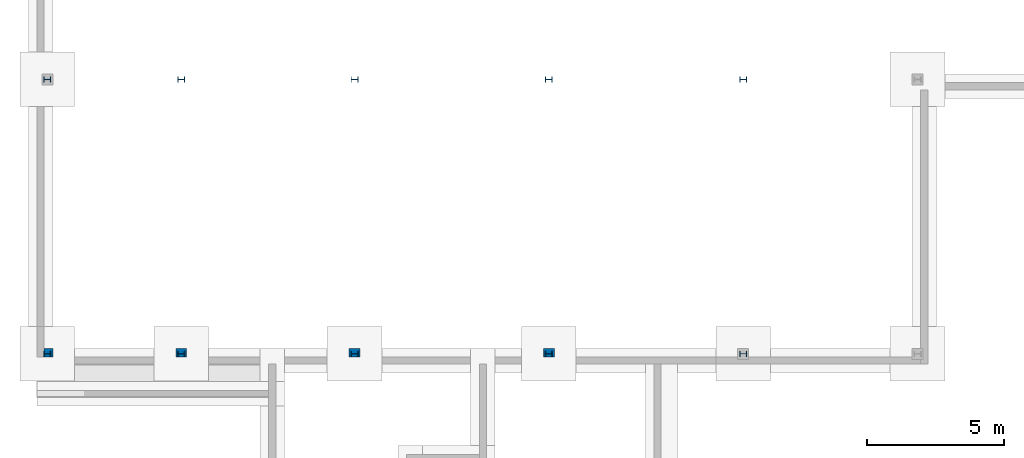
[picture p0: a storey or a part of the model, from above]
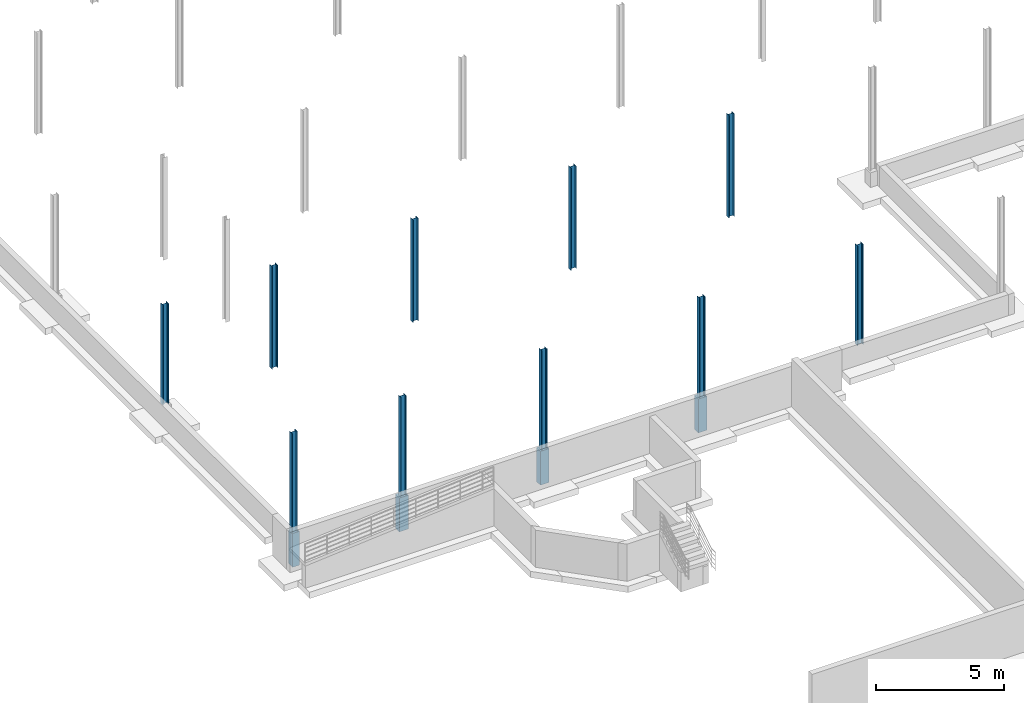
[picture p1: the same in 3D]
Properties of the parts of a building model (IFC2X3), part 1 of 3

# File
Description: ViewDefinition [CoordinationView]
File name: Project Number
Time: 2011-07-11T15:46:36
Written by: Autodesk Revit Architecture 2011 - 1.0
Made in: (Solibri IFC Optimizer)

# IfcProject, Project Number
Phase: Project Status

# IfcSite, Default
RefLatitude: 42, 21, 30, 344238; RefLongitude: -71, -3, -35, -194702; RefElevation: 0 m

# IfcBuilding
PSet_Revit_Other - Project Issue Date: Issue Date; Project Status: Project Status; Client Name: Owner; Project Address: Enter address here; Project Name: Project Name; Project Number: Project Number; Category Description: OmniClass Table 11 Description; Category Code: OmniClass Table 11 Code
Pset_BuildingCommon - NumberOfStoreys: 4

# IfcBuildingStorey (4)
PSet_Revit_Type_Dimensions - Automatic Room Computation Height: yes
PSet_Revit_Type_Graphics - Line Weight: 1; Color: 0; Line Pattern: Centre; Symbol: M_Level Head - Circle; Symbol at End 1 Default: no; Symbol at End 2 Default: yes
PSet_Revit_Type_Constraints - Elevation Base: 0
Name | Elevation (m) | Name | Category Code | PSet_Revit_Constraints, Elevation (m)
Roof - Main | 9.25 | Roof - Main | Roof | 9.25
Second Floor | 4.57 | Second Floor | Floor | 4.57
TOF Footing | -1 | TOF Footing | Site | -1
First Floor | -3.5315e-13 | First Floor | Floor | 0

# IfcBeam: M_K-Series Bar Joist-Rod Web:10K1:228953 (5)
In: First Floor
PSet_Revit_Construction - Start Offset: 0 m; Start Extension: 0 m; End Offset: 0 m; End Extension: 0 m
Pset_BeamCommon - Reference: M_K-Series Bar Joist-Rod Web:10K1; IsExternal: no; LoadBearing: yes; Span: 0.0095 m; Slope: 0 deg
PSet_Revit_Dimensions - Length: 2.367 m; Volume: 0.00307691 m3
PSet_Revit_Phasing - Phase Created: New Construction
PSet_Revit_Constraints - Work Plane: Level : Second Floor; Reference Level: Second Floor; Start Level Offset: 0 m; End Level Offset: 0 m; z-Direction Justification: 3; z-Direction Offset Value: -0.102 m; Lateral Justification: 0; Orientation: 0; Cross-Section Rotation: 0 deg
PSet_Revit_Structural Analysis - Start Release: 3; Start Fx: no; Start Fy: no; Start Fz: no; Start Mx: no; Start My: yes; Start Mz: yes; End Release: 1; End Fx: no; End Fy: no; End Fz: no; End Mx: yes; End My: yes; End Mz: yes; Analyze As: 1
PSet_Revit_Other - PanelArrayNum: 3; PanelArrayLength: 1.351 m; Panel: 0.450333 m; InstallationDate: InstallationDate; SerialNumber: SerialNumber; WarrantyStartDate: WarrantyStartDate; BarCode: BarCode; AssetIdentifier: AssetIdentifier; TagNumber: TagNumber
PSet_Revit_Analytical Model - Rigid Links: 0; Horizontal Projection: Default
PSet_Revit_Structural - Cut Length: 2.367 m; Structural Usage: 4
PSet_Revit_Type_Identity Data - Manufacturer: Manufacturer; OmniClass Number: 23.25.30.21.14.11; OmniClass Title: Metal Joists
PSet_Revit_Type_Dimensions - Web Thickness: 0.0095 m; Seat Length: 0.1 m; Seat Depth: 0.0635 m; Cord Leg: 0.032 m; Chord Thickness: 0.0065 m; Depth: 0.254 m
PSet_Revit_Type_Structural - M: 7.4
PSet_Revit_Type_Other - End Panel: 0.508 m; AccessibilityPerformance: AccessibilityPerformance; CodePerformance: CodePerformance; Color: Color; Constituents: Constituents; Features: Features; Finish: Finish; Grade: Grade; Material: Material; ModelReference: ModelReference; NominalHeight: NominalHeight; NominalLength: NominalLength; NominalWidth: NominalWidth; ProductionYear: ProductionYear; Reference: Reference; Shape: Shape; Size: Size; SustainabilityPerformance: SustainabilityPerformance; WarrantyDescription: WarrantyDescription; WarrantyDurationLabor: WarrantyDurationLabor; WarrantyDurationParts: WarrantyDurationParts; WarrantyGuarantorLabor: WarrantyGuarantorLabor; WarrantyGuarantorParts: WarrantyGuarantorParts; ExpectedLife: ExpectedLife; ReplacementCost: ReplacementCost; AssetAccountingType: FIXED; ModelLabel: ModelLabel
Name (M_K-Series Bar Joist-Rod Web:10K1:10K1:...)
228924
228926
228928
228920
228922

# IfcBeam: M_K-Series Bar Joist-Rod Web:14K1:175829 (456)
PSet_Revit_Construction - Start Offset: 0 m; Start Extension: 0 m; End Offset: 0 m; End Extension: 0 m
PSet_Revit_Phasing - Phase Created: New Construction
Pset_BeamCommon - Reference: M_K-Series Bar Joist-Rod Web:14K1; IsExternal: no; LoadBearing: yes; Span: 0.0095 m
PSet_Revit_Other - InstallationDate: InstallationDate; SerialNumber: SerialNumber; WarrantyStartDate: WarrantyStartDate; BarCode: BarCode; AssetIdentifier: AssetIdentifier; TagNumber: TagNumber
PSet_Revit_Constraints - Start Level Offset: 0 m; End Level Offset: 0 m; z-Direction Justification: 3; Lateral Justification: 0; Orientation: 0; Cross-Section Rotation: 0 deg
PSet_Revit_Structural Analysis - Start Release: 3; Start Fx: no; Start Fy: no; Start Fz: no; Start Mx: no; Start My: yes; Start Mz: yes; End Release: 1; End Fx: no; End Fy: no; End Fz: no; End Mx: yes; End My: yes; End Mz: yes; Analyze As: 1
PSet_Revit_Analytical Model - Rigid Links: 0; Horizontal Projection: Default
PSet_Revit_Structural - Structural Usage: 4
PSet_Revit_Type_Structural - M: 7.7
PSet_Revit_Type_Dimensions - Web Thickness: 0.0095 m; Seat Length: 0.1 m; Seat Depth: 0.0635 m; Cord Leg: 0.032 m; Chord Thickness: 0.0065 m; Depth: 0.356 m
PSet_Revit_Type_Identity Data - Manufacturer: Manufacturer; OmniClass Number: 23.25.30.21.14.11; OmniClass Title: Metal Joists
PSet_Revit_Type_Other - End Panel: 0.712 m; AccessibilityPerformance: AccessibilityPerformance; CodePerformance: CodePerformance; Color: Color; Constituents: Constituents; Features: Features; Finish: Finish; Grade: Grade; Material: Material; ModelReference: ModelReference; NominalHeight: NominalHeight; NominalLength: NominalLength; NominalWidth: NominalWidth; ProductionYear: ProductionYear; Reference: Reference; Shape: Shape; Size: Size; SustainabilityPerformance: SustainabilityPerformance; WarrantyDescription: WarrantyDescription; WarrantyDurationLabor: WarrantyDurationLabor; WarrantyDurationParts: WarrantyDurationParts; WarrantyGuarantorLabor: WarrantyGuarantorLabor; WarrantyGuarantorParts: WarrantyGuarantorParts; ExpectedLife: ExpectedLife; ReplacementCost: ReplacementCost; AssetAccountingType: FIXED; ModelLabel: ModelLabel
Name (M_K-Series Bar Joist-Rod Web:14K1:14K1:...) | In | Slope (deg) | PanelArrayNum | PanelArrayLength (m) | Panel (m) | Length (m) = Cut Length (m) | Volume (m3) | Work Plane | Reference Level | z-Direction Offset Value (m)
220116 | Second Floor | 0 | 11 | 7.545 | 0.685909 | 8.969 | 0.0126419 | Level : Roof - Main | Roof - Main | 0
220117 | Second Floor | 0 | 11 | 7.545 | 0.685909 | 8.969 | 0.0126419 | Level : Roof - Main | Roof - Main | 0
225612 | First Floor | 0 | 5 | 3.885 | 0.777 | 5.309 | 0.00717022 | Level : Second Floor | Second Floor | -0.102
220100 | Second Floor | 0 | 11 | 7.551 | 0.686455 | 8.975 | 0.0126509 | Level : Roof - Main | Roof - Main | 0
220081 | Second Floor | 1.30141e-30 | 11 | 7.551 | 0.686455 | 8.975 | 0.0126509 | Level : Roof - Main | Roof - Main | 0
189399 | Second Floor | 0 | 10 | 7.146 | 0.7146 | 8.57 | 0.0120454 | Level : Roof - Main | Roof - Main | 0
225467 | First Floor | 0 | 10 | 7.146 | 0.7146 | 8.57 | 0.0120454 | Level : Second Floor | Second Floor | -0.102
189397 | Second Floor | 0 | 10 | 7.146 | 0.7146 | 8.57 | 0.0120454 | Level : Roof - Main | Roof - Main | 0
225611 | First Floor | 0 | 5 | 3.885 | 0.777 | 5.309 | 0.00717022 | Level : Second Floor | Second Floor | -0.102
185401 | First Floor | 0 | 7 | 5.205 | 0.743571 | 6.629 | 0.00914362 | Level : Second Floor | Second Floor | -0.102
185451 | First Floor | 0 | 10 | 7.146 | 0.7146 | 8.57 | 0.0120454 | Level : Second Floor | Second Floor | -0.102
220080 | Second Floor | 1.30141e-30 | 11 | 7.551 | 0.686455 | 8.975 | 0.0126509 | Level : Roof - Main | Roof - Main | 0
185266 | First Floor | 0 | 6 | 4.626 | 0.771 | 6.05 | 0.00827801 | Level : Second Floor | Second Floor | -0.102
185267 | First Floor | 0 | 6 | 4.626 | 0.771 | 6.05 | 0.00827801 | Level : Second Floor | Second Floor | -0.102
220027 | Second Floor | 1.30141e-30 | 11 | 7.551 | 0.686455 | 8.975 | 0.0126509 | Level : Roof - Main | Roof - Main | 0
189395 | Second Floor | 0 | 10 | 7.146 | 0.7146 | 8.57 | 0.0120454 | Level : Roof - Main | Roof - Main | 0
220118 | Second Floor | 0 | 11 | 7.545 | 0.685909 | 8.969 | 0.0126419 | Level : Roof - Main | Roof - Main | 0
189398 | Second Floor | 0 | 10 | 7.146 | 0.7146 | 8.57 | 0.0120454 | Level : Roof - Main | Roof - Main | 0
189623 | Second Floor | 2.01996e-30 | 5 | 3.885 | 0.777 | 5.309 | 0.00717022 | Level : Roof - Main | Roof - Main | 0
185555 | First Floor | 0 | 10 | 7.146 | 0.7146 | 8.57 | 0.0120454 | Level : Second Floor | Second Floor | -0.102
189620 | Second Floor | 2.01996e-30 | 5 | 3.885 | 0.777 | 5.309 | 0.00717022 | Level : Roof - Main | Roof - Main | 0
190259 | Second Floor | 1.97385e-30 | 10 | 7.146 | 0.7146 | 8.57 | 0.0120454 | Level : Roof - Main | Roof - Main | 0
220061 | Second Floor | 0 | 11 | 7.551 | 0.686455 | 8.975 | 0.0126509 | Level : Roof - Main | Roof - Main | 0
220060 | Second Floor | 0 | 11 | 7.551 | 0.686455 | 8.975 | 0.0126509 | Level : Roof - Main | Roof - Main | 0
225615 | First Floor | 0 | 5 | 3.885 | 0.777 | 5.309 | 0.00717022 | Level : Second Floor | Second Floor | -0.102
185400 | First Floor | 0 | 7 | 5.205 | 0.743571 | 6.629 | 0.00914362 | Level : Second Floor | Second Floor | -0.102
185287 | First Floor | 0 | 12 | 8.346 | 0.6955 | 9.77 | 0.0138394 | Level : Second Floor | Second Floor | -0.102
185450 | First Floor | 0 | 10 | 7.146 | 0.7146 | 8.57 | 0.0120454 | Level : Second Floor | Second Floor | -0.102
189973 | Second Floor | 0 | 10 | 7.146 | 0.7146 | 8.57 | 0.0120454 | Level : Roof - Main | Roof - Main | 0
220097 | Second Floor | 0 | 11 | 7.551 | 0.686455 | 8.975 | 0.0126509 | Level : Roof - Main | Roof - Main | 0
185556 | First Floor | 0 | 10 | 7.146 | 0.7146 | 8.57 | 0.0120454 | Level : Second Floor | Second Floor | -0.102
185269 | First Floor | 0 | 6 | 4.626 | 0.771 | 6.05 | 0.00827801 | Level : Second Floor | Second Floor | -0.102
185362 | First Floor | 0 | 5 | 3.885 | 0.777 | 5.309 | 0.00717022 | Level : Second Floor | Second Floor | -0.102
185557 | First Floor | 0 | 10 | 7.146 | 0.7146 | 8.57 | 0.0120454 | Level : Second Floor | Second Floor | -0.102
190260 | Second Floor | 1.97385e-30 | 10 | 7.146 | 0.7146 | 8.57 | 0.0120454 | Level : Roof - Main | Roof - Main | 0
185553 | First Floor | 0 | 10 | 7.146 | 0.7146 | 8.57 | 0.0120454 | Level : Second Floor | Second Floor | -0.102
231532 | Second Floor | 0 | 11 | 7.551 | 0.686455 | 8.975 | 0.0126509 | Level : Roof - Main | Roof - Main | 0
185558 | First Floor | 0 | 10 | 7.146 | 0.7146 | 8.57 | 0.0120454 | Level : Second Floor | Second Floor | -0.102
189657 | Second Floor | 9.79552e-31 | 12 | 8.345 | 0.695417 | 9.769 | 0.0138379 | Level : Roof - Main | Roof - Main | 0
220062 | Second Floor | 0 | 11 | 7.551 | 0.686455 | 8.975 | 0.0126509 | Level : Roof - Main | Roof - Main | 0
225471 | First Floor | 0 | 10 | 7.146 | 0.7146 | 8.57 | 0.0120454 | Level : Second Floor | Second Floor | -0.102
190262 | Second Floor | 1.97385e-30 | 10 | 7.146 | 0.7146 | 8.57 | 0.0120454 | Level : Roof - Main | Roof - Main | 0
185740 | First Floor | 0 | 12 | 8.615 | 0.717917 | 10.039 | 0.0142416 | Level : Second Floor | Second Floor | -0.102
185286 | First Floor | 0 | 12 | 8.346 | 0.6955 | 9.77 | 0.0138394 | Level : Second Floor | Second Floor | -0.102
185268 | First Floor | 0 | 6 | 4.626 | 0.771 | 6.05 | 0.00827801 | Level : Second Floor | Second Floor | -0.102
225613 | First Floor | 0 | 5 | 3.885 | 0.777 | 5.309 | 0.00717022 | Level : Second Floor | Second Floor | -0.102
220112 | Second Floor | 0 | 11 | 7.545 | 0.685909 | 8.969 | 0.0126419 | Level : Roof - Main | Roof - Main | 0
189396 | Second Floor | 0 | 10 | 7.146 | 0.7146 | 8.57 | 0.0120454 | Level : Roof - Main | Roof - Main | 0
225473 | First Floor | 0 | 10 | 7.146 | 0.7146 | 8.57 | 0.0120454 | Level : Second Floor | Second Floor | -0.102
189434 | Second Floor | 0 | 10 | 7.146 | 0.7146 | 8.57 | 0.0120454 | Level : Roof - Main | Roof - Main | 0
189433 | Second Floor | 0 | 10 | 7.146 | 0.7146 | 8.57 | 0.0120454 | Level : Roof - Main | Roof - Main | 0
189725 | Second Floor | 2.01996e-30 | 5 | 3.885 | 0.777 | 5.309 | 0.00717022 | Level : Roof - Main | Roof - Main | 0
190338 | Second Floor | 1.01005e-30 | 5 | 3.886 | 0.7772 | 5.31 | 0.00717171 | Level : Roof - Main | Roof - Main | 0
220098 | Second Floor | 0 | 11 | 7.551 | 0.686455 | 8.975 | 0.0126509 | Level : Roof - Main | Roof - Main | 0
189970 | Second Floor | 0 | 10 | 7.146 | 0.7146 | 8.57 | 0.0120454 | Level : Roof - Main | Roof - Main | 0
231536 | Second Floor | 0 | 11 | 7.551 | 0.686455 | 8.975 | 0.0126509 | Level : Roof - Main | Roof - Main | 0
185492 | First Floor | 0 | 12 | 8.615 | 0.717917 | 10.039 | 0.0142416 | Level : Second Floor | Second Floor | -0.102
189464 | Second Floor | 0 | 10 | 7.146 | 0.7146 | 8.57 | 0.0120454 | Level : Roof - Main | Roof - Main | 0
220101 | Second Floor | 0 | 11 | 7.551 | 0.686455 | 8.975 | 0.0126509 | Level : Roof - Main | Roof - Main | 0
220114 | Second Floor | 0 | 11 | 7.545 | 0.685909 | 8.969 | 0.0126419 | Level : Roof - Main | Roof - Main | 0
189400 | Second Floor | 0 | 10 | 7.146 | 0.7146 | 8.57 | 0.0120454 | Level : Roof - Main | Roof - Main | 0
225616 | First Floor | 0 | 5 | 3.885 | 0.777 | 5.309 | 0.00717022 | Level : Second Floor | Second Floor | -0.102
220063 | Second Floor | 0 | 11 | 7.551 | 0.686455 | 8.975 | 0.0126509 | Level : Roof - Main | Roof - Main | 0
189411 | Second Floor | 1.97385e-30 | 10 | 7.146 | 0.7146 | 8.57 | 0.0120454 | Level : Roof - Main | Roof - Main | 0
189429 | Second Floor | 0 | 10 | 7.146 | 0.7146 | 8.57 | 0.0120454 | Level : Roof - Main | Roof - Main | 0
189968 | Second Floor | 0 | 10 | 7.146 | 0.7146 | 8.57 | 0.0120454 | Level : Roof - Main | Roof - Main | 0
220113 | Second Floor | 0 | 11 | 7.545 | 0.685909 | 8.969 | 0.0126419 | Level : Roof - Main | Roof - Main | 0
185399 | First Floor | 0 | 7 | 5.205 | 0.743571 | 6.629 | 0.00914362 | Level : Second Floor | Second Floor | -0.102
185437 | First Floor | 0 | 12 | 8.346 | 0.6955 | 9.77 | 0.0138394 | Level : Second Floor | Second Floor | -0.102
220045 | Second Floor | 1.30141e-30 | 11 | 7.551 | 0.686455 | 8.975 | 0.0126509 | Level : Roof - Main | Roof - Main | 0
189608 | Second Floor | 0 | 5 | 3.885 | 0.777 | 5.309 | 0.00717022 | Level : Roof - Main | Roof - Main | 0
185772 | First Floor | 0 | 12 | 8.615 | 0.717917 | 10.039 | 0.0142416 | Level : Second Floor | Second Floor | -0.102
189413 | Second Floor | 1.97385e-30 | 10 | 7.146 | 0.7146 | 8.57 | 0.0120454 | Level : Roof - Main | Roof - Main | 0
186278 | First Floor | 0 | 7 | 5.205 | 0.743571 | 6.629 | 0.00914362 | Level : Second Floor | Second Floor | -0.102
231535 | Second Floor | 0 | 11 | 7.551 | 0.686455 | 8.975 | 0.0126509 | Level : Roof - Main | Roof - Main | 0
185773 | First Floor | 0 | 12 | 8.615 | 0.717917 | 10.039 | 0.0142416 | Level : Second Floor | Second Floor | -0.102
189637 | Second Floor | 0 | 5 | 3.885 | 0.777 | 5.309 | 0.00717022 | Level : Roof - Main | Roof - Main | 0
220083 | Second Floor | 1.30141e-30 | 11 | 7.551 | 0.686455 | 8.975 | 0.0126509 | Level : Roof - Main | Roof - Main | 0
190339 | Second Floor | 2.01996e-30 | 5 | 3.885 | 0.777 | 5.309 | 0.00717022 | Level : Roof - Main | Roof - Main | 0
220025 | Second Floor | 1.30141e-30 | 11 | 7.551 | 0.686455 | 8.975 | 0.0126509 | Level : Roof - Main | Roof - Main | 0
220082 | Second Floor | 1.30141e-30 | 11 | 7.551 | 0.686455 | 8.975 | 0.0126509 | Level : Roof - Main | Roof - Main | 0
186277 | First Floor | 0 | 7 | 5.205 | 0.743571 | 6.629 | 0.00914362 | Level : Second Floor | Second Floor | -0.102
185538 | First Floor | 0 | 12 | 8.615 | 0.717917 | 10.039 | 0.0142416 | Level : Second Floor | Second Floor | -0.102
185491 | First Floor | 0 | 12 | 8.615 | 0.717917 | 10.039 | 0.0142416 | Level : Second Floor | Second Floor | -0.102
189853 | Second Floor | 0 | 6 | 4.626 | 0.771 | 6.05 | 0.00827801 | Level : Roof - Main | Roof - Main | 0
220028 | Second Floor | 1.30141e-30 | 11 | 7.551 | 0.686455 | 8.975 | 0.0126509 | Level : Roof - Main | Roof - Main | 0
189727 | Second Floor | 2.01996e-30 | 5 | 3.885 | 0.777 | 5.309 | 0.00717022 | Level : Roof - Main | Roof - Main | 0
220023 | Second Floor | 1.30141e-30 | 11 | 7.551 | 0.686455 | 8.975 | 0.0126509 | Level : Roof - Main | Roof - Main | 0
189707 | Second Floor | 9.79552e-31 | 12 | 8.345 | 0.695417 | 9.769 | 0.0138379 | Level : Roof - Main | Roof - Main | 0
185453 | First Floor | 0 | 10 | 7.146 | 0.7146 | 8.57 | 0.0120454 | Level : Second Floor | Second Floor | -0.102
185435 | First Floor | 0 | 12 | 8.346 | 0.6955 | 9.77 | 0.0138394 | Level : Second Floor | Second Floor | -0.102
225472 | First Floor | 0 | 10 | 7.146 | 0.7146 | 8.57 | 0.0120454 | Level : Second Floor | Second Floor | -0.102
225468 | First Floor | 0 | 10 | 7.146 | 0.7146 | 8.57 | 0.0120454 | Level : Second Floor | Second Floor | -0.102
185739 | First Floor | 0 | 12 | 8.615 | 0.717917 | 10.039 | 0.0142416 | Level : Second Floor | Second Floor | -0.102
190263 | Second Floor | 1.97385e-30 | 10 | 7.146 | 0.7146 | 8.57 | 0.0120454 | Level : Roof - Main | Roof - Main | 0
220099 | Second Floor | 0 | 11 | 7.551 | 0.686455 | 8.975 | 0.0126509 | Level : Roof - Main | Roof - Main | 0
231531 | Second Floor | 0 | 11 | 7.551 | 0.686455 | 8.975 | 0.0126509 | Level : Roof - Main | Roof - Main | 0
189622 | Second Floor | 2.01996e-30 | 5 | 3.885 | 0.777 | 5.309 | 0.00717022 | Level : Roof - Main | Roof - Main | 0
220022 | Second Floor | 1.30141e-30 | 11 | 7.551 | 0.686455 | 8.975 | 0.0126509 | Level : Roof - Main | Roof - Main | 0
186279 | First Floor | 0 | 7 | 5.205 | 0.743571 | 6.629 | 0.00914362 | Level : Second Floor | Second Floor | -0.102
225614 | First Floor | 0 | 5 | 3.885 | 0.777 | 5.309 | 0.00717022 | Level : Second Floor | Second Floor | -0.102
185534 | First Floor | 0 | 12 | 8.615 | 0.717917 | 10.039 | 0.0142416 | Level : Second Floor | Second Floor | -0.102
190336 | Second Floor | 2.01996e-30 | 5 | 3.885 | 0.777 | 5.309 | 0.00717022 | Level : Roof - Main | Roof - Main | 0
220043 | Second Floor | 1.30141e-30 | 11 | 7.551 | 0.686455 | 8.975 | 0.0126509 | Level : Roof - Main | Roof - Main | 0
220026 | Second Floor | 1.30141e-30 | 11 | 7.551 | 0.686455 | 8.975 | 0.0126509 | Level : Roof - Main | Roof - Main | 0
231533 | Second Floor | 0 | 11 | 7.551 | 0.686455 | 8.975 | 0.0126509 | Level : Roof - Main | Roof - Main | 0
188687 | First Floor | 0 | 8 | 5.511 | 0.688875 | 6.935 | 0.00960109 | Level : Second Floor | Second Floor | -0.102
220049 | Second Floor | 1.30141e-30 | 11 | 7.551 | 0.686455 | 8.975 | 0.0126509 | Level : Roof - Main | Roof - Main | 0
189415 | Second Floor | 1.97385e-30 | 10 | 7.146 | 0.7146 | 8.57 | 0.0120454 | Level : Roof - Main | Roof - Main | 0
185554 | First Floor | 0 | 10 | 7.146 | 0.7146 | 8.57 | 0.0120454 | Level : Second Floor | Second Floor | -0.102
186266 | First Floor | 6.53056e-31 | 12 | 8.346 | 0.6955 | 9.77 | 0.0138394 | Level : Second Floor | Second Floor | -0.102
220007 | Second Floor | 0 | 11 | 7.551 | 0.686455 | 8.975 | 0.0126509 | Level : Roof - Main | Roof - Main | 0
189331 | Second Floor | 0 | 12 | 8.346 | 0.6955 | 9.77 | 0.0138394 | Level : Roof - Main | Roof - Main | 0
189955 | Second Floor | 1.97385e-30 | 10 | 7.146 | 0.7146 | 8.57 | 0.0120454 | Level : Roof - Main | Roof - Main | 0
189969 | Second Floor | 0 | 10 | 7.146 | 0.7146 | 8.57 | 0.0120454 | Level : Roof - Main | Roof - Main | 0
185285 | First Floor | 0 | 12 | 8.346 | 0.6955 | 9.77 | 0.0138394 | Level : Second Floor | Second Floor | -0.102
189619 | Second Floor | 2.01996e-30 | 5 | 3.885 | 0.777 | 5.309 | 0.00717022 | Level : Roof - Main | Roof - Main | 0
220065 | Second Floor | 0 | 11 | 7.551 | 0.686455 | 8.975 | 0.0126509 | Level : Roof - Main | Roof - Main | 0
189956 | Second Floor | 1.97385e-30 | 10 | 7.146 | 0.7146 | 8.57 | 0.0120454 | Level : Roof - Main | Roof - Main | 0
185736 | First Floor | 0 | 12 | 8.615 | 0.717917 | 10.039 | 0.0142416 | Level : Second Floor | Second Floor | -0.102
225617 | First Floor | 0 | 5 | 3.885 | 0.777 | 5.309 | 0.00717022 | Level : Second Floor | Second Floor | -0.102
189462 | Second Floor | 0 | 10 | 7.146 | 0.7146 | 8.57 | 0.0120454 | Level : Roof - Main | Roof - Main | 0
185738 | First Floor | 0 | 12 | 8.615 | 0.717917 | 10.039 | 0.0142416 | Level : Second Floor | Second Floor | -0.102
189636 | Second Floor | 0 | 5 | 3.885 | 0.777 | 5.309 | 0.00717022 | Level : Roof - Main | Roof - Main | 0
185398 | First Floor | 0 | 7 | 5.205 | 0.743571 | 6.629 | 0.00914362 | Level : Second Floor | Second Floor | -0.102
189414 | Second Floor | 1.97385e-30 | 10 | 7.146 | 0.7146 | 8.57 | 0.0120454 | Level : Roof - Main | Roof - Main | 0
185769 | First Floor | 0 | 12 | 8.615 | 0.717917 | 10.039 | 0.0142416 | Level : Second Floor | Second Floor | -0.102
189671 | Second Floor | 0 | 7 | 5.205 | 0.743571 | 6.629 | 0.00914362 | Level : Roof - Main | Roof - Main | 0
225470 | First Floor | 0 | 10 | 7.146 | 0.7146 | 8.57 | 0.0120454 | Level : Second Floor | Second Floor | -0.102
186263 | First Floor | 6.53056e-31 | 12 | 8.346 | 0.6955 | 9.77 | 0.0138394 | Level : Second Floor | Second Floor | -0.102
189670 | Second Floor | 0 | 7 | 5.205 | 0.743571 | 6.629 | 0.00914362 | Level : Roof - Main | Roof - Main | 0
188689 | First Floor | 0 | 8 | 5.511 | 0.688875 | 6.935 | 0.00960109 | Level : Second Floor | Second Floor | -0.102
189639 | Second Floor | 0 | 5 | 3.885 | 0.777 | 5.309 | 0.00717022 | Level : Roof - Main | Roof - Main | 0
189972 | Second Floor | 0 | 10 | 7.146 | 0.7146 | 8.57 | 0.0120454 | Level : Roof - Main | Roof - Main | 0
189669 | Second Floor | 0 | 7 | 5.205 | 0.743571 | 6.629 | 0.00914362 | Level : Roof - Main | Roof - Main | 0
185288 | First Floor | 0 | 12 | 8.346 | 0.6955 | 9.77 | 0.0138394 | Level : Second Floor | Second Floor | -0.102
190337 | Second Floor | 2.01996e-30 | 5 | 3.885 | 0.777 | 5.309 | 0.00717022 | Level : Roof - Main | Roof - Main | 0
185668 | First Floor | 0 | 10 | 7.146 | 0.7146 | 8.57 | 0.0120454 | Level : Second Floor | Second Floor | -0.102
220024 | Second Floor | 1.30141e-30 | 11 | 7.551 | 0.686455 | 8.975 | 0.0126509 | Level : Roof - Main | Roof - Main | 0
189705 | Second Floor | 9.79552e-31 | 12 | 8.345 | 0.695417 | 9.769 | 0.0138379 | Level : Roof - Main | Roof - Main | 0
185774 | First Floor | 0 | 12 | 8.615 | 0.717917 | 10.039 | 0.0142416 | Level : Second Floor | Second Floor | -0.102
185490 | First Floor | 0 | 12 | 8.615 | 0.717917 | 10.039 | 0.0142416 | Level : Second Floor | Second Floor | -0.102
189640 | Second Floor | 0 | 5 | 3.885 | 0.777 | 5.309 | 0.00717022 | Level : Roof - Main | Roof - Main | 0
189854 | Second Floor | 0 | 6 | 4.626 | 0.771 | 6.05 | 0.00827801 | Level : Roof - Main | Roof - Main | 0
188688 | First Floor | 0 | 8 | 5.511 | 0.688875 | 6.935 | 0.00960109 | Level : Second Floor | Second Floor | -0.102
190261 | Second Floor | 1.97385e-30 | 10 | 7.146 | 0.7146 | 8.57 | 0.0120454 | Level : Roof - Main | Roof - Main | 0
185824 | First Floor | 0 | 12 | 8.346 | 0.6955 | 9.77 | 0.0138394 | Level : Second Floor | Second Floor | -0.102
231534 | Second Floor | 0 | 11 | 7.551 | 0.686455 | 8.975 | 0.0126509 | Level : Roof - Main | Roof - Main | 0
185735 | First Floor | 0 | 12 | 8.615 | 0.717917 | 10.039 | 0.0142416 | Level : Second Floor | Second Floor | -0.102
220047 | Second Floor | 1.30141e-30 | 11 | 7.551 | 0.686455 | 8.975 | 0.0126509 | Level : Roof - Main | Roof - Main | 0
185434 | First Floor | 0 | 12 | 8.346 | 0.6955 | 9.77 | 0.0138394 | Level : Second Floor | Second Floor | -0.102
185669 | First Floor | 0 | 10 | 7.146 | 0.7146 | 8.57 | 0.0120454 | Level : Second Floor | Second Floor | -0.102
189635 | Second Floor | 0 | 5 | 3.885 | 0.777 | 5.309 | 0.00717022 | Level : Roof - Main | Roof - Main | 0
220096 | Second Floor | 0 | 11 | 7.551 | 0.686455 | 8.975 | 0.0126509 | Level : Roof - Main | Roof - Main | 0
189668 | Second Floor | 0 | 7 | 5.205 | 0.743571 | 6.629 | 0.00914362 | Level : Roof - Main | Roof - Main | 0
220001 | Second Floor | 0 | 11 | 7.551 | 0.686455 | 8.975 | 0.0126509 | Level : Roof - Main | Roof - Main | 0
189306 | Second Floor | 0 | 5 | 3.885 | 0.777 | 5.309 | 0.00717022 | Level : Roof - Main | Roof - Main | 0
189431 | Second Floor | 0 | 10 | 7.146 | 0.7146 | 8.57 | 0.0120454 | Level : Roof - Main | Roof - Main | 0
188686 | First Floor | 0 | 8 | 5.511 | 0.688875 | 6.935 | 0.00960109 | Level : Second Floor | Second Floor | -0.102
189412 | Second Floor | 1.97385e-30 | 10 | 7.146 | 0.7146 | 8.57 | 0.0120454 | Level : Roof - Main | Roof - Main | 0
189724 | Second Floor | 2.01996e-30 | 5 | 3.885 | 0.777 | 5.309 | 0.00717022 | Level : Roof - Main | Roof - Main | 0
185539 | First Floor | 0 | 12 | 8.615 | 0.717917 | 10.039 | 0.0142416 | Level : Second Floor | Second Floor | -0.102
220066 | Second Floor | 0 | 11 | 7.551 | 0.686455 | 8.975 | 0.0126509 | Level : Roof - Main | Roof - Main | 0
189654 | Second Floor | 9.79552e-31 | 12 | 8.345 | 0.695417 | 9.769 | 0.0138379 | Level : Roof - Main | Roof - Main | 0
186281 | First Floor | 0 | 7 | 5.205 | 0.743571 | 6.629 | 0.00914362 | Level : Second Floor | Second Floor | -0.102
185752 | First Floor | 0 | 12 | 8.615 | 0.717917 | 10.039 | 0.0142416 | Level : Second Floor | Second Floor | -0.102
185756 | First Floor | 0 | 12 | 8.615 | 0.717917 | 10.039 | 0.0142416 | Level : Second Floor | Second Floor | -0.102
185632 | First Floor | 0 | 12 | 8.346 | 0.6955 | 9.77 | 0.0138394 | Level : Second Floor | Second Floor | -0.102
189428 | Second Floor | 0 | 10 | 7.146 | 0.7146 | 8.57 | 0.0120454 | Level : Roof - Main | Roof - Main | 0
219950 | Second Floor | 0 | 11 | 7.551 | 0.686455 | 8.975 | 0.0126509 | Level : Roof - Main | Roof - Main | 0
225469 | First Floor | 0 | 10 | 7.146 | 0.7146 | 8.57 | 0.0120454 | Level : Second Floor | Second Floor | -0.102
219990 | Second Floor | 1.30141e-30 | 11 | 7.551 | 0.686455 | 8.975 | 0.0126509 | Level : Roof - Main | Roof - Main | 0
189706 | Second Floor | 9.79552e-31 | 12 | 8.345 | 0.695417 | 9.769 | 0.0138379 | Level : Roof - Main | Roof - Main | 0
188723 | First Floor | 0 | 2 | 1.41 | 0.705 | 2.834 | 0.00347009 | Level : Second Floor | Second Floor | -0.102
185631 | First Floor | 0 | 12 | 8.346 | 0.6955 | 9.77 | 0.0138394 | Level : Second Floor | Second Floor | -0.102
185537 | First Floor | 0 | 12 | 8.615 | 0.717917 | 10.039 | 0.0142416 | Level : Second Floor | Second Floor | -0.102
189465 | Second Floor | 0 | 10 | 7.146 | 0.7146 | 8.57 | 0.0120454 | Level : Roof - Main | Roof - Main | 0
185535 | First Floor | 0 | 12 | 8.615 | 0.717917 | 10.039 | 0.0142416 | Level : Second Floor | Second Floor | -0.102
186299 | First Floor | 0 | 12 | 8.346 | 0.6955 | 9.77 | 0.0138394 | Level : Second Floor | Second Floor | -0.102
189730 | Second Floor | 2.01996e-30 | 5 | 3.885 | 0.777 | 5.309 | 0.00717022 | Level : Roof - Main | Roof - Main | 0
190335 | Second Floor | 2.01996e-30 | 5 | 3.885 | 0.777 | 5.309 | 0.00717022 | Level : Roof - Main | Roof - Main | 0
190341 | Second Floor | 2.01996e-30 | 5 | 3.885 | 0.777 | 5.309 | 0.00717022 | Level : Roof - Main | Roof - Main | 0
185617 | First Floor | 0 | 6 | 4.626 | 0.771 | 6.05 | 0.00827801 | Level : Second Floor | Second Floor | -0.102
189430 | Second Floor | 0 | 10 | 7.146 | 0.7146 | 8.57 | 0.0120454 | Level : Roof - Main | Roof - Main | 0
189417 | Second Floor | 1.97385e-30 | 10 | 7.146 | 0.7146 | 8.57 | 0.0120454 | Level : Roof - Main | Roof - Main | 0
189702 | Second Floor | 9.79552e-31 | 12 | 8.345 | 0.695417 | 9.769 | 0.0138379 | Level : Roof - Main | Roof - Main | 0
189621 | Second Floor | 2.01996e-30 | 5 | 3.885 | 0.777 | 5.309 | 0.00717022 | Level : Roof - Main | Roof - Main | 0
220079 | Second Floor | 1.30141e-30 | 11 | 7.551 | 0.686455 | 8.975 | 0.0126509 | Level : Roof - Main | Roof - Main | 0
189335 | Second Floor | 0 | 12 | 8.345 | 0.695417 | 9.769 | 0.0138379 | Level : Roof - Main | Roof - Main | 0
189652 | Second Floor | 6.53056e-31 | 12 | 8.346 | 0.6955 | 9.77 | 0.0138394 | Level : Roof - Main | Roof - Main | 0
188772 | First Floor | 1.31467e-30 | 6 | 4.273 | 0.712167 | 5.697 | 0.00775028 | Level : Second Floor | Second Floor | -0.102
185718 | First Floor | 0 | 12 | 8.346 | 0.6955 | 9.77 | 0.0138394 | Level : Second Floor | Second Floor | -0.102
190340 | Second Floor | 2.01996e-30 | 5 | 3.885 | 0.777 | 5.309 | 0.00717022 | Level : Roof - Main | Roof - Main | 0
189726 | Second Floor | 2.01996e-30 | 5 | 3.885 | 0.777 | 5.309 | 0.00717022 | Level : Roof - Main | Roof - Main | 0
185363 | First Floor | 0 | 5 | 3.885 | 0.777 | 5.309 | 0.00717022 | Level : Second Floor | Second Floor | -0.102
189690 | Second Floor | 9.79552e-31 | 12 | 8.345 | 0.695417 | 9.769 | 0.0138379 | Level : Roof - Main | Roof - Main | 0
185823 | First Floor | 0 | 12 | 8.346 | 0.6955 | 9.77 | 0.0138394 | Level : Second Floor | Second Floor | -0.102
189691 | Second Floor | 9.79552e-31 | 12 | 8.345 | 0.695417 | 9.769 | 0.0138379 | Level : Roof - Main | Roof - Main | 0
220115 | Second Floor | 0 | 11 | 7.545 | 0.685909 | 8.969 | 0.0126419 | Level : Roof - Main | Roof - Main | 0
189416 | Second Floor | 1.97385e-30 | 10 | 7.146 | 0.7146 | 8.57 | 0.0120454 | Level : Roof - Main | Roof - Main | 0
189586 | Second Floor | 0 | 5 | 3.885 | 0.777 | 5.309 | 0.00717022 | Level : Roof - Main | Roof - Main | 0
189463 | Second Floor | 0 | 10 | 7.146 | 0.7146 | 8.57 | 0.0120454 | Level : Roof - Main | Roof - Main | 0
189634 | Second Floor | 0 | 5 | 3.885 | 0.777 | 5.309 | 0.00717022 | Level : Roof - Main | Roof - Main | 0
186265 | First Floor | 6.53056e-31 | 12 | 8.346 | 0.6955 | 9.77 | 0.0138394 | Level : Second Floor | Second Floor | -0.102
189953 | Second Floor | 1.97385e-30 | 10 | 7.146 | 0.7146 | 8.57 | 0.0120454 | Level : Roof - Main | Roof - Main | 0
219946 | Second Floor | 0 | 11 | 7.551 | 0.686455 | 8.975 | 0.0126509 | Level : Roof - Main | Roof - Main | 0
189590 | Second Floor | 0 | 5 | 3.885 | 0.777 | 5.309 | 0.00717022 | Level : Roof - Main | Roof - Main | 0
220064 | Second Floor | 0 | 11 | 7.551 | 0.686455 | 8.975 | 0.0126509 | Level : Roof - Main | Roof - Main | 0
186298 | First Floor | 0 | 12 | 8.346 | 0.6955 | 9.77 | 0.0138394 | Level : Second Floor | Second Floor | -0.102
188690 | First Floor | 0 | 8 | 5.511 | 0.688875 | 6.935 | 0.00960109 | Level : Second Floor | Second Floor | -0.102
188758 | First Floor | 0 | 10 | 7.146 | 0.7146 | 8.57 | 0.0120454 | Level : Second Floor | Second Floor | -0.102
220006 | Second Floor | 0 | 11 | 7.551 | 0.686455 | 8.975 | 0.0126509 | Level : Roof - Main | Roof - Main | 0
189967 | Second Floor | 0 | 10 | 7.146 | 0.7146 | 8.57 | 0.0120454 | Level : Roof - Main | Roof - Main | 0
190265 | Second Floor | 1.97385e-30 | 10 | 7.146 | 0.7146 | 8.57 | 0.0120454 | Level : Roof - Main | Roof - Main | 0
185436 | First Floor | 0 | 12 | 8.346 | 0.6955 | 9.77 | 0.0138394 | Level : Second Floor | Second Floor | -0.102
189651 | Second Floor | 6.53056e-31 | 12 | 8.346 | 0.6955 | 9.77 | 0.0138394 | Level : Roof - Main | Roof - Main | 0
185722 | First Floor | 0 | 12 | 8.346 | 0.6955 | 9.77 | 0.0138394 | Level : Second Floor | Second Floor | -0.102
189606 | Second Floor | 0 | 5 | 3.885 | 0.777 | 5.309 | 0.00717022 | Level : Roof - Main | Roof - Main | 0
219988 | Second Floor | 1.30141e-30 | 11 | 7.551 | 0.686455 | 8.975 | 0.0126509 | Level : Roof - Main | Roof - Main | 0
220044 | Second Floor | 1.30141e-30 | 11 | 7.551 | 0.686455 | 8.975 | 0.0126509 | Level : Roof - Main | Roof - Main | 0
185719 | First Floor | 0 | 12 | 8.346 | 0.6955 | 9.77 | 0.0138394 | Level : Second Floor | Second Floor | -0.102
186294 | First Floor | 0 | 12 | 8.346 | 0.6955 | 9.77 | 0.0138394 | Level : Second Floor | Second Floor | -0.102
186120 | First Floor | 0 | 12 | 8.346 | 0.6955 | 9.77 | 0.0138394 | Level : Second Floor | Second Floor | -0.102
185452 | First Floor | 0 | 10 | 7.146 | 0.7146 | 8.57 | 0.0120454 | Level : Second Floor | Second Floor | -0.102
189638 | Second Floor | 0 | 5 | 3.885 | 0.777 | 5.309 | 0.00717022 | Level : Roof - Main | Roof - Main | 0
186250 | First Floor | 0 | 7 | 5.205 | 0.743571 | 6.629 | 0.00914362 | Level : Second Floor | Second Floor | -0.102
185493 | First Floor | 0 | 12 | 8.615 | 0.717917 | 10.039 | 0.0142416 | Level : Second Floor | Second Floor | -0.102
185958 | First Floor | 0 | 12 | 8.345 | 0.695417 | 9.769 | 0.0138379 | Level : Second Floor | Second Floor | -0.102
189728 | Second Floor | 2.01996e-30 | 5 | 3.885 | 0.777 | 5.309 | 0.00717022 | Level : Roof - Main | Roof - Main | 0
185737 | First Floor | 0 | 12 | 8.615 | 0.717917 | 10.039 | 0.0142416 | Level : Second Floor | Second Floor | -0.102
185653 | First Floor | 0 | 5 | 3.885 | 0.777 | 5.309 | 0.00717022 | Level : Second Floor | Second Floor | -0.102
186295 | First Floor | 0 | 12 | 8.346 | 0.6955 | 9.77 | 0.0138394 | Level : Second Floor | Second Floor | -0.102
186148 | First Floor | 0 | 6 | 4.626 | 0.771 | 6.05 | 0.00827801 | Level : Second Floor | Second Floor | -0.102
186283 | First Floor | 0 | 7 | 5.205 | 0.743571 | 6.629 | 0.00914362 | Level : Second Floor | Second Floor | -0.102
189656 | Second Floor | 6.53056e-31 | 12 | 8.346 | 0.6955 | 9.77 | 0.0138394 | Level : Roof - Main | Roof - Main | 0
189467 | Second Floor | 0 | 10 | 7.146 | 0.7146 | 8.57 | 0.0120454 | Level : Roof - Main | Roof - Main | 0
189379 | Second Floor | 0 | 7 | 5.205 | 0.743571 | 6.629 | 0.00914362 | Level : Roof - Main | Roof - Main | 0
189687 | Second Floor | 9.79552e-31 | 12 | 8.345 | 0.695417 | 9.769 | 0.0138379 | Level : Roof - Main | Roof - Main | 0
219987 | Second Floor | 1.30141e-30 | 11 | 7.551 | 0.686455 | 8.975 | 0.0126509 | Level : Roof - Main | Roof - Main | 0
220048 | Second Floor | 1.30141e-30 | 11 | 7.551 | 0.686455 | 8.975 | 0.0126509 | Level : Roof - Main | Roof - Main | 0
185741 | First Floor | 0 | 12 | 8.615 | 0.717917 | 10.039 | 0.0142416 | Level : Second Floor | Second Floor | -0.102
186262 | First Floor | 6.53056e-31 | 12 | 8.346 | 0.6955 | 9.77 | 0.0138394 | Level : Second Floor | Second Floor | -0.102
185758 | First Floor | 0 | 12 | 8.615 | 0.717917 | 10.039 | 0.0142416 | Level : Second Floor | Second Floor | -0.102
186132 | First Floor | 0 | 5 | 3.885 | 0.777 | 5.309 | 0.00717022 | Level : Second Floor | Second Floor | -0.102
185536 | First Floor | 0 | 12 | 8.615 | 0.717917 | 10.039 | 0.0142416 | Level : Second Floor | Second Floor | -0.102
190264 | Second Floor | 1.97385e-30 | 10 | 7.146 | 0.7146 | 8.57 | 0.0120454 | Level : Roof - Main | Roof - Main | 0
185933 | First Floor | 0 | 12 | 8.346 | 0.6955 | 9.77 | 0.0138394 | Level : Second Floor | Second Floor | -0.102
189688 | Second Floor | 9.79552e-31 | 12 | 8.345 | 0.695417 | 9.769 | 0.0138379 | Level : Roof - Main | Roof - Main | 0
186131 | First Floor | 0 | 5 | 3.885 | 0.777 | 5.309 | 0.00717022 | Level : Second Floor | Second Floor | -0.102
189952 | Second Floor | 1.97385e-30 | 10 | 7.146 | 0.7146 | 8.57 | 0.0120454 | Level : Roof - Main | Roof - Main | 0
189729 | Second Floor | 2.01996e-30 | 5 | 3.885 | 0.777 | 5.309 | 0.00717022 | Level : Roof - Main | Roof - Main | 0
189333 | Second Floor | 0 | 12 | 8.346 | 0.6955 | 9.77 | 0.0138394 | Level : Roof - Main | Roof - Main | 0
185959 | First Floor | 0 | 12 | 8.345 | 0.695417 | 9.769 | 0.0138379 | Level : Second Floor | Second Floor | -0.102
189382 | Second Floor | 0 | 7 | 5.205 | 0.743571 | 6.629 | 0.00914362 | Level : Roof - Main | Roof - Main | 0
188759 | First Floor | 0 | 10 | 7.146 | 0.7146 | 8.57 | 0.0120454 | Level : Second Floor | Second Floor | -0.102
189672 | Second Floor | 0 | 7 | 5.205 | 0.743571 | 6.629 | 0.00914362 | Level : Roof - Main | Roof - Main | 0
185365 | First Floor | 0 | 5 | 3.885 | 0.777 | 5.309 | 0.00717022 | Level : Second Floor | Second Floor | -0.102
189466 | Second Floor | 0 | 10 | 7.146 | 0.7146 | 8.57 | 0.0120454 | Level : Roof - Main | Roof - Main | 0
189674 | Second Floor | 0 | 7 | 5.205 | 0.743571 | 6.629 | 0.00914362 | Level : Roof - Main | Roof - Main | 0
185636 | First Floor | 0 | 12 | 8.346 | 0.6955 | 9.77 | 0.0138394 | Level : Second Floor | Second Floor | -0.102
189653 | Second Floor | 6.53056e-31 | 12 | 8.346 | 0.6955 | 9.77 | 0.0138394 | Level : Roof - Main | Roof - Main | 0
185771 | First Floor | 0 | 12 | 8.615 | 0.717917 | 10.039 | 0.0142416 | Level : Second Floor | Second Floor | -0.102
189309 | Second Floor | 0 | 5 | 3.885 | 0.777 | 5.309 | 0.00717022 | Level : Roof - Main | Roof - Main | 0
185667 | First Floor | 0 | 10 | 7.146 | 0.7146 | 8.57 | 0.0120454 | Level : Second Floor | Second Floor | -0.102
186081 | First Floor | 0 | 12 | 8.346 | 0.6955 | 9.77 | 0.0138394 | Level : Second Floor | Second Floor | -0.102
186282 | First Floor | 0 | 7 | 5.205 | 0.743571 | 6.629 | 0.00914362 | Level : Second Floor | Second Floor | -0.102
186264 | First Floor | 6.53056e-31 | 12 | 8.346 | 0.6955 | 9.77 | 0.0138394 | Level : Second Floor | Second Floor | -0.102
185670 | First Floor | 0 | 10 | 7.146 | 0.7146 | 8.57 | 0.0120454 | Level : Second Floor | Second Floor | -0.102
188805 | First Floor | 1.31467e-30 | 6 | 4.273 | 0.712167 | 5.697 | 0.00775028 | Level : Second Floor | Second Floor | -0.102
219951 | Second Floor | 0 | 11 | 7.551 | 0.686455 | 8.975 | 0.0126509 | Level : Roof - Main | Roof - Main | 0
188724 | First Floor | 0 | 2 | 1.41 | 0.705 | 2.834 | 0.00347009 | Level : Second Floor | Second Floor | -0.102
188806 | First Floor | 1.31467e-30 | 6 | 4.273 | 0.712167 | 5.697 | 0.00775028 | Level : Second Floor | Second Floor | -0.102
188819 | First Floor | 1.97385e-30 | 10 | 7.146 | 0.7146 | 8.57 | 0.0120454 | Level : Second Floor | Second Floor | -0.102
185630 | First Floor | 0 | 12 | 8.346 | 0.6955 | 9.77 | 0.0138394 | Level : Second Floor | Second Floor | -0.102
220002 | Second Floor | 0 | 11 | 7.551 | 0.686455 | 8.975 | 0.0126509 | Level : Roof - Main | Roof - Main | 0
189332 | Second Floor | 0 | 12 | 8.346 | 0.6955 | 9.77 | 0.0138394 | Level : Roof - Main | Roof - Main | 0
186280 | First Floor | 0 | 7 | 5.205 | 0.743571 | 6.629 | 0.00914362 | Level : Second Floor | Second Floor | -0.102
185606 | First Floor | 0 | 6 | 4.626 | 0.771 | 6.05 | 0.00827801 | Level : Second Floor | Second Floor | -0.102
185955 | First Floor | 0 | 12 | 8.345 | 0.695417 | 9.769 | 0.0138379 | Level : Second Floor | Second Floor | -0.102
189971 | Second Floor | 0 | 10 | 7.146 | 0.7146 | 8.57 | 0.0120454 | Level : Roof - Main | Roof - Main | 0
185704 | First Floor | 0 | 10 | 7.146 | 0.7146 | 8.57 | 0.0120454 | Level : Second Floor | Second Floor | -0.102
189704 | Second Floor | 9.79552e-31 | 12 | 8.345 | 0.695417 | 9.769 | 0.0138379 | Level : Roof - Main | Roof - Main | 0
185706 | First Floor | 0 | 10 | 7.146 | 0.7146 | 8.57 | 0.0120454 | Level : Second Floor | Second Floor | -0.102
189432 | Second Floor | 0 | 10 | 7.146 | 0.7146 | 8.57 | 0.0120454 | Level : Roof - Main | Roof - Main | 0
189311 | Second Floor | 0 | 5 | 3.885 | 0.777 | 5.309 | 0.00717022 | Level : Roof - Main | Roof - Main | 0
189604 | Second Floor | 0 | 5 | 3.885 | 0.777 | 5.309 | 0.00717022 | Level : Roof - Main | Roof - Main | 0
189381 | Second Floor | 0 | 7 | 5.205 | 0.743571 | 6.629 | 0.00914362 | Level : Roof - Main | Roof - Main | 0
186245 | First Floor | 0 | 7 | 5.205 | 0.743571 | 6.629 | 0.00914362 | Level : Second Floor | Second Floor | -0.102
189655 | Second Floor | 6.53056e-31 | 12 | 8.346 | 0.6955 | 9.77 | 0.0138394 | Level : Roof - Main | Roof - Main | 0
220046 | Second Floor | 1.30141e-30 | 11 | 7.551 | 0.686455 | 8.975 | 0.0126509 | Level : Roof - Main | Roof - Main | 0
185953 | First Floor | 0 | 12 | 8.345 | 0.695417 | 9.769 | 0.0138379 | Level : Second Floor | Second Floor | -0.102
185603 | First Floor | 0 | 6 | 4.626 | 0.771 | 6.05 | 0.00827801 | Level : Second Floor | Second Floor | -0.102
185954 | First Floor | 0 | 12 | 8.345 | 0.695417 | 9.769 | 0.0138379 | Level : Second Floor | Second Floor | -0.102
186297 | First Floor | 0 | 12 | 8.346 | 0.6955 | 9.77 | 0.0138394 | Level : Second Floor | Second Floor | -0.102
188390 | First Floor | 0 | 8 | 5.978 | 0.74725 | 7.402 | 0.0102993 | Level : Second Floor | Second Floor | -0.102
189336 | Second Floor | 0 | 12 | 8.346 | 0.6955 | 9.77 | 0.0138394 | Level : Roof - Main | Roof - Main | 0
189673 | Second Floor | 0 | 7 | 5.205 | 0.743571 | 6.629 | 0.00914362 | Level : Roof - Main | Roof - Main | 0
186134 | First Floor | 0 | 5 | 3.885 | 0.777 | 5.309 | 0.00717022 | Level : Second Floor | Second Floor | -0.102
188821 | First Floor | 1.97385e-30 | 10 | 7.146 | 0.7146 | 8.57 | 0.0120454 | Level : Second Floor | Second Floor | -0.102
185935 | First Floor | 0 | 12 | 8.346 | 0.6955 | 9.77 | 0.0138394 | Level : Second Floor | Second Floor | -0.102
219948 | Second Floor | 0 | 11 | 7.551 | 0.686455 | 8.975 | 0.0126509 | Level : Roof - Main | Roof - Main | 0
219989 | Second Floor | 1.30141e-30 | 11 | 7.551 | 0.686455 | 8.975 | 0.0126509 | Level : Roof - Main | Roof - Main | 0
186151 | First Floor | 0 | 6 | 4.626 | 0.771 | 6.05 | 0.00827801 | Level : Second Floor | Second Floor | -0.102
185754 | First Floor | 0 | 12 | 8.615 | 0.717917 | 10.039 | 0.0142416 | Level : Second Floor | Second Floor | -0.102
186016 | First Floor | 0 | 12 | 8.346 | 0.6955 | 9.77 | 0.0138394 | Level : Second Floor | Second Floor | -0.102
189310 | Second Floor | 0 | 5 | 3.885 | 0.777 | 5.309 | 0.00717022 | Level : Roof - Main | Roof - Main | 0
188760 | First Floor | 0 | 10 | 7.146 | 0.7146 | 8.57 | 0.0120454 | Level : Second Floor | Second Floor | -0.102
185574 | First Floor | 0 | 12 | 8.346 | 0.6955 | 9.77 | 0.0138394 | Level : Second Floor | Second Floor | -0.102
186068 | First Floor | 0 | 5 | 3.885 | 0.777 | 5.309 | 0.00717022 | Level : Second Floor | Second Floor | -0.102
189380 | Second Floor | 0 | 7 | 5.205 | 0.743571 | 6.629 | 0.00914362 | Level : Roof - Main | Roof - Main | 0
189587 | Second Floor | 0 | 5 | 3.885 | 0.777 | 5.309 | 0.00717022 | Level : Roof - Main | Roof - Main | 0
185650 | First Floor | 0 | 5 | 3.885 | 0.777 | 5.309 | 0.00717022 | Level : Second Floor | Second Floor | -0.102
186014 | First Floor | 0 | 12 | 8.346 | 0.6955 | 9.77 | 0.0138394 | Level : Second Floor | Second Floor | -0.102
189689 | Second Floor | 9.79552e-31 | 12 | 8.345 | 0.695417 | 9.769 | 0.0138379 | Level : Roof - Main | Roof - Main | 0
185721 | First Floor | 0 | 12 | 8.346 | 0.6955 | 9.77 | 0.0138394 | Level : Second Floor | Second Floor | -0.102
185956 | First Floor | 0 | 12 | 8.345 | 0.695417 | 9.769 | 0.0138379 | Level : Second Floor | Second Floor | -0.102
185753 | First Floor | 0 | 12 | 8.615 | 0.717917 | 10.039 | 0.0142416 | Level : Second Floor | Second Floor | -0.102
185671 | First Floor | 0 | 10 | 7.146 | 0.7146 | 8.57 | 0.0120454 | Level : Second Floor | Second Floor | -0.102
189334 | Second Floor | 0 | 12 | 8.346 | 0.6955 | 9.77 | 0.0138394 | Level : Roof - Main | Roof - Main | 0
219947 | Second Floor | 0 | 11 | 7.551 | 0.686455 | 8.975 | 0.0126509 | Level : Roof - Main | Roof - Main | 0
188820 | First Floor | 1.97385e-30 | 10 | 7.146 | 0.7146 | 8.57 | 0.0120454 | Level : Second Floor | Second Floor | -0.102
219945 | Second Floor | 0 | 11 | 7.551 | 0.686455 | 8.975 | 0.0126509 | Level : Roof - Main | Roof - Main | 0
186261 | First Floor | 6.53056e-31 | 12 | 8.346 | 0.6955 | 9.77 | 0.0138394 | Level : Second Floor | Second Floor | -0.102
186154 | First Floor | 0 | 6 | 4.626 | 0.771 | 6.05 | 0.00827801 | Level : Second Floor | Second Floor | -0.102
186153 | First Floor | 0 | 6 | 4.626 | 0.771 | 6.05 | 0.00827801 | Level : Second Floor | Second Floor | -0.102
189686 | Second Floor | 9.79552e-31 | 12 | 8.345 | 0.695417 | 9.769 | 0.0138379 | Level : Roof - Main | Roof - Main | 0
186300 | First Floor | 0 | 12 | 8.346 | 0.6955 | 9.77 | 0.0138394 | Level : Second Floor | Second Floor | -0.102
189685 | Second Floor | 9.79552e-31 | 12 | 8.345 | 0.695417 | 9.769 | 0.0138379 | Level : Roof - Main | Roof - Main | 0
189605 | Second Floor | 0 | 5 | 3.885 | 0.777 | 5.309 | 0.00717022 | Level : Roof - Main | Roof - Main | 0
185572 | First Floor | 0 | 12 | 8.346 | 0.6955 | 9.77 | 0.0138394 | Level : Second Floor | Second Floor | -0.102
185364 | First Floor | 0 | 5 | 3.885 | 0.777 | 5.309 | 0.00717022 | Level : Second Floor | Second Floor | -0.102
219949 | Second Floor | 0 | 11 | 7.551 | 0.686455 | 8.975 | 0.0126509 | Level : Roof - Main | Roof - Main | 0
186118 | First Floor | 0 | 12 | 8.346 | 0.6955 | 9.77 | 0.0138394 | Level : Second Floor | Second Floor | -0.102
188807 | First Floor | 1.31467e-30 | 6 | 4.273 | 0.712167 | 5.697 | 0.00775028 | Level : Second Floor | Second Floor | -0.102
185720 | First Floor | 0 | 12 | 8.346 | 0.6955 | 9.77 | 0.0138394 | Level : Second Floor | Second Floor | -0.102
185701 | First Floor | 0 | 10 | 7.146 | 0.7146 | 8.57 | 0.0120454 | Level : Second Floor | Second Floor | -0.102
189607 | Second Floor | 0 | 5 | 3.885 | 0.777 | 5.309 | 0.00717022 | Level : Roof - Main | Roof - Main | 0
219986 | Second Floor | 1.30141e-30 | 11 | 7.551 | 0.686455 | 8.975 | 0.0126509 | Level : Roof - Main | Roof - Main | 0
186149 | First Floor | 0 | 6 | 4.626 | 0.771 | 6.05 | 0.00827801 | Level : Second Floor | Second Floor | -0.102
186116 | First Floor | 0 | 12 | 8.346 | 0.6955 | 9.77 | 0.0138394 | Level : Second Floor | Second Floor | -0.102
186066 | First Floor | 0 | 5 | 3.885 | 0.777 | 5.309 | 0.00717022 | Level : Second Floor | Second Floor | -0.102
185703 | First Floor | 0 | 10 | 7.146 | 0.7146 | 8.57 | 0.0120454 | Level : Second Floor | Second Floor | -0.102
185770 | First Floor | 0 | 12 | 8.615 | 0.717917 | 10.039 | 0.0142416 | Level : Second Floor | Second Floor | -0.102
185684 | First Floor | 0 | 10 | 7.146 | 0.7146 | 8.57 | 0.0120454 | Level : Second Floor | Second Floor | -0.102
185755 | First Floor | 0 | 12 | 8.615 | 0.717917 | 10.039 | 0.0142416 | Level : Second Floor | Second Floor | -0.102
185651 | First Floor | 0 | 5 | 3.885 | 0.777 | 5.309 | 0.00717022 | Level : Second Floor | Second Floor | -0.102
189954 | Second Floor | 1.97385e-30 | 10 | 7.146 | 0.7146 | 8.57 | 0.0120454 | Level : Roof - Main | Roof - Main | 0
189052 | First Floor | 0 | 7 | 5.205 | 0.743571 | 6.629 | 0.00914362 | Level : Second Floor | Second Floor | -0.102
186115 | First Floor | 0 | 12 | 8.346 | 0.6955 | 9.77 | 0.0138394 | Level : Second Floor | Second Floor | -0.102
186296 | First Floor | 0 | 12 | 8.346 | 0.6955 | 9.77 | 0.0138394 | Level : Second Floor | Second Floor | -0.102
186136 | First Floor | 0 | 5 | 3.885 | 0.777 | 5.309 | 0.00717022 | Level : Second Floor | Second Floor | -0.102
220005 | Second Floor | 0 | 11 | 7.551 | 0.686455 | 8.975 | 0.0126509 | Level : Roof - Main | Roof - Main | 0
185652 | First Floor | 0 | 5 | 3.885 | 0.777 | 5.309 | 0.00717022 | Level : Second Floor | Second Floor | -0.102
185901 | First Floor | 0 | 12 | 8.346 | 0.6955 | 9.77 | 0.0138394 | Level : Second Floor | Second Floor | -0.102
186133 | First Floor | 0 | 5 | 3.885 | 0.777 | 5.309 | 0.00717022 | Level : Second Floor | Second Floor | -0.102
185723 | First Floor | 0 | 12 | 8.346 | 0.6955 | 9.77 | 0.0138394 | Level : Second Floor | Second Floor | -0.102
189591 | Second Floor | 0 | 5 | 3.885 | 0.777 | 5.309 | 0.00717022 | Level : Roof - Main | Roof - Main | 0
185569 | First Floor | 0 | 12 | 8.346 | 0.6955 | 9.77 | 0.0138394 | Level : Second Floor | Second Floor | -0.102
185757 | First Floor | 0 | 12 | 8.615 | 0.717917 | 10.039 | 0.0142416 | Level : Second Floor | Second Floor | -0.102
185932 | First Floor | 0 | 12 | 8.346 | 0.6955 | 9.77 | 0.0138394 | Level : Second Floor | Second Floor | -0.102
185895 | First Floor | 0 | 12 | 8.346 | 0.6955 | 9.77 | 0.0138394 | Level : Second Floor | Second Floor | -0.102
186152 | First Floor | 0 | 6 | 4.626 | 0.771 | 6.05 | 0.00827801 | Level : Second Floor | Second Floor | -0.102
185957 | First Floor | 0 | 12 | 8.345 | 0.695417 | 9.769 | 0.0138379 | Level : Second Floor | Second Floor | -0.102
186150 | First Floor | 0 | 6 | 4.626 | 0.771 | 6.05 | 0.00827801 | Level : Second Floor | Second Floor | -0.102
185588 | First Floor | 0 | 5 | 3.885 | 0.777 | 5.309 | 0.00717022 | Level : Second Floor | Second Floor | -0.102
185656 | First Floor | 0 | 5 | 3.885 | 0.777 | 5.309 | 0.00717022 | Level : Second Floor | Second Floor | -0.102
186082 | First Floor | 0 | 12 | 8.346 | 0.6955 | 9.77 | 0.0138394 | Level : Second Floor | Second Floor | -0.102
185605 | First Floor | 0 | 6 | 4.626 | 0.771 | 6.05 | 0.00827801 | Level : Second Floor | Second Floor | -0.102
186248 | First Floor | 0 | 7 | 5.205 | 0.743571 | 6.629 | 0.00914362 | Level : Second Floor | Second Floor | -0.102
185687 | First Floor | 0 | 10 | 7.146 | 0.7146 | 8.57 | 0.0120454 | Level : Second Floor | Second Floor | -0.102
186119 | First Floor | 0 | 12 | 8.346 | 0.6955 | 9.77 | 0.0138394 | Level : Second Floor | Second Floor | -0.102
185635 | First Floor | 0 | 12 | 8.346 | 0.6955 | 9.77 | 0.0138394 | Level : Second Floor | Second Floor | -0.102
185618 | First Floor | 0 | 6 | 4.626 | 0.771 | 6.05 | 0.00827801 | Level : Second Floor | Second Floor | -0.102
186063 | First Floor | 0 | 5 | 3.885 | 0.777 | 5.309 | 0.00717022 | Level : Second Floor | Second Floor | -0.102
185672 | First Floor | 0 | 10 | 7.146 | 0.7146 | 8.57 | 0.0120454 | Level : Second Floor | Second Floor | -0.102
185934 | First Floor | 0 | 12 | 8.346 | 0.6955 | 9.77 | 0.0138394 | Level : Second Floor | Second Floor | -0.102
185585 | First Floor | 0 | 5 | 3.885 | 0.777 | 5.309 | 0.00717022 | Level : Second Floor | Second Floor | -0.102
189307 | Second Floor | 0 | 5 | 3.885 | 0.777 | 5.309 | 0.00717022 | Level : Roof - Main | Roof - Main | 0
185688 | First Floor | 0 | 10 | 7.146 | 0.7146 | 8.57 | 0.0120454 | Level : Second Floor | Second Floor | -0.102
189703 | Second Floor | 9.79552e-31 | 12 | 8.345 | 0.695417 | 9.769 | 0.0138379 | Level : Roof - Main | Roof - Main | 0
185936 | First Floor | 0 | 12 | 8.346 | 0.6955 | 9.77 | 0.0138394 | Level : Second Floor | Second Floor | -0.102
186137 | First Floor | 0 | 5 | 3.885 | 0.777 | 5.309 | 0.00717022 | Level : Second Floor | Second Floor | -0.102
185829 | First Floor | 0 | 12 | 8.346 | 0.6955 | 9.77 | 0.0138394 | Level : Second Floor | Second Floor | -0.102
185724 | First Floor | 0 | 12 | 8.346 | 0.6955 | 9.77 | 0.0138394 | Level : Second Floor | Second Floor | -0.102
186249 | First Floor | 0 | 7 | 5.205 | 0.743571 | 6.629 | 0.00914362 | Level : Second Floor | Second Floor | -0.102
189589 | Second Floor | 0 | 5 | 3.885 | 0.777 | 5.309 | 0.00717022 | Level : Roof - Main | Roof - Main | 0
189377 | Second Floor | 0 | 7 | 5.205 | 0.743571 | 6.629 | 0.00914362 | Level : Roof - Main | Roof - Main | 0
185602 | First Floor | 0 | 6 | 4.626 | 0.771 | 6.05 | 0.00827801 | Level : Second Floor | Second Floor | -0.102
185654 | First Floor | 0 | 5 | 3.885 | 0.777 | 5.309 | 0.00717022 | Level : Second Floor | Second Floor | -0.102
188822 | First Floor | 1.97385e-30 | 10 | 7.146 | 0.7146 | 8.57 | 0.0120454 | Level : Second Floor | Second Floor | -0.102
185705 | First Floor | 0 | 10 | 7.146 | 0.7146 | 8.57 | 0.0120454 | Level : Second Floor | Second Floor | -0.102
186018 | First Floor | 0 | 12 | 8.346 | 0.6955 | 9.77 | 0.0138394 | Level : Second Floor | Second Floor | -0.102
186017 | First Floor | 0 | 12 | 8.346 | 0.6955 | 9.77 | 0.0138394 | Level : Second Floor | Second Floor | -0.102
185633 | First Floor | 0 | 12 | 8.346 | 0.6955 | 9.77 | 0.0138394 | Level : Second Floor | Second Floor | -0.102
185931 | First Floor | 0 | 12 | 8.346 | 0.6955 | 9.77 | 0.0138394 | Level : Second Floor | Second Floor | -0.102
186052 | First Floor | 0 | 5 | 3.885 | 0.777 | 5.309 | 0.00717022 | Level : Second Floor | Second Floor | -0.102
186067 | First Floor | 0 | 5 | 3.885 | 0.777 | 5.309 | 0.00717022 | Level : Second Floor | Second Floor | -0.102
185707 | First Floor | 0 | 10 | 7.146 | 0.7146 | 8.57 | 0.0120454 | Level : Second Floor | Second Floor | -0.102
185702 | First Floor | 0 | 10 | 7.146 | 0.7146 | 8.57 | 0.0120454 | Level : Second Floor | Second Floor | -0.102
220004 | Second Floor | 0 | 11 | 7.551 | 0.686455 | 8.975 | 0.0126509 | Level : Roof - Main | Roof - Main | 0
189603 | Second Floor | 0 | 5 | 3.885 | 0.777 | 5.309 | 0.00717022 | Level : Roof - Main | Roof - Main | 0
189592 | Second Floor | 0 | 5 | 3.885 | 0.777 | 5.309 | 0.00717022 | Level : Roof - Main | Roof - Main | 0
186015 | First Floor | 0 | 12 | 8.346 | 0.6955 | 9.77 | 0.0138394 | Level : Second Floor | Second Floor | -0.102
186247 | First Floor | 0 | 7 | 5.205 | 0.743571 | 6.629 | 0.00914362 | Level : Second Floor | Second Floor | -0.102
185604 | First Floor | 0 | 6 | 4.626 | 0.771 | 6.05 | 0.00827801 | Level : Second Floor | Second Floor | -0.102
189259 | First Floor | 0 | 6 | 4.626 | 0.771 | 6.05 | 0.00827801 | Level : Second Floor | Second Floor | -0.102
186246 | First Floor | 0 | 7 | 5.205 | 0.743571 | 6.629 | 0.00914362 | Level : Second Floor | Second Floor | -0.102
185573 | First Floor | 0 | 12 | 8.346 | 0.6955 | 9.77 | 0.0138394 | Level : Second Floor | Second Floor | -0.102
186065 | First Floor | 0 | 5 | 3.885 | 0.777 | 5.309 | 0.00717022 | Level : Second Floor | Second Floor | -0.102
185601 | First Floor | 0 | 6 | 4.626 | 0.771 | 6.05 | 0.00827801 | Level : Second Floor | Second Floor | -0.102
185586 | First Floor | 0 | 5 | 3.885 | 0.777 | 5.309 | 0.00717022 | Level : Second Floor | Second Floor | -0.102
186086 | First Floor | 0 | 12 | 8.346 | 0.6955 | 9.77 | 0.0138394 | Level : Second Floor | Second Floor | -0.102
186114 | First Floor | 0 | 12 | 8.346 | 0.6955 | 9.77 | 0.0138394 | Level : Second Floor | Second Floor | -0.102
185655 | First Floor | 0 | 5 | 3.885 | 0.777 | 5.309 | 0.00717022 | Level : Second Floor | Second Floor | -0.102
186020 | First Floor | 0 | 12 | 8.346 | 0.6955 | 9.77 | 0.0138394 | Level : Second Floor | Second Floor | -0.102
220003 | Second Floor | 0 | 11 | 7.551 | 0.686455 | 8.975 | 0.0126509 | Level : Roof - Main | Roof - Main | 0
186117 | First Floor | 0 | 12 | 8.346 | 0.6955 | 9.77 | 0.0138394 | Level : Second Floor | Second Floor | -0.102
185589 | First Floor | 0 | 5 | 3.885 | 0.777 | 5.309 | 0.00717022 | Level : Second Floor | Second Floor | -0.102
185689 | First Floor | 0 | 10 | 7.146 | 0.7146 | 8.57 | 0.0120454 | Level : Second Floor | Second Floor | -0.102
185634 | First Floor | 0 | 12 | 8.346 | 0.6955 | 9.77 | 0.0138394 | Level : Second Floor | Second Floor | -0.102
185828 | First Floor | 0 | 12 | 8.346 | 0.6955 | 9.77 | 0.0138394 | Level : Second Floor | Second Floor | -0.102
185900 | First Floor | 0 | 12 | 8.346 | 0.6955 | 9.77 | 0.0138394 | Level : Second Floor | Second Floor | -0.102
185898 | First Floor | 0 | 12 | 8.346 | 0.6955 | 9.77 | 0.0138394 | Level : Second Floor | Second Floor | -0.102
185587 | First Floor | 0 | 5 | 3.885 | 0.777 | 5.309 | 0.00717022 | Level : Second Floor | Second Floor | -0.102
185685 | First Floor | 0 | 10 | 7.146 | 0.7146 | 8.57 | 0.0120454 | Level : Second Floor | Second Floor | -0.102
186064 | First Floor | 0 | 5 | 3.885 | 0.777 | 5.309 | 0.00717022 | Level : Second Floor | Second Floor | -0.102
186035 | First Floor | 0 | 5 | 3.885 | 0.777 | 5.309 | 0.00717022 | Level : Second Floor | Second Floor | -0.102
189588 | Second Floor | 0 | 5 | 3.885 | 0.777 | 5.309 | 0.00717022 | Level : Roof - Main | Roof - Main | 0
185673 | First Floor | 0 | 10 | 7.146 | 0.7146 | 8.57 | 0.0120454 | Level : Second Floor | Second Floor | -0.102
185826 | First Floor | 0 | 12 | 8.346 | 0.6955 | 9.77 | 0.0138394 | Level : Second Floor | Second Floor | -0.102
186135 | First Floor | 0 | 5 | 3.885 | 0.777 | 5.309 | 0.00717022 | Level : Second Floor | Second Floor | -0.102
186036 | First Floor | 0 | 5 | 3.885 | 0.777 | 5.309 | 0.00717022 | Level : Second Floor | Second Floor | -0.102
185825 | First Floor | 0 | 12 | 8.346 | 0.6955 | 9.77 | 0.0138394 | Level : Second Floor | Second Floor | -0.102
185897 | First Floor | 0 | 12 | 8.346 | 0.6955 | 9.77 | 0.0138394 | Level : Second Floor | Second Floor | -0.102
185570 | First Floor | 0 | 12 | 8.346 | 0.6955 | 9.77 | 0.0138394 | Level : Second Floor | Second Floor | -0.102
185686 | First Floor | 0 | 10 | 7.146 | 0.7146 | 8.57 | 0.0120454 | Level : Second Floor | Second Floor | -0.102
189308 | Second Floor | 0 | 5 | 3.885 | 0.777 | 5.309 | 0.00717022 | Level : Roof - Main | Roof - Main | 0
186034 | First Floor | 0 | 5 | 3.885 | 0.777 | 5.309 | 0.00717022 | Level : Second Floor | Second Floor | -0.102
186084 | First Floor | 0 | 12 | 8.346 | 0.6955 | 9.77 | 0.0138394 | Level : Second Floor | Second Floor | -0.102
189378 | Second Floor | 0 | 7 | 5.205 | 0.743571 | 6.629 | 0.00914362 | Level : Roof - Main | Roof - Main | 0
186032 | First Floor | 0 | 5 | 3.885 | 0.777 | 5.309 | 0.00717022 | Level : Second Floor | Second Floor | -0.102
186083 | First Floor | 0 | 12 | 8.346 | 0.6955 | 9.77 | 0.0138394 | Level : Second Floor | Second Floor | -0.102
185571 | First Floor | 0 | 12 | 8.346 | 0.6955 | 9.77 | 0.0138394 | Level : Second Floor | Second Floor | -0.102
186048 | First Floor | 0 | 5 | 3.885 | 0.777 | 5.309 | 0.00717022 | Level : Second Floor | Second Floor | -0.102
186031 | First Floor | 0 | 5 | 3.885 | 0.777 | 5.309 | 0.00717022 | Level : Second Floor | Second Floor | -0.102
185896 | First Floor | 0 | 12 | 8.346 | 0.6955 | 9.77 | 0.0138394 | Level : Second Floor | Second Floor | -0.102
186085 | First Floor | 0 | 12 | 8.346 | 0.6955 | 9.77 | 0.0138394 | Level : Second Floor | Second Floor | -0.102
185590 | First Floor | 0 | 5 | 3.885 | 0.777 | 5.309 | 0.00717022 | Level : Second Floor | Second Floor | -0.102
186019 | First Floor | 0 | 12 | 8.346 | 0.6955 | 9.77 | 0.0138394 | Level : Second Floor | Second Floor | -0.102
185899 | First Floor | 0 | 12 | 8.346 | 0.6955 | 9.77 | 0.0138394 | Level : Second Floor | Second Floor | -0.102
186037 | First Floor | 0 | 5 | 3.885 | 0.777 | 5.309 | 0.00717022 | Level : Second Floor | Second Floor | -0.102
185827 | First Floor | 0 | 12 | 8.346 | 0.6955 | 9.77 | 0.0138394 | Level : Second Floor | Second Floor | -0.102
186033 | First Floor | 0 | 5 | 3.885 | 0.777 | 5.309 | 0.00717022 | Level : Second Floor | Second Floor | -0.102
186051 | First Floor | 0 | 5 | 3.885 | 0.777 | 5.309 | 0.00717022 | Level : Second Floor | Second Floor | -0.102
186049 | First Floor | 0 | 5 | 3.885 | 0.777 | 5.309 | 0.00717022 | Level : Second Floor | Second Floor | -0.102
186050 | First Floor | 0 | 5 | 3.885 | 0.777 | 5.309 | 0.00717022 | Level : Second Floor | Second Floor | -0.102

# IfcBeam: M_W-Wide Flange:W460X60:176883 (277)
Material: Metal - Steel - 345 MPa
PSet_Revit_Structural - Stick Symbol Location: 0
Pset_BeamCommon - Reference: M_W-Wide Flange:W460X60; IsExternal: no; LoadBearing: yes
PSet_Revit_Constraints - z-Direction Justification: 0; z-Direction Offset Value: 0 m; Lateral Justification: 0; Cross-Section Rotation: 0 deg
PSet_Revit_Phasing - Phase Created: New Construction
PSet_Revit_Analytical Model - Rigid Links: 0; Horizontal Projection: Default
PSet_Revit_Materials and Finishes - Beam Material: Metal - Steel - 345 MPa
PSet_Revit_Other - InstallationDate: InstallationDate; SerialNumber: SerialNumber; WarrantyStartDate: WarrantyStartDate; BarCode: BarCode; AssetIdentifier: AssetIdentifier; TagNumber: TagNumber
PSet_Revit_Structural Analysis - Start Release: 3; Start Fx: no; Start Fy: no; Start Fz: no; Start Mx: no; Start My: yes; Start Mz: yes; End Release: 1; End Fx: no; End Fy: no; End Fz: no; End Mx: yes; End My: yes; End Mz: yes; Analyze As: 1
PSet_Revit_Type_Identity Data - Manufacturer: Manufacturer; OmniClass Number: 23.25.30.11.14.14; OmniClass Title: Beams
PSet_Revit_Type_Dimensions - bf: 0.153 m; d: 0.455 m; k: 0.031 m; kr: 0.0177 m; tf: 0.0133 m; tw: 0.008 m
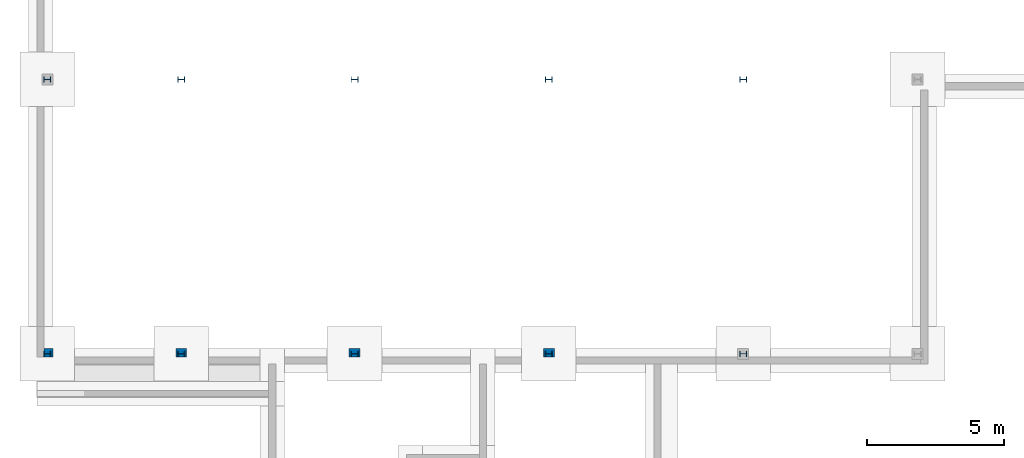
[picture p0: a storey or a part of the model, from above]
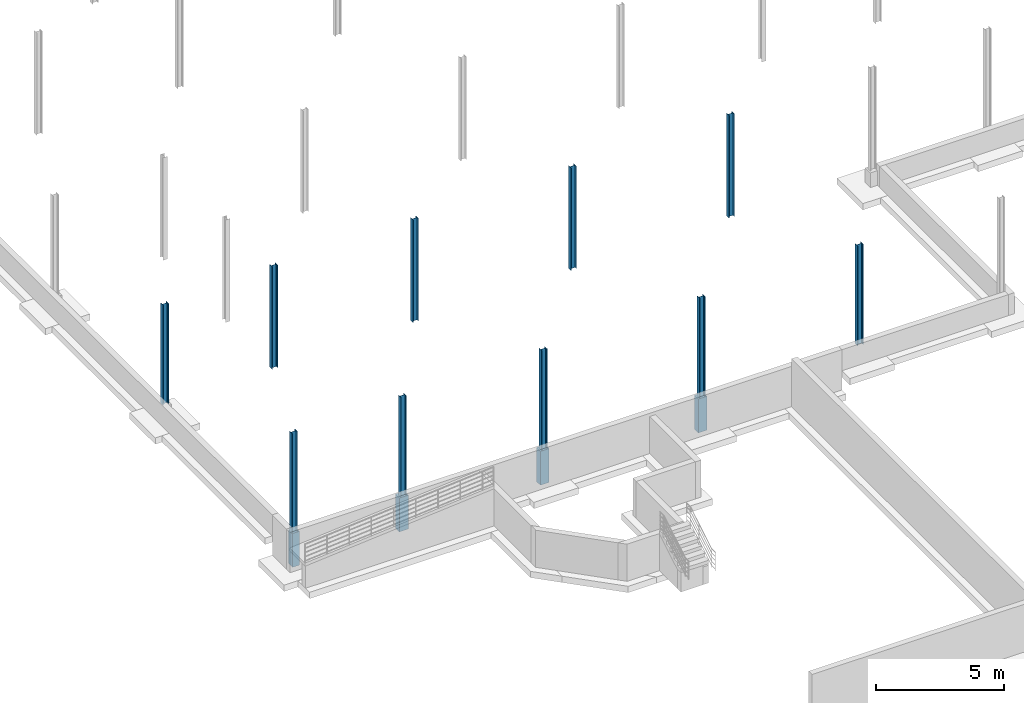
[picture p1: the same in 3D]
Properties of the parts of a building model (IFC2X3), part 2 of 3

# IfcBeam: M_W-Wide Flange:W460X60:176883 (277)
PSet_Revit_Type_Other - AccessibilityPerformance: AccessibilityPerformance; CodePerformance: CodePerformance; Color: Color; Constituents: Constituents; Features: Features; Finish: Finish; Grade: Grade; Material: Material; ModelReference: ModelReference; NominalHeight: NominalHeight; NominalLength: NominalLength; NominalWidth: NominalWidth; ProductionYear: ProductionYear; Reference: Reference; Shape: Shape; Size: Size; SustainabilityPerformance: SustainabilityPerformance; WarrantyDescription: WarrantyDescription; WarrantyDurationLabor: WarrantyDurationLabor; WarrantyDurationParts: WarrantyDurationParts; WarrantyGuarantorLabor: WarrantyGuarantorLabor; WarrantyGuarantorParts: WarrantyGuarantorParts; ExpectedLife: ExpectedLife; ReplacementCost: ReplacementCost; AssetAccountingType: FIXED; ModelLabel: ModelLabel
PSet_Revit_Type_Structural - W: 0.58; A: 0.00759 m2
Name (M_W-Wide Flange:W460X60:W460X60:...) | In | Cut Length (m) = Span (m) | Structural Usage | Start Attachment Type | Slope (deg) | Length (m) | Volume (m3) | Reference Level | Start Level Offset (m) | End Level Offset (m) | Start Extension Calculation (m) | End Extension Calculation (m) | Start Extension (m) | End Extension (m) | End Attachment Type
190021 | Second Floor | 7.1388 | 6 | 4 | 3.48996e-11 | 7.28 | 0.0535196 | Roof - Main | -0.0635 | -0.0635 | 3 | 3 | -0.0127 | -0.0127
189738 | Second Floor | 5.8461 | 6 |  | 0 | 6.05 | 0.0438282 | Roof - Main | 0 | 0 | 3 | 3 | -0.0127 | -0.0127 | 4
181131 | First Floor | 4.60169 | 3 | 4 | 0 | 4.88409 | 0.0344989 | Second Floor | -0.102 | -0.102 | 3 | 3 | -0.0127 | -0.0127 | 4
179075 | First Floor | 9.5406 | 3 | 4 | 0 | 9.77 | 0.0715259 | Second Floor | -0.102 | -0.102 | 3 | 3 | -0.0127 | -0.0127 | 4
179369 | First Floor | 4.6441 | 3 | 4 | 0 | 4.9 | 0.0348168 | Second Floor | -0.1655 | -0.1655 | 3 | 3 | -0.0127 | -0.0127 | 4
177809 | First Floor | 6.0576 | 3 | 4 | 0 | 6.34 | 0.0454138 | Second Floor | -0.1655 | -0.1655 | 3 | 3 | -0.0127 | -0.0127 | 4
178143 | First Floor | 8.3406 | 3 | 4 | 0 | 8.57 | 0.0625295 | Second Floor | -0.102 | -0.102 | 3 | 3 | -0.0127 | -0.0127 | 4
177817 | First Floor | 6.8276 | 3 | 4 | 0 | 7.11 | 0.0511865 | Second Floor | -0.1655 | -0.1655 | 3 | 3 | -0.0127 | -0.0127 | 4
179382 | First Floor | 6.0841 | 3 | 4 | 0 | 6.34 | 0.0456125 | Second Floor | -0.1655 | -0.1655 | 3 | 3 | -0.0127 | -0.0127 | 4
180695 | First Floor | 5.8206 | 3 | 4 | 0 | 6.05 | 0.043637 | Second Floor | -0.102 | -0.102 | 3 | 3 | -0.0127 | -0.0127 | 4
180050 | First Floor | 7.37057 | 3 | 4 | 0 | 7.59997 | 0.0552572 | Second Floor | -0.1655 | -0.1655 | 3 | 3 | -0.0127 | -0.0127 | 4
179684 | First Floor | 6.0841 | 3 | 4 | 0 | 6.34 | 0.0456125 | Second Floor | -0.1655 | -0.1655 | 3 | 3 | -0.0127 | -0.0127 | 4
179500 | First Floor | 5.204 | 3 | 4 | 0 | 5.4864 | 0.0390144 | Second Floor | -0.102 | -0.102 | 3 | 3 | -0.0127 | -0.0127 | 4
179671 | First Floor | 4.6441 | 3 | 4 | 0 | 4.9 | 0.0348168 | Second Floor | -0.1655 | -0.1655 | 3 | 3 | -0.0127 | -0.0127 | 4
177792 | First Floor | 9.8106 | 3 | 4 | 0 | 10.04 | 0.0735501 | Second Floor | -0.102 | -0.102 | 3 | 3 | -0.0127 | -0.0127 | 4
189060 | First Floor | 5.8461 | 6 |  | 0 | 6.05 | 0.0438282 | Second Floor | -0.102 | -0.102 | 3 | 3 | -0.0127 | -0.0127 | 4
178159 | First Floor | 7.31757 | 3 | 4 | 0 | 7.59997 | 0.0548599 | Second Floor | -0.1655 | -0.1655 | 3 | 3 | -0.0127 | -0.0127 | 4
190133 | Second Floor | 7.04591 | 6 | 4 | 0.499751 | 7.28028 | 0.0528232 | Roof - Main | -0.0635 | 0 | 3 | 3 | -0.0127 | -0.0127
180472 | First Floor | 5.0806 | 3 | 4 | 0 | 5.31 | 0.0380893 | Second Floor | -0.102 | -0.102 | 3 | 3 | -0.0127 | -0.0127 | 4
181182 | First Floor | 9.5141 | 3 | 4 | 0 | 9.77 | 0.0713272 | Second Floor | -0.102 | -0.102 | 3 | 3 | -0.0127 | -0.0127 | 4
186361 | First Floor | 8.3916 | 6 |  | 0 | 8.57 | 0.0629118 | Second Floor | -0.102 | -0.102 | 3 | 3 | -0.0127 | -0.0127
178810 | First Floor | 9.5141 | 3 | 4 | 0 | 9.77 | 0.0713272 | Second Floor | -0.102 | -0.102 | 3 | 3 | -0.0127 | -0.0127 | 4
178975 | First Floor | 5.8206 | 3 | 4 | 0 | 6.05 | 0.043637 | Second Floor | -0.102 | -0.102 | 3 | 3 | -0.0127 | -0.0127 | 4
180074 | First Floor | 6.1506 | 3 | 4 | 0 | 6.38 | 0.046111 | Second Floor | -0.1655 | -0.1655 | 3 | 3 | -0.0127 | -0.0127 | 4
178062 | First Floor | 4.6441 | 3 | 4 | 0 | 4.9 | 0.0348168 | Second Floor | -0.1655 | -0.1655 | 3 | 3 | -0.0127 | -0.0127 | 4
179698 | First Floor | 6.8276 | 3 | 4 | 0 | 7.11 | 0.0511865 | Second Floor | -0.1655 | -0.1655 | 3 | 3 | -0.0127 | -0.0127 | 4
179710 | First Floor | 6.8276 | 3 | 4 | 0 | 7.11 | 0.0511865 | Second Floor | -0.1655 | -0.1655 | 3 | 3 | -0.0127 | -0.0127 | 4
181365 | First Floor | 5.8206 | 3 | 4 | 0 | 6.05 | 0.043637 | Second Floor | -0.102 | -0.102 | 3 | 3 | -0.0127 | -0.0127 | 4
177952 | First Floor | 9.8106 | 3 | 4 | 0 | 10.04 | 0.0735501 | Second Floor | -0.102 | -0.102 | 3 | 3 | -0.0127 | -0.0127 | 4
179475 | First Floor | 6.9976 | 3 | 4 | 0 | 7.28 | 0.052461 | Second Floor | -0.1655 | -0.1655 | 3 | 3 | -0.0127 | -0.0127 | 4
177805 | First Floor | 4.6176 | 3 | 4 | 0 | 4.9 | 0.0346181 | Second Floor | -0.1655 | -0.1655 | 3 | 3 | -0.0127 | -0.0127 | 4
242096 | Second Floor | 0.975101 | 3 | 4 | 0 | 1.2 | 0.00731033 | Second Floor | 2.0715 | 2.0715 | 3 | 3 | -0.0127 | -0.0127 | 4
242236 | Second Floor | 1.0276 | 3 | 4 | 0 | 1.2 | 0.00770392 | Second Floor | 2.0715 | 2.0715 | 3 | 3 | -0.0127 | -0.0127 | 4
178999 | First Floor | 9.5406 | 3 | 4 | 0 | 9.77 | 0.0715259 | Second Floor | -0.102 | -0.102 | 3 | 3 | -0.0127 | -0.0127 | 4
187462 | First Floor | 3.19211 | 6 |  | 6.62648e-11 | 3.37208 | 0.0239312 | Second Floor | -0.102 | -0.102 | 3 | 3 | -0.0127 | -0.0127
225399 | First Floor | 7.1388 | 3 | 4 | 2.79111e-11 | 7.28 | 0.0535196 | Second Floor | -0.1655 | -0.1655 | 3 | 3 | -0.0127 | -0.0127
177919 | First Floor | 9.8106 | 3 | 4 | 0 | 10.04 | 0.0735501 | Second Floor | -0.102 | -0.102 | 3 | 3 | -0.0127 | -0.0127 | 4
177907 | First Floor | 6.8276 | 3 | 4 | 0 | 7.11 | 0.0511865 | Second Floor | -0.1655 | -0.1655 | 3 | 3 | -0.0127 | -0.0127 | 4
177778 | First Floor | 8.3406 | 3 | 4 | 0 | 8.57 | 0.0625295 | Second Floor | -0.102 | -0.102 | 3 | 3 | -0.0127 | -0.0127 | 4
180062 | First Floor | 4.95063 | 3 | 4 | 0 | 5.18003 | 0.0371148 | Second Floor | -0.1655 | -0.1655 | 3 | 3 | -0.0127 | -0.0127 | 4
180036 | First Floor | 7.0506 | 3 | 4 | 0 | 7.28 | 0.0528583 | Second Floor | -0.1655 | -0.1655 | 3 | 3 | -0.0127 | -0.0127 | 4
182190 | Second Floor | 4.60222 | 3 | 4 | 0 | 4.88462 | 0.0345028 | Roof - Main | -0.0635 | -0.0635 | 3 | 3 | -0.0127 | -0.0127 | 4
179528 | First Floor | 6.3476 | 3 | 4 | 0 | 6.63 | 0.047588 | Second Floor | -0.102 | -0.102 | 3 | 3 | -0.0127 | -0.0127 | 4
179487 | First Floor | 7.35646 | 3 | 4 | 0 | 7.61236 | 0.0551513 | Second Floor | -0.102 | -0.102 | 3 | 3 | -0.0127 | -0.0127 | 4
186639 | First Floor | 2.68 | 6 |  | 0 | 2.68 | 0.020092 | Second Floor | -0.102 | -0.102 | 3 | 3 | -0.0127 | -0.0127
242235 | Second Floor | 0.975101 | 3 | 4 | 0 | 1.2 | 0.00731033 | Second Floor | 2.0715 | 2.0715 | 3 | 3 | -0.0127 | -0.0127 | 4
180505 | First Floor | 9.5406 | 3 | 4 | 0 | 9.77 | 0.0715259 | Second Floor | -0.102 | -0.102 | 3 | 3 | -0.0127 | -0.0127 | 4
184107 | Second Floor | 6.8276 | 3 | 4 | 0 | 7.11 | 0.0511865 | Roof - Main | -0.0635 | -0.0635 | 3 | 3 | -0.0127 | -0.0127 | 4
187012 | First Floor | 6.4516 | 6 |  | 0 | 6.63 | 0.0483676 | Second Floor | -0.102 | -0.102 | 3 | 3 | -0.0127 | -0.0127
178516 | First Floor | 8.3406 | 3 | 4 | 0 | 8.57 | 0.0625295 | Second Floor | -0.102 | -0.102 | 3 | 3 | -0.0127 | -0.0127 | 4
184095 | Second Floor | 6.8276 | 3 | 4 | 0 | 7.11 | 0.0511865 | Roof - Main | -0.0635 | -0.0635 | 3 | 3 | -0.0127 | -0.0127 | 4
187002 | First Floor | 6.4516 | 6 |  | 0 | 6.63 | 0.0483676 | Second Floor | -0.102 | -0.102 | 3 | 3 | -0.0127 | -0.0127
241554 | Second Floor | 7.0506 | 3 | 4 | 0 | 7.25773 | 0.0528583 | Second Floor | 2.0715 | 2.0715 | 3 | 3 | -0.0127 | -0.0127 | 4
181016 | First Floor | 5.0806 | 3 | 4 | 0 | 5.31 | 0.0380893 | Second Floor | -0.102 | -0.102 | 3 | 3 | -0.0127 | -0.0127 | 4
242219 | Second Floor | 1.0276 | 3 | 4 | 0 | 1.2 | 0.00770392 | Second Floor | 2.0715 | 2.0715 | 3 | 3 | -0.0127 | -0.0127 | 4
180494 | First Floor | 6.4006 | 3 | 4 | 0 | 6.63 | 0.0479853 | Second Floor | -0.102 | -0.102 | 3 | 3 | -0.0127 | -0.0127 | 4
178988 | First Floor | 5.0806 | 3 | 4 | 0 | 5.31 | 0.0380893 | Second Floor | -0.102 | -0.102 | 3 | 3 | -0.0127 | -0.0127 | 4
178598 | First Floor | 10.613 | 3 | 4 | 0 | 10.8689 | 0.0795656 | Second Floor | -0.102 | -0.102 | 3 | 3 | -0.0127 | -0.0127 | 4
178016 | First Floor | 4.5932 | 3 | 4 | 0 | 4.8756 | 0.0344353 | Second Floor | -0.1655 | -0.1655 | 3 | 3 | -0.0127 | -0.0127 | 4
179461 | First Floor | 7.31757 | 3 | 4 | 0 | 7.59997 | 0.0548599 | Second Floor | -0.1655 | -0.1655 | 3 | 3 | -0.0127 | -0.0127 | 4
182177 | Second Floor | 4.60298 | 3 | 4 | 0 | 4.88538 | 0.0345085 | Roof - Main | 0 | 0 | 3 | 3 | -0.0127 | -0.0127 | 4
179953 | First Floor | 9.5141 | 6 | 4 | 0 | 9.77 | 0.0713272 | Second Floor | -0.102 | -0.102 | 3 | 3 | -0.0127 | -0.0127 | 4
177763 | First Floor | 9.5406 | 3 | 4 | 0 | 9.77 | 0.0715259 | Second Floor | -0.102 | -0.102 | 3 | 3 | -0.0127 | -0.0127 | 4
177272 | First Floor | 6.0576 | 3 | 4 | 0 | 6.34 | 0.0454138 | Second Floor | -0.1655 | -0.1655 | 3 | 3 | -0.0127 | -0.0127 | 4
186992 | First Floor | 6.4516 | 6 |  | 4.67901e-15 | 6.63 | 0.0483676 | Second Floor | -0.102 | -0.102 | 3 | 3 | -0.0127 | -0.0127
177965 | First Floor | 4.6176 | 3 | 4 | 0 | 4.9 | 0.0346181 | Second Floor | -0.1655 | -0.1655 | 3 | 3 | -0.0127 | -0.0127 | 4
183838 | Second Floor | 6.8276 | 3 | 4 | 0 | 7.11 | 0.0511865 | Roof - Main | -0.0635 | -0.0635 | 3 | 3 | -0.0127 | -0.0127 | 4
184082 | Second Floor | 6.1241 | 3 | 4 | 0 | 6.38 | 0.0459124 | Roof - Main | -0.0635 | -0.0635 | 3 | 3 | -0.0127 | -0.0127 | 4
187816 | First Floor | 11.075 | 6 |  | 2.80487e-15 | 11.075 | 0.0830293 | Second Floor | -0.102 | -0.102 | 3 | 3 | -0.0127 | -0.0127
181753 | Second Floor | 5.8206 | 3 | 4 | 0 | 6.05 | 0.043637 | Roof - Main | 0 | 0 | 3 | 3 | -0.0127 | -0.0127 | 4
180598 | First Floor | 6.8276 | 3 | 4 | 0 | 7.11 | 0.0511865 | Second Floor | -0.1655 | -0.1655 | 3 | 3 | -0.0127 | -0.0127 | 4
177747 | First Floor | 6.4006 | 3 | 4 | 0 | 6.63 | 0.0479853 | Second Floor | -0.102 | -0.102 | 3 | 3 | -0.0127 | -0.0127 | 4
186617 | First Floor | 2.3468 | 6 |  | 0 | 2.436 | 0.017594 | Second Floor | -0.102 | -0.102 | 3 | 3 | -0.0127 | -0.0127
178202 | First Floor | 4.89763 | 3 | 4 | 0 | 5.18003 | 0.0367175 | Second Floor | -0.1655 | -0.1655 | 3 | 3 | -0.0127 | -0.0127 | 4
179513 | First Floor | 1.69884 | 3 | 4 | 0 | 1.98124 | 0.0127362 | Second Floor | -0.102 | -0.102 | 3 | 3 | -0.0127 | -0.0127 | 4
180750 | First Floor | 5.0806 | 3 | 4 | 0 | 5.31 | 0.0380893 | Second Floor | -0.102 | -0.102 | 3 | 3 | -0.0127 | -0.0127 | 4
187763 | First Floor | 6.63 | 6 |  | 0 | 6.63 | 0.0497051 | Second Floor | -0.102 | -0.102 | 3 | 3 | -0.0127 | -0.0127
183849 | Second Floor | 6.0576 | 3 | 4 | 0 | 6.34 | 0.0454138 | Roof - Main | -0.0635 | -0.0635 | 3 | 3 | -0.0127 | -0.0127 | 4
180117 | First Floor | 6.0576 | 3 | 4 | 0 | 6.34 | 0.0454138 | Second Floor | -0.1655 | -0.1655 | 3 | 3 | -0.0127 | -0.0127 | 4
178824 | First Floor | 6.4006 | 3 | 4 | 0 | 6.63 | 0.0479853 | Second Floor | -0.102 | -0.102 | 3 | 3 | -0.0127 | -0.0127 | 4
178172 | First Floor | 5.49401 | 3 |  | 3.5661e-11 | 5.69791 | 0.0411886 | Second Floor | -0.1655 | -0.1655 | 3 | 3 | -0.0127 | -0.0127 | 4
186628 | First Floor | 2.92743 | 6 |  | 0 | 3.11508 | 0.0219469 | Second Floor | -0.102 | -0.102 | 3 | 3 | -0.0127 | -0.0127
179447 | First Floor | 4.89763 | 3 | 4 | 0 | 5.18003 | 0.0367175 | Second Floor | -0.1655 | -0.1655 | 3 | 3 | -0.0127 | -0.0127 | 4
177840 | First Floor | 6.0976 | 3 | 4 | 0 | 6.38 | 0.0457137 | Second Floor | -0.1655 | -0.1655 | 3 | 3 | -0.0127 | -0.0127 | 4
182149 | Second Floor | 4.60351 | 3 | 4 | 0 | 4.88591 | 0.0345125 | Roof - Main | 0 | 0 | 3 | 3 | -0.0127 | -0.0127 | 4
180483 | First Floor | 9.5406 | 3 | 4 | 0 | 9.77 | 0.0715259 | Second Floor | -0.102 | -0.102 | 3 | 3 | -0.0127 | -0.0127 | 4
187694 | First Floor | 6.4516 | 6 |  | 0 | 6.63 | 0.0483676 | Second Floor | -0.102 | -0.102 | 3 | 3 | -0.0127 | -0.0127
182215 | Second Floor | 6.0976 | 3 | 4 | 0 | 6.38 | 0.0457137 | Roof - Main | -0.0635 | -0.0635 | 3 | 3 | -0.0127 | -0.0127 | 4
180459 | First Floor | 5.8206 | 3 | 4 | 0 | 6.05 | 0.043637 | Second Floor | -0.102 | -0.102 | 3 | 3 | -0.0127 | -0.0127 | 4
178588 | First Floor | 6.9976 | 3 | 4 | 0 | 7.28 | 0.052461 | Second Floor | -0.1655 | -0.1655 | 3 | 3 | -0.0127 | -0.0127 | 4
178002 | First Floor | 3.4385 | 3 | 4 | 0 | 3.6944 | 0.0257784 | Second Floor | -0.102 | -0.102 | 3 | 3 | -0.0127 | -0.0127 | 4
182203 | Second Floor | 5.0541 | 3 | 4 | 0 | 5.31 | 0.0378906 | Roof - Main | 0 | 0 | 3 | 3 | -0.0127 | -0.0127 | 4
183098 | Second Floor | 7.31757 | 3 | 4 | 0 | 7.59997 | 0.0548599 | Roof - Main | -0.0635 | -0.0635 | 3 | 3 | -0.0127 | -0.0127 | 4
177874 | First Floor | 9.8106 | 3 | 4 | 0 | 10.04 | 0.0735501 | Second Floor | -0.102 | -0.102 | 3 | 3 | -0.0127 | -0.0127 | 4
187774 | First Floor | 6.63 | 6 |  | 0 | 6.63 | 0.0497051 | Second Floor | -0.102 | -0.102 | 3 | 3 | -0.0127 | -0.0127
179722 | First Floor | 6.0976 | 3 | 4 | 0 | 6.38 | 0.0457137 | Second Floor | -0.1655 | -0.1655 | 3 | 3 | -0.0127 | -0.0127 | 4
186606 | First Floor | 5.09083 | 6 |  | 3.92263e-11 | 5.18003 | 0.0381659 | Second Floor | -0.1655 | -0.1655 | 3 | 3 | -0.0127 | -0.0127
186981 | First Floor | 6.4516 | 6 |  | 0 | 6.63 | 0.0483676 | Second Floor | -0.102 | -0.102 | 3 | 3 | -0.0127 | -0.0127
178101 | First Floor | 6.8276 | 3 | 4 | 0 | 7.11 | 0.0511865 | Second Floor | -0.1655 | -0.1655 | 3 | 3 | -0.0127 | -0.0127 | 4
180933 | First Floor | 4.62872 | 3 | 4 | 0 | 4.88462 | 0.0347015 | Second Floor | -0.1655 | -0.1655 | 3 | 3 | -0.0127 | -0.0127 | 4
183127 | Second Floor | 6.9976 | 3 | 4 | 0 | 7.28 | 0.052461 | Roof - Main | -0.0635 | -0.0635 | 3 | 3 | -0.0127 | -0.0127 | 4
181029 | First Floor | 9.5141 | 3 | 4 | 0 | 9.77 | 0.0713272 | Second Floor | -0.102 | -0.102 | 3 | 3 | -0.0127 | -0.0127 | 4
225544 | First Floor | 7.04591 | 3 | 4 | 0.499751 | 7.28028 | 0.0528232 | Second Floor | -0.1655 | -0.102 | 3 | 3 | -0.0127 | -0.0127
183141 | Second Floor | 7.35646 | 3 | 4 | 0 | 7.61236 | 0.0551513 | Roof - Main | 0 | 0 | 3 | 3 | -0.0127 | -0.0127 | 4
187827 | First Floor | 11.065 | 6 |  | 0 | 11.065 | 0.0829543 | Second Floor | -0.102 | -0.102 | 3 | 3 | -0.0127 | -0.0127
179747 | First Floor | 7.31757 | 3 | 4 | 0 | 7.59997 | 0.0548599 | Second Floor | -0.1655 | -0.1655 | 3 | 3 | -0.0127 | -0.0127 | 4
181912 | Second Floor | 6.4006 | 3 | 4 | 0 | 6.63 | 0.0479853 | Roof - Main | 0 | 0 | 3 | 3 | -0.0127 | -0.0127 | 4
182109 | Second Floor | 6.0976 | 3 | 4 | 0 | 6.38 | 0.0457137 | Roof - Main | -0.0635 | -0.0635 | 3 | 3 | -0.0127 | -0.0127 | 4
216329 | Roof - Main | 6.94771 | 3 | 4 | 6.02366e-15 | 7.1 | 0.052087 | Roof - Main | 3.35607 | 3.35607 | 3.01512 | 3 | 0.00242402 | -0.0127 | 4
178850 | First Floor | 5.0276 | 3 | 4 | 0 | 5.31 | 0.0376919 | Second Floor | -0.102 | -0.102 | 3 | 3 | -0.0127 | -0.0127 | 4
180320 | First Floor | 6.8541 | 3 | 4 | 0 | 7.11 | 0.0513852 | Second Floor | -0.1655 | -0.1655 | 3 | 3 | -0.0127 | -0.0127 | 4
187022 | First Floor | 2.03121 | 6 |  | 4.7719e-11 | 2.40275 | 0.015228 | Second Floor | -0.102 | -0.102 | 3 | 3 | -0.0127 | -0.0127
186459 | First Floor | 8.3916 | 6 |  | 0 | 8.57 | 0.0629118 | Second Floor | -0.102 | -0.102 | 3 | 3 | -0.0127 | -0.0127
178216 | First Floor | 8.3141 | 3 | 4 | 0 | 8.57 | 0.0623308 | Second Floor | -0.102 | -0.102 | 3 | 3 | -0.0127 | -0.0127 | 4
182083 | Second Floor | 6.8276 | 3 | 4 | 8.72626e-15 | 7.11 | 0.0511865 | Roof - Main | -0.0635 | -0.0635 | 3 | 3 | -0.0127 | -0.0127 | 4
241862 | Second Floor | 1.35679 | 3 | 4 | 0 | 1.58692 | 0.0101719 | Second Floor | 2.0715 | 2.0715 | 3 | 3 | -0.0127 | -0.0127 | 4
179406 | First Floor | 4.5576 | 3 | 4 | 0 | 4.84 | 0.0341683 | Second Floor | -0.1655 | -0.1655 | 3 | 3 | -0.0127 | -0.0127 | 4
180090 | First Floor | 6.8541 | 3 | 4 | 0 | 7.11 | 0.0513852 | Second Floor | -0.1655 | -0.1655 | 3 | 3 | -0.0127 | -0.0127 | 4
179429 | First Floor | 6.0976 | 3 | 4 | 0 | 6.38 | 0.0457137 | Second Floor | -0.1655 | -0.1655 | 3 | 3 | -0.0127 | -0.0127 | 4
187045 | First Floor | 1.91049 | 6 |  | 0 | 2.40262 | 0.014323 | Second Floor | -0.102 | -0.102 | 3 | 3 | -0.0127 | -0.0127
180975 | First Floor | 5.0806 | 3 | 4 | 0 | 5.31 | 0.0380893 | Second Floor | -0.102 | -0.102 | 3 | 3 | -0.0127 | -0.0127 | 4
183712 | Second Floor | 6.8276 | 3 | 4 | 0 | 7.11 | 0.0511865 | Roof - Main | -0.0635 | -0.0635 | 3 | 3 | -0.0127 | -0.0127 | 4
187056 | First Floor | 2.03121 | 6 |  | 4.7719e-11 | 2.40275 | 0.015228 | Second Floor | -0.102 | -0.102 | 3 | 3 | -0.0127 | -0.0127
177193 | First Floor | 4.6176 | 3 | 4 | 0 | 4.9 | 0.0346181 | Second Floor | -0.1655 | -0.1655 | 3 | 3 | -0.0127 | -0.0127 | 4
181861 | Second Floor | 3.4385 | 3 | 4 | 0 | 3.6944 | 0.0257784 | Roof - Main | 0 | 0 | 3 | 3 | -0.0127 | -0.0127 | 4
179060 | First Floor | 6.4006 | 3 | 4 | 0 | 6.63 | 0.0479853 | Second Floor | -0.102 | -0.102 | 3 | 3 | -0.0127 | -0.0127 | 4
180520 | First Floor | 8.3406 | 3 | 4 | 0 | 8.57 | 0.0625295 | Second Floor | -0.102 | -0.102 | 3 | 3 | -0.0127 | -0.0127 | 4
218228 | Roof - Main | 4.61355 | 3 | 4 | 6.02366e-15 | 4.88 | 0.0345878 | Roof - Main | 3.35389 | 3.35389 | 3 | 3 | -0.0127 | -0.0127 | 4
180332 | First Floor | 6.8276 | 3 | 4 | 0 | 7.11 | 0.0511865 | Second Floor | -0.1655 | -0.1655 | 3 | 3 | -0.0127 | -0.0127 | 4
181798 | Second Floor | 5.0276 | 3 | 4 | 0 | 5.31 | 0.0376919 | Roof - Main | 0 | 0 | 3 | 3 | -0.0127 | -0.0127 | 4
177240 | First Floor | 4.6176 | 3 | 4 | 0 | 4.9 | 0.0346181 | Second Floor | -0.1655 | -0.1655 | 3 | 3 | -0.0127 | -0.0127 | 4
241450 | Second Floor | 7.04898 | 3 | 4 | 0.210621 | 7.19244 | 0.0528462 | Second Floor | 2.07781 | 2.10425 | 3 | 3 | -0.0127 | -0.0127 | 4
179545 | First Floor | 1.69878 | 3 | 4 | 0 | 1.97082 | 0.0127358 | Second Floor | -0.102 | -0.102 | 3 | 3 | -0.0127 | -0.0127 | 4
179735 | First Floor | 4.89763 | 3 | 4 | 0 | 5.18003 | 0.0367175 | Second Floor | -0.1655 | -0.1655 | 3 | 3 | -0.0127 | -0.0127 | 4
183934 | Second Floor | 6.8276 | 3 | 4 | 0 | 7.11 | 0.0511865 | Roof - Main | -0.0635 | -0.0635 | 3 | 3 | -0.0127 | -0.0127 | 4
182315 | Second Floor | 8.3406 | 3 | 4 | 0 | 8.57 | 0.0625295 | Roof - Main | 0 | 0 | 3 | 3 | -0.0127 | -0.0127 | 4
178474 | First Floor | 8.3406 | 3 | 4 | 0 | 8.57 | 0.0625295 | Second Floor | -0.102 | -0.102 | 3 | 3 | -0.0127 | -0.0127 | 4
177405 | First Floor | 1.6776 | 3 | 4 | 0 | 1.96 | 0.012577 | Second Floor | -0.1655 | -0.1655 | 3 | 3 | -0.0127 | -0.0127 | 4
184119 | Second Floor | 6.0841 | 3 | 4 | 0 | 6.34 | 0.0456125 | Roof - Main | -0.0635 | -0.0635 | 3 | 3 | -0.0127 | -0.0127 | 4
182785 | Second Floor | 5.0806 | 3 | 4 | 0 | 5.31 | 0.0380893 | Roof - Main | 0 | 0 | 3 | 3 | -0.0127 | -0.0127 | 4
177866 | First Floor | 6.0976 | 3 | 4 | 0 | 6.38 | 0.0457137 | Second Floor | -0.1655 | -0.1655 | 3 | 3 | -0.0127 | -0.0127 | 4
182771 | Second Floor | 4.89763 | 3 | 4 | 0 | 5.18003 | 0.0367175 | Roof - Main | -0.0635 | -0.0635 | 3 | 3 | -0.0127 | -0.0127 | 4
182280 | Second Floor | 9.5141 | 3 | 4 | 0 | 9.77 | 0.0713272 | Roof - Main | 0 | 0 | 3 | 3 | -0.0127 | -0.0127 | 4
216322 | Second Floor | 7.07609 | 3 |  | 5.80382e-12 | 7.27999 | 0.0530494 | Roof - Main | -1.3135 | -1.3135 | 3 | 3 | -0.0127 | -0.0127 | 4
179419 | First Floor | 6.8276 | 3 | 4 | 0 | 7.11 | 0.0511865 | Second Floor | -0.1655 | -0.1655 | 3 | 3 | -0.0127 | -0.0127 | 4
180920 | First Floor | 5.0806 | 3 | 4 | 0 | 5.31 | 0.0380893 | Second Floor | -0.102 | -0.102 | 3 | 3 | -0.0127 | -0.0127 | 4
177733 | First Floor | 9.5406 | 3 | 4 | 0 | 9.77 | 0.0715259 | Second Floor | -0.102 | -0.102 | 3 | 3 | -0.0127 | -0.0127 | 4
180342 | First Floor | 6.0576 | 3 | 4 | 0 | 6.34 | 0.0454138 | Second Floor | -0.1655 | -0.1655 | 3 | 3 | -0.0127 | -0.0127 | 4
183154 | Second Floor | 5.204 | 3 | 4 | 0 | 5.4864 | 0.0390144 | Roof - Main | 0 | 0 | 3 | 3 | -0.0127 | -0.0127 | 4
179937 | First Floor | 9.5141 | 3 | 4 | 0 | 9.77 | 0.0713272 | Second Floor | -0.102 | -0.102 | 3 | 3 | -0.0127 | -0.0127 | 4
218671 | Roof - Main | 6.94168 | 3 | 4 | 6.02366e-15 | 7.125 | 0.0520418 | Roof - Main | 3.35607 | 3.35607 | 3.00907 | 3 | -0.00363211 | -0.0127 | 4
179394 | First Floor | 1.9876 | 3 | 4 | 0 | 2.27 | 0.014901 | Second Floor | -0.1655 | -0.1655 | 3 | 3 | -0.0127 | -0.0127 | 4
177307 | First Floor | 1.9876 | 3 | 4 | 0 | 2.27 | 0.014901 | Second Floor | -0.1655 | -0.1655 | 3 | 3 | -0.0127 | -0.0127 | 4
187034 | First Floor | 1.91049 | 6 |  | 0 | 2.40262 | 0.014323 | Second Floor | -0.102 | -0.102 | 3 | 3 | -0.0127 | -0.0127
183764 | Second Floor | 7.31757 | 3 | 4 | 0 | 7.59997 | 0.0548599 | Roof - Main | -0.0635 | -0.0635 | 3 | 3 | -0.0127 | -0.0127 | 4
178236 | First Floor | 6.0976 | 3 | 4 | 0 | 6.38 | 0.0457137 | Second Floor | -0.1655 | -0.1655 | 3 | 3 | -0.0127 | -0.0127 | 4
182742 | Second Floor | 6.8276 | 3 | 4 | 0 | 7.11 | 0.0511865 | Roof - Main | -0.0635 | -0.0635 | 3 | 3 | -0.0127 | -0.0127 | 4
183738 | Second Floor | 6.1241 | 3 | 4 | 0 | 6.38 | 0.0459124 | Roof - Main | -0.0635 | -0.0635 | 3 | 3 | -0.0127 | -0.0127 | 4
187794 | First Floor | 6.21219 | 6 | 4 | 0 | 6.39009 | 0.0465728 | Second Floor | -0.102 | -0.102 | 3 | 3 | -0.0127 | -0.0127
183919 | Second Floor | 6.0576 | 3 | 4 | 0 | 6.34 | 0.0454138 | Roof - Main | -0.0635 | -0.0635 | 3 | 3 | -0.0127 | -0.0127 | 4
177687 | First Floor | 5.8206 | 3 | 4 | 0 | 6.05 | 0.043637 | Second Floor | -0.102 | -0.102 | 3 | 3 | -0.0127 | -0.0127 | 4
202098 | Second Floor | 7.74185 | 6 | 4 | 1.87325e-13 | 7.949 | 0.0580407 | Roof - Main | -1.80568 | -1.80568 | 3 | 3 | -0.0127 | -0.0127 | 4
178835 | First Floor | 9.5141 | 3 | 4 | 0 | 9.77 | 0.0713272 | Second Floor | -0.102 | -0.102 | 3 | 3 | -0.0127 | -0.0127 | 4
178117 | First Floor | 4.92413 | 3 | 4 | 0 | 5.18003 | 0.0369162 | Second Floor | -0.1655 | -0.1655 | 3 | 3 | -0.0127 | -0.0127 | 4
182136 | Second Floor | 4.60169 | 3 | 4 | 0 | 4.88409 | 0.0344989 | Roof - Main | 0 | 0 | 3 | 3 | -0.0127 | -0.0127 | 4
178284 | First Floor | 6.0576 | 3 | 4 | 0 | 6.34 | 0.0454138 | Second Floor | -0.1655 | -0.1655 | 3 | 3 | -0.0127 | -0.0127 | 4
180946 | First Floor | 4.60298 | 3 | 4 | 0 | 4.88538 | 0.0345085 | Second Floor | -0.102 | -0.102 | 3 | 3 | -0.0127 | -0.0127 | 4
184059 | Second Floor | 7.31757 | 3 | 4 | 0 | 7.59997 | 0.0548599 | Roof - Main | -0.0635 | -0.0635 | 3 | 3 | -0.0127 | -0.0127 | 4
181117 | First Floor | 4.60351 | 3 | 4 | 0 | 4.88591 | 0.0345125 | Second Floor | -0.1655 | -0.1655 | 3 | 3 | -0.0127 | -0.0127 | 4
216328 | Roof - Main | 7.7715 | 3 | 4 | 0 | 7.9489 | 0.0582629 | Roof - Main | 1.29537 | 1.29537 | 3 | 3 | -0.0127 | -0.0127 | 4
180988 | First Floor | 9.5141 | 3 | 4 | 0 | 9.77 | 0.0713272 | Second Floor | -0.102 | -0.102 | 3 | 3 | -0.0127 | -0.0127 | 4
183823 | Second Floor | 6.8541 | 3 | 4 | 0 | 7.11 | 0.0513852 | Roof - Main | -1.3135 | -1.3135 | 3 | 3 | -0.0127 | -0.0127 | 4
182003 | Second Floor | 9.5406 | 3 | 4 | 0 | 9.77 | 0.0715259 | Roof - Main | 0 | 0 | 3 | 3 | -0.0127 | -0.0127 | 4
178076 | First Floor | 6.0841 | 3 | 4 | 0 | 6.34 | 0.0456125 | Second Floor | -0.1655 | -0.1655 | 3 | 3 | -0.0127 | -0.0127 | 4
181992 | Second Floor | 6.4006 | 3 | 4 | 0 | 6.63 | 0.0479853 | Roof - Main | 0 | 0 | 3 | 3 | -0.0127 | -0.0127 | 4
183751 | Second Floor | 4.92413 | 3 | 4 | 0 | 5.18003 | 0.0369162 | Roof - Main | -0.0635 | -0.0635 | 3 | 3 | -0.0127 | -0.0127 | 4
183033 | Second Floor | 5.0806 | 3 | 4 | 1.16843e-14 | 5.31 | 0.0380893 | Roof - Main | 0 | 0 | 3 | 3 | -0.0127 | -0.0127 | 4
216318 | Second Floor | 8.6627 | 3 | 4 | 0 | 8.775 | 0.0649442 | Second Floor | 2.0715 | 2.0715 | 3 | 3 | -0.0127 | -0.0127 | 4
182031 | Second Floor | 6.8276 | 3 | 4 | 0 | 7.11 | 0.0511865 | Roof - Main | -0.0635 | -0.0635 | 3 | 3 | -0.0127 | -0.0127 | 4
177894 | First Floor | 9.8106 | 3 | 4 | 0 | 10.04 | 0.0735501 | Second Floor | -0.102 | -0.102 | 3 | 3 | -0.0127 | -0.0127 | 4
183726 | Second Floor | 6.8276 | 3 | 4 | 0 | 7.11 | 0.0511865 | Roof - Main | -0.0635 | -0.0635 | 3 | 3 | -0.0127 | -0.0127 | 4
177826 | First Floor | 6.8276 | 3 | 4 | 0 | 7.11 | 0.0511865 | Second Floor | -0.1655 | -0.1655 | 3 | 3 | -0.0127 | -0.0127 | 4
183226 | Second Floor | 10.613 | 3 | 4 | 0 | 10.8689 | 0.0795656 | Roof - Main | 0 | 0 | 3 | 3 | -0.0127 | -0.0127 | 4
216319 | Second Floor | 7.10159 | 3 |  | 1.13008e-11 | 7.27999 | 0.0532406 | Roof - Main | -1.3135 | -1.3135 | 3 | 3 | -0.0127 | -0.0127
183167 | Second Floor | 0.956345 | 3 | 4 | 0 | 1.18624 | 0.00716972 | Roof - Main | 0 | 0 | 3 | 3 | -0.0127 | -0.0127 | 4
180824 | First Floor | 9.5141 | 3 | 4 | 0 | 9.77 | 0.0713272 | Second Floor | -0.102 | -0.102 | 3 | 3 | -0.0127 | -0.0127 | 4
178863 | First Floor | 5.7941 | 3 | 4 | 0 | 6.05 | 0.0434384 | Second Floor | -0.102 | -0.102 | 3 | 3 | -0.0127 | -0.0127 | 4
216327 | Second Floor | 4.97613 | 3 |  | 0 | 5.18003 | 0.0373061 | Roof - Main | -1.3135 | -1.3135 | 3 | 3 | -0.0127 | -0.0127 | 4
178130 | First Floor | 7.31757 | 3 | 4 | 0 | 7.59997 | 0.0548599 | Second Floor | -0.1655 | -0.1655 | 3 | 3 | -0.0127 | -0.0127 | 4
181900 | Second Floor | 9.5406 | 3 | 4 | 0 | 9.77 | 0.0715259 | Roof - Main | 0 | 0 | 3 | 3 | -0.0127 | -0.0127 | 4
187784 | First Floor | 6.63 | 6 |  | 0 | 6.63 | 0.0497051 | Second Floor | -0.102 | -0.102 | 3 | 3 | -0.0127 | -0.0127
216923 | First Floor | 2.1071 | 6 | 4 | 0 | 2.28 | 0.0157969 | Second Floor | -0.102 | -0.102 | 3 | 3 | -0.0127 | -0.0127
218382 | Roof - Main | 6.94097 | 3 | 4 | 6.02366e-15 | 7.12 | 0.0520364 | Roof - Main | 3.35389 | 3.35389 | 3 | 3.00835 | -0.0127 | -0.00434686 | 4
177851 | First Floor | 9.8106 | 3 | 4 | 0 | 10.04 | 0.0735501 | Second Floor | -0.102 | -0.102 | 3 | 3 | -0.0127 | -0.0127 | 4
216324 | Second Floor | 1.2392 | 3 |  | 1.47723e-13 | 1.3 | 0.00929027 | Roof - Main | -1.3135 | -1.3135 | 3 | 2.9392 | -0.0127 | -0.0735016
186469 | First Floor | 5.257 | 6 |  | 0 | 5.257 | 0.0394117 | Second Floor | -0.1655 | -0.1655 | 3 | 3 | -0.0127 | -0.0127
180279 | First Floor | 7.37057 | 6 | 4 | 0 | 7.59997 | 0.0552572 | Second Floor | -0.1655 | -0.1655 | 3 | 3 | -0.0127 | -0.0127 | 4
178109 | First Floor | 6.1241 | 3 | 4 | 0 | 6.38 | 0.0459124 | Second Floor | -0.1655 | -0.1655 | 3 | 3 | -0.0127 | -0.0127 | 4
180352 | First Floor | 4.6176 | 3 | 4 | 0 | 4.9 | 0.0346181 | Second Floor | -0.1655 | -0.1655 | 3 | 3 | -0.0127 | -0.0127 | 4
182014 | Second Floor | 8.3406 | 3 | 4 | 0 | 8.57 | 0.0625295 | Roof - Main | 0 | 0 | 3 | 3 | -0.0127 | -0.0127 | 4
187805 | First Floor | 6.21219 | 6 | 4 | 0 | 6.39009 | 0.0465728 | Second Floor | -0.102 | -0.102 | 3 | 3 | -0.0127 | -0.0127
183811 | Second Floor | 6.1506 | 3 | 4 | 0 | 6.38 | 0.046111 | Roof - Main | -1.3135 | -1.3135 | 3 | 3 | -0.0127 | -0.0127 | 4
182267 | Second Floor | 5.0806 | 3 | 4 | 0 | 5.31 | 0.0380893 | Roof - Main | 0 | 0 | 3 | 3 | -0.0127 | -0.0127 | 4
181936 | Second Floor | 5.0806 | 3 | 4 | 0 | 5.31 | 0.0380893 | Roof - Main | 0 | 0 | 3 | 3 | -0.0127 | -0.0127 | 4
180103 | First Floor | 6.8276 | 3 | 4 | 0 | 7.11 | 0.0511865 | Second Floor | -0.1655 | -0.1655 | 3 | 3 | -0.0127 | -0.0127 | 4
183242 | Second Floor | 6.9976 | 3 | 4 | 0 | 7.28 | 0.052461 | Roof - Main | -0.0635 | -0.0635 | 3 | 3 | -0.0127 | -0.0127 | 4
182796 | Second Floor | 8.7716 | 3 | 4 | 9.16657e-12 | 8.975 | 0.0657607 | Roof - Main | 0 | 0 | 3 | 3 | -0.0127 | -0.0127 | 4
182123 | Second Floor | 8.3141 | 3 | 4 | 0 | 8.57 | 0.0623308 | Roof - Main | 0 | 0 | 3 | 3 | -0.0127 | -0.0127 | 4
183020 | Second Floor | 8.7716 | 3 | 4 | 9.16657e-12 | 8.975 | 0.0657607 | Roof - Main | 0 | 0 | 3 | 3 | -0.0127 | -0.0127 | 4
187440 | First Floor | 7.325 | 6 |  | 0 | 7.325 | 0.0549155 | Second Floor | -0.102 | -0.102 | 3 | 3 | -0.0127 | -0.0127
181981 | Second Floor | 9.5406 | 3 | 4 | 0 | 9.77 | 0.0715259 | Roof - Main | 0 | 0 | 3 | 3 | -0.0127 | -0.0127 | 4
216312 | Second Floor | 7.42207 | 3 |  | 0 | 7.59997 | 0.0556432 | Roof - Main | -1.3135 | -1.3135 | 3 | 3 | -0.0127 | -0.0127 | 4
181835 | Second Floor | 9.5141 | 3 | 4 | 0 | 9.77 | 0.0713272 | Roof - Main | 0 | 0 | 3 | 3 | -0.0127 | -0.0127 | 4
182835 | Second Floor | 8.3406 | 3 | 4 | 0 | 8.57 | 0.0625295 | Roof - Main | 0 | 0 | 3 | 3 | -0.0127 | -0.0127 | 4
180309 | First Floor | 6.1506 | 3 | 4 | 0 | 6.38 | 0.046111 | Second Floor | -0.1655 | -0.1655 | 3 | 3 | -0.0127 | -0.0127 | 4
184072 | Second Floor | 4.92413 | 3 | 4 | 0 | 5.18003 | 0.0369162 | Roof - Main | -0.0635 | -0.0635 | 3 | 3 | -0.0127 | -0.0127 | 4
207088 | Second Floor | 7.42207 | 3 |  | 0 | 7.59998 | 0.0556432 | Roof - Main | -1.3135 | -1.3135 | 3 | 3 | -0.0127 | -0.0127 | 4
180294 | First Floor | 4.95063 | 6 | 4 | 0 | 5.18003 | 0.0371148 | Second Floor | -0.1655 | -0.1655 | 3 | 3 | -0.0127 | -0.0127 | 4
181886 | Second Floor | 8.3406 | 3 | 4 | 7.23964e-15 | 8.57 | 0.0625295 | Roof - Main | 0 | 0 | 3 | 3 | -0.0127 | -0.0127 | 4
181786 | Second Floor | 6.0841 | 3 | 4 | 0 | 6.34 | 0.0456125 | Roof - Main | -0.0635 | -0.0635 | 3 | 3 | -0.0127 | -0.0127 | 4
181811 | Second Floor | 9.5141 | 3 | 4 | 0 | 9.77 | 0.0713272 | Roof - Main | 0 | 0 | 3 | 3 | -0.0127 | -0.0127 | 4
216308 | Second Floor | 7.74185 | 6 | 4 | 1.87325e-13 | 7.949 | 0.0580407 | Roof - Main | -1.80568 | -1.80568 | 3 | 3 | -0.0127 | -0.0127 | 4
182304 | Second Floor | 9.5141 | 3 | 4 | 0 | 9.77 | 0.0713272 | Roof - Main | 0 | 0 | 3 | 3 | -0.0127 | -0.0127 | 4
216321 | Second Floor | 0.8138 | 3 |  | 1.47723e-13 | 0.955 | 0.00610106 | Roof - Main | -1.3135 | -1.3135 | 3 | 3 | -0.0127 | -0.0127 | 4
216325 | Second Floor | 5.07862 | 3 |  | 3.31657e-11 | 5.18003 | 0.0380745 | Roof - Main | -0.0635 | -0.0635 | 3 | 3 | -0.0127 | -0.0127 | 4
183698 | Second Floor | 6.0841 | 3 | 4 | 0 | 6.34 | 0.0456125 | Roof - Main | -0.0635 | -0.0635 | 3 | 3 | -0.0127 | -0.0127 | 4
182992 | Second Floor | 8.7716 | 3 | 4 | 9.16657e-12 | 8.975 | 0.0657607 | Roof - Main | 0 | 0 | 3 | 3 | -0.0127 | -0.0127 | 4
181823 | Second Floor | 6.4006 | 3 | 4 | 0 | 6.63 | 0.0479853 | Roof - Main | 0 | 0 | 3 | 3 | -0.0127 | -0.0127 | 4
183211 | Second Floor | 5.20746 | 6 | 4 | 0 | 5.48 | 0.0390403 | Roof - Main | 0 | 0 | 3 | 3 | -0.0127 | -0.0127 | 4
177710 | First Floor | 5.0806 | 3 | 4 | 0 | 5.31 | 0.0380893 | Second Floor | -0.102 | -0.102 | 3 | 3 | -0.0127 | -0.0127 | 4
205745 | Second Floor | 7.42157 | 3 |  | 5.56928e-12 | 7.62 | 0.0556395 | Roof - Main | -1.3135 | -1.3135 | 3 | 3 | -0.0127 | -0.0127
201030 | First Floor | 2.1071 | 6 | 4 | 0 | 2.28 | 0.0157969 | Second Floor | -0.102 | -0.102 | 3 | 3 | -0.0127 | -0.0127
216295 | Second Floor | 0.956345 | 3 | 4 | 0 | 1.19611 | 0.00716972 | Roof - Main | 0 | 0 | 3 | 3 | -0.0127 | -0.0127 | 4
207856 | Second Floor | 7.42257 | 3 | 4 | 0 | 7.61216 | 0.055647 | Roof - Main | -0.0635 | -0.0635 | 3 | 3 | -0.0127 | -0.0127 | 4
177343 | First Floor | 2.5976 | 3 | 4 | 1.07715e-14 | 2.88 | 0.0194742 | Second Floor | -0.102 | -0.102 | 3 | 3 | -0.0127 | -0.0127 | 4
178093 | First Floor | 6.8276 | 3 | 4 | 0 | 7.11 | 0.0511865 | Second Floor | -0.1655 | -0.1655 | 3 | 3 | -0.0127 | -0.0127 | 4
181923 | Second Floor | 9.5406 | 3 | 4 | 0 | 9.77 | 0.0715259 | Roof - Main | 0 | 0 | 3 | 3 | -0.0127 | -0.0127 | 4
218867 | Roof - Main | 4.62969 | 3 | 4 | 6.02366e-15 | 4.86 | 0.0347088 | Roof - Main | 3.35607 | 3.35607 | 3.01613 | 3 | 0.00343289 | -0.0127 | 4
182910 | Second Floor | 4.89763 | 3 | 4 | 0 | 5.18003 | 0.0367175 | Roof - Main | -0.0635 | -0.0635 | 3 | 3 | -0.0127 | -0.0127 | 4
187451 | First Floor | 5.09083 | 6 |  | 3.92263e-11 | 5.18003 | 0.0381659 | Second Floor | -0.1655 | -0.1655 | 3 | 3 | -0.0127 | -0.0127
178308 | First Floor | 6.8276 | 3 | 4 | 0 | 7.11 | 0.0511865 | Second Floor | -0.1655 | -0.1655 | 3 | 3 | -0.0127 | -0.0127 | 4
216297 | Second Floor | 6.8541 | 3 | 4 | 0 | 7.11 | 0.0513852 | Roof - Main | -1.3135 | -1.3135 | 3 | 3 | -0.0127 | -0.0127 | 4
205846 | Second Floor | 6.3546 | 3 |  | 0 | 6.38 | 0.0476404 | Roof - Main | -0.0635 | -0.0635 | 3 | 3 | -0.0127 | -0.0127
180168 | First Floor | 4.6176 | 3 | 4 | 0 | 4.9 | 0.0346181 | Second Floor | -0.1655 | -0.1655 | 3 | 3 | -0.0127 | -0.0127 | 4
182979 | Second Floor | 8.3406 | 3 | 4 | 0 | 8.57 | 0.0625295 | Roof - Main | 0 | 0 | 3 | 3 | -0.0127 | -0.0127 | 4
211118 | Second Floor | 7.07609 | 3 |  | 0 | 7.28 | 0.0530494 | Roof - Main | -1.3135 | -1.3135 | 3 | 3 | -0.0127 | -0.0127 | 4
216326 | Second Floor | 6.9857 | 3 |  | 2.4197e-11 | 7.1 | 0.0523718 | Roof - Main | -0.0635 | -0.0635 | 2.9492 | 2.9492 | -0.0635 | -0.0635
181873 | Second Floor | 6.0576 | 3 | 4 | 9.78608e-15 | 6.34 | 0.0454138 | Roof - Main | -0.0635 | -0.0635 | 3 | 3 | -0.0127 | -0.0127 | 4
216316 | Second Floor | 1.3 | 3 |  | 1.47723e-13 | 1.3 | 0.0097461 | Roof - Main | -1.3135 | -1.3135 | 3 | 3 | -0.0127 | -0.0127
214899 | Roof - Main | 6.94557 | 3 | 4 | 6.02366e-15 | 7.18 | 0.0520709 | Roof - Main | 3.35389 | 3.35389 | 3.01298 | 3 | 0.000281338 | -0.0127 | 4
216296 | Second Floor | 6.1506 | 3 | 4 | 0 | 6.38 | 0.046111 | Roof - Main | -1.3135 | -1.3135 | 3 | 3 | -0.0127 | -0.0127 | 4
216310 | Second Floor | 7.42157 | 3 |  | 0 | 7.59997 | 0.0556395 | Roof - Main | -1.3135 | -1.3135 | 3 | 3 | -0.0127 | -0.0127
182822 | Second Floor | 8.7716 | 3 | 4 | 0 | 8.975 | 0.0657607 | Roof - Main | 0 | 0 | 3 | 3 | -0.0127 | -0.0127 | 4
181848 | Second Floor | 4.5932 | 3 | 4 | 0 | 4.8756 | 0.0344353 | Roof - Main | -0.0635 | -0.0635 | 3 | 3 | -0.0127 | -0.0127 | 4
181968 | Second Floor | 5.0806 | 3 | 4 | 0 | 5.31 | 0.0380893 | Roof - Main | 0 | 0 | 3 | 3 | -0.0127 | -0.0127 | 4
208138 | Second Floor | 7.10259 | 3 | 4 | 0 | 7.28 | 0.0532481 | Roof - Main | -0.0635 | -0.0635 | 3 | 3 | -0.0127 | -0.0127 | 4
216309 | Second Floor | 7.42258 | 6 | 4 | 0.000122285 | 7.59997 | 0.0556471 | Roof - Main | -0.253523 | -0.253539 | 3 | 3 | -0.0127 | -0.0127 | 4
180262 | First Floor | 7.0506 | 3 | 4 | 0 | 7.28 | 0.0528583 | Second Floor | -0.1655 | -0.1655 | 3 | 3 | -0.0127 | -0.0127 | 4
210563 | Second Floor | 0.8138 | 3 |  | 1.47723e-13 | 0.955 | 0.00610106 | Roof - Main | -1.3135 | -1.3135 | 3 | 3 | -0.0127 | -0.0127 | 4
216313 | Second Floor | 7.42257 | 3 | 4 | 0 | 7.61216 | 0.055647 | Roof - Main | -0.0635 | -0.0635 | 3 | 3 | -0.0127 | -0.0127 | 4
181773 | Second Floor | 1.9876 | 3 | 4 | 0 | 2.27 | 0.014901 | Roof - Main | -0.0635 | -0.0635 | 3 | 3 | -0.0127 | -0.0127 | 4
216311 | Second Floor | 6.3546 | 3 |  | 0 | 6.38 | 0.0476404 | Roof - Main | -0.0635 | -0.0635 | 3 | 3 | -0.0127 | -0.0127
211625 | Second Floor | 1.2392 | 3 |  | 1.47723e-13 | 1.3 | 0.00929027 | Roof - Main | -1.3135 | -1.3135 | 3 | 2.9392 | -0.0127 | -0.0735016
208732 | Second Floor | 1.35679 | 3 | 4 | 0 | 1.58692 | 0.0101719 | Second Floor | 2.0715 | 2.0715 | 3 | 3 | -0.0127 | -0.0127 | 4
183395 | Second Floor | 2.5976 | 3 | 4 | 0 | 2.88 | 0.0194742 | Roof - Main | -0.0635 | -0.0635 | 3 | 3 | -0.0127 | -0.0127 | 4
182965 | Second Floor | 7.31757 | 3 | 4 | 0 | 7.59997 | 0.0548599 | Roof - Main | -0.0635 | -0.0635 | 3 | 3 | -0.0127 | -0.0127 | 4
183487 | Second Floor | 4.5576 | 3 | 4 | 0 | 4.84 | 0.0341683 | Roof - Main | -0.0635 | -0.0635 | 3 | 3 | -0.0127 | -0.0127 | 4
202947 | Second Floor | 7.42258 | 6 | 4 | 0.000122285 | 7.59997 | 0.0556471 | Roof - Main | -0.253523 | -0.253539 | 3 | 3 | -0.0127 | -0.0127 | 4
212755 | First Floor | 5.20752 | 3 | 4 | 0 | 5.50029 | 0.0390408 | Second Floor | -0.102 | -0.102 | 3 | 3 | -0.0127 | -0.0127 | 4
216314 | Second Floor | 7.10259 | 3 | 4 | 0 | 7.28 | 0.0532481 | Roof - Main | -0.0635 | -0.0635 | 3 | 3 | -0.0127 | -0.0127 | 4
214391 | Roof - Main | 7.7715 | 3 | 4 | 0 | 7.9489 | 0.0582629 | Roof - Main | 1.29537 | 1.29537 | 3 | 3 | -0.0127 | -0.0127 | 4
209372 | Second Floor | 7.10159 | 3 |  | 1.13008e-11 | 7.27999 | 0.0532406 | Roof - Main | -1.3135 | -1.3135 | 3 | 3 | -0.0127 | -0.0127
213506 | Second Floor | 6.90701 | 3 |  | 2.4197e-11 | 7.1 | 0.0517819 | Roof - Main | -0.0635 | -0.0635 | 2.9492 | 2.9492 | -0.0635 | -0.0635 | 4
208533 | Second Floor | 1.3 | 3 |  | 1.47723e-13 | 1.3 | 0.0097461 | Roof - Main | -1.3135 | -1.3135 | 3 | 3 | -0.0127 | -0.0127
214217 | Second Floor | 4.97613 | 3 |  | 0 | 5.18003 | 0.0373061 | Roof - Main | -1.3135 | -1.3135 | 3 | 3 | -0.0127 | -0.0127 | 4
213000 | Second Floor | 5.07862 | 3 |  | 3.31657e-11 | 5.18003 | 0.0380745 | Roof - Main | -0.0635 | -0.0635 | 3 | 3 | -0.0127 | -0.0127 | 4
208761 | Second Floor | 8.69243 | 3 | 4 | 0 | 8.8 | 0.0651671 | Second Floor | 2.0715 | 2.0715 | 3 | 3 | -0.0127 | -0.0127 | 4

# IfcColumn: 400 x 400mm (36)
In: TOF Footing
Type - ElementType: 400 x 400mm; PredefinedType: COLUMN
Material: Concrete - Cast-in-Place Concrete
PSet_Revit_Constraints - Base Level: TOF Footing; Top Level: First Floor; Top Offset: -0.305 m; Column Style: 0; Moves With Grids: yes; Room Bounding: yes
PSet_Revit_Structural Analysis - Top Release: 1; Top Fx: no; Top Fy: no; Top Fz: no; Top Mx: yes; Top My: yes; Top Mz: yes; Bottom Release: 1; Bottom Fx: no; Bottom Fy: no; Bottom Fz: no; Bottom Mx: no; Bottom My: yes; Bottom Mz: yes; Analyze As: 1
PSet_Revit_Analytical Model - Rigid Links: no; Horizontal Projection: Default; Bottom Vertical Projection: Bottom Of Column
Pset_ColumnCommon - Reference: M_Concrete-Rectangular-Column:400 x 400mm; IsExternal: no; LoadBearing: yes; Slope: 0 deg
PSet_Revit_Materials and Finishes - Column Material: Concrete - Cast In Situ
PSet_Revit_Other - InstallationDate: InstallationDate; SerialNumber: SerialNumber; WarrantyStartDate: WarrantyStartDate; BarCode: BarCode; AssetIdentifier: AssetIdentifier; TagNumber: TagNumber
PSet_Revit_Phasing - Phase Created: New Construction
PSet_Revit_Structural - Rebar Cover - Top Face: Rebar Cover 1 <0.025>; Rebar Cover - Bottom Face: Rebar Cover 1 <0.025>; Rebar Cover - Other Faces: Rebar Cover 1 <0.025>
PSet_Revit_Type_Dimensions - b: 0.4 m; h: 0.4 m
PSet_Revit_Type_Identity Data - Manufacturer: Manufacturer; OmniClass Number: 23.25.30.11.14.11; OmniClass Title: Columns
PSet_Revit_Type_Other - AccessibilityPerformance: AccessibilityPerformance; CodePerformance: CodePerformance; Color: Color; Constituents: Constituents; Features: Features; Finish: Finish; Grade: Grade; Material: Material; ModelReference: ModelReference; NominalHeight: NominalHeight; NominalLength: NominalLength; NominalWidth: NominalWidth; ProductionYear: ProductionYear; Reference: Reference; Shape: Shape; Size: Size; SustainabilityPerformance: SustainabilityPerformance; WarrantyDescription: WarrantyDescription; WarrantyDurationLabor: WarrantyDurationLabor; WarrantyDurationParts: WarrantyDurationParts; WarrantyGuarantorLabor: WarrantyGuarantorLabor; WarrantyGuarantorParts: WarrantyGuarantorParts; ExpectedLife: ExpectedLife; ReplacementCost: ReplacementCost; AssetAccountingType: FIXED; ModelLabel: ModelLabel
Name (M_Concrete-Rectangular-Column:400 x 400mm:400 x 400mm:...) | Column Location Mark | Base Offset (m) | Volume (m3)
229647 | H-8 | 0 | 0.1112
229646 | H-9 | 0 | 0.1112
229668 | C.7-1 | 0 | 0.1112
229656 | G-3 | 0 | 0.1112
229655 | F-9 | 0 | 0.1112
229672 | B-2 | 0 | 0.1112
229650 | H-6.3 | 0 | 0.1112
229677 | A-6 | -0.915 | 0.203504
229653 | G-5 | 0 | 0.1112
229649 | H-6.7 | 0 | 0.1112
229660 | E.8-1 | 0 | 0.1112
229670 | .9-D.2 | 0 | 0.1112
229652 | H-5 | 0 | 0.1112
229669 | D-1 | 0 | 0.1112
229678 | A-7 | -0.915 | 0.203504
229673 | B-3 | 0 | 0.1112
229671 | B-1 | 0 | 0.1112
229667 | C.2-1 | 0 | 0.1112
229657 | G-4 | 0 | 0.1112
229666 | C-9 | 0 | 0.1112
229654 | G-9 | 0 | 0.1112
229681 | B-9 | 0 | 0.1112
229679 | A-8 | -0.915 | 0.203504
229680 | A-9 | -0.915 | 0.160768
229648 | H-7 | 0 | 0.1112
229658 | G-2 | 0 | 0.1112
229674 | B-4 | 0 | 0.1112
229661 | E.3-1 | 0 | 0.1112
229665 | D-9 | 0 | 0.1112
229675 | A-4 | 0 | 0.1112
229651 | H-6 | 0 | 0.1112
229662 | E-1 | 0 | 0.1112
229659 | G-1 | 0 | 0.1112
229676 | A-5 | 0 | 0.1112
229664 | E-9 | 0 | 0.1112
229663 | .9-D.8 | 0 | 0.1112

# IfcColumn: W150X22.5 (30)
Type - ElementType: W150X22.5; PredefinedType: COLUMN
Material: Metal - Steel - 345 MPa
Pset_ColumnCommon - Reference: M_W-Wide Flange-Column:W150X22.5; IsExternal: no; LoadBearing: yes
PSet_Revit_Structural Analysis - Top Release: 1; Top Fx: no; Top Fy: no; Top Fz: no; Top Mx: yes; Top My: yes; Top Mz: yes; Bottom Release: 1; Bottom Fx: no; Bottom Fy: no; Bottom Fz: no; Bottom Mx: no; Bottom My: yes; Bottom Mz: yes; Analyze As: 1
PSet_Revit_Analytical Model - Rigid Links: no; Horizontal Projection: Default
PSet_Revit_Constraints - Column Style: 0; Moves With Grids: yes
PSet_Revit_Phasing - Phase Created: New Construction
PSet_Revit_Other - InstallationDate: InstallationDate; SerialNumber: SerialNumber; WarrantyStartDate: WarrantyStartDate; BarCode: BarCode; AssetIdentifier: AssetIdentifier; TagNumber: TagNumber
PSet_Revit_Materials and Finishes - Column Material: Metal - Steel - 345 MPa
PSet_Revit_Type_Structural - W: 0.22; A: 0.00287 m2
PSet_Revit_Type_Identity Data - Manufacturer: Manufacturer; OmniClass Number: 23.25.30.11.14.11; OmniClass Title: Columns
PSet_Revit_Type_Other - AccessibilityPerformance: AccessibilityPerformance; CodePerformance: CodePerformance; Color: Color; Constituents: Constituents; Features: Features; Finish: Finish; Grade: Grade; Material: Material; ModelReference: ModelReference; NominalHeight: NominalHeight; NominalLength: NominalLength; NominalWidth: NominalWidth; ProductionYear: ProductionYear; Reference: Reference; Shape: Shape; Size: Size; SustainabilityPerformance: SustainabilityPerformance; WarrantyDescription: WarrantyDescription; WarrantyDurationLabor: WarrantyDurationLabor; WarrantyDurationParts: WarrantyDurationParts; WarrantyGuarantorLabor: WarrantyGuarantorLabor; WarrantyGuarantorParts: WarrantyGuarantorParts; ExpectedLife: ExpectedLife; ReplacementCost: ReplacementCost; AssetAccountingType: FIXED; ModelLabel: ModelLabel
PSet_Revit_Type_Dimensions - bf: 0.152 m; d: 0.152 m; k: 0.018 m; kr: 0.0114 m; tf: 0.0066 m; tw: 0.0058 m
Name (M_W-Wide Flange-Column:W150X22.5:W150X22.5:...) | In | Bottom Vertical Projection = Base Level | Column Location Mark | Base Offset (m) | Top Level | Top Offset (m) | Volume (m3) | Slope (deg)
217178 | Roof - Main | Roof - Main | C.9-7 | 0 | Roof - Main | 3.3561 | 0.00943547
208357 | Second Floor | Roof - Main | E.1-2 | -1.3135 | Roof - Main | 0 | 0.00369283 | 0
211624 | Second Floor | Roof - Main | E.1-3 | -1.3135 | Roof - Main | 0 | 0.00369283
199175 | Roof - Main | Roof - Main | E.1-5 | -0.0635 | Roof - Main | 3.3561 | 0.009614
241863 | First Floor | Second Floor | D-2(-1.560) | -0.102 | Second Floor | 2.0715 | 0.00611066
216303 | Roof - Main | Roof - Main | C.9-3(1.180) | -0.0635 | Roof - Main | 1.2954 | 0.00382047 | 0
198898 | Second Floor | Roof - Main | D.9-3 | -1.3135 | Roof - Main | -0.2535 | 0.00298013
198790 | Second Floor | Roof - Main | D.9-2 | -1.3135 | Roof - Main | -0.2535 | 0.00298013 | 0
159592 | TOF Footing | First Floor | .9-D.8 | -0.305 | Second Floor | 0 | 0.0137058 | 0
210562 | Second Floor | Roof - Main | E.1-1 | -1.3135 | Roof - Main | 0 | 0.00369283
198643 | First Floor | Second Floor | D.7-1 | -0.102 | Second Floor | 2.0715 | 0.00611066 | 0
216305 | Roof - Main | Roof - Main | C.9-4(-1.589) | -0.0635 | Roof - Main | 3.3561 | 0.009614 | 0
217263 | Roof - Main | Roof - Main | E.1-7 | -0.0635 | Roof - Main | 3.3561 | 0.009614
216299 | First Floor | Second Floor | D.3-1 | -0.102 | Second Floor | 2.0715 | 0.00611066 | 0
197968 | Second Floor | Second Floor | D.7-1(-0.921) | 2.0715 | Roof - Main | -1.8057 | 0.00225702 | 0
199219 | Roof - Main | Roof - Main | E.1-6 | -0.0635 | Roof - Main | 3.3561 | 0.009614
199097 | Roof - Main | Roof - Main | E.1-4(-1.589) | -0.0635 | Roof - Main | 3.3561 | 0.009614 | 0
216300 | First Floor | Second Floor | D.3-2(-1.560) | -0.102 | Roof - Main | -1.9892 | 0.00785179 | 0
198943 | Roof - Main | Roof - Main | E.1-3(1.180) | -0.0635 | Roof - Main | 1.2954 | 0.00382047 | 0
216320 | Second Floor | Roof - Main | C.9-1 | -1.3135 | Roof - Main | 0 | 0.00369283
241653 | First Floor | Second Floor | D.9(0.205)-2(-1.560) | -0.102 | Second Floor | 2.0715 | 0.00611066
216323 | Second Floor | Roof - Main | C.9-3 | -1.3135 | Roof - Main | 0 | 0.00369283
216307 | Roof - Main | Roof - Main | C.9-6 | 0 | Roof - Main | 3.3561 | 0.00943547
198729 | First Floor | Second Floor | D.7-2(-1.560) | -0.102 | Roof - Main | -1.9892 | 0.00785179 | 0
216298 | Second Floor | Second Floor | D.3-1(-0.921) | 2.0715 | Roof - Main | -1.8057 | 0.00225702 | 0
216315 | Second Floor | Roof - Main | C.9-2 | -1.3135 | Roof - Main | 0 | 0.00369283 | 0
161965 | TOF Footing | First Floor | .9-D.2 | -0.305 | Second Floor | 0 | 0.0137058
216301 | Second Floor | Roof - Main | D.1-2 | -1.3135 | Roof - Main | -0.2535 | 0.00298013 | 0
216306 | Roof - Main | Roof - Main | C.9-5 | 0 | Roof - Main | 3.3561 | 0.00943547 | 0
216302 | Second Floor | Roof - Main | D.1-3 | -1.3135 | Roof - Main | -0.2535 | 0.00298013

# IfcColumn: W250X67 (129)
Type - ElementType: W250X67; PredefinedType: COLUMN
Material: Metal - Steel - 345 MPa
PSet_Revit_Materials and Finishes - Column Material: Metal - Steel - 345 MPa
Pset_ColumnCommon - Reference: M_W-Wide Flange-Column:W250X67; IsExternal: no; LoadBearing: yes
PSet_Revit_Other - InstallationDate: InstallationDate; SerialNumber: SerialNumber; WarrantyStartDate: WarrantyStartDate; BarCode: BarCode; AssetIdentifier: AssetIdentifier; TagNumber: TagNumber
PSet_Revit_Constraints - Column Style: 0; Moves With Grids: yes
PSet_Revit_Analytical Model - Rigid Links: no; Horizontal Projection: Default
PSet_Revit_Phasing - Phase Created: New Construction
PSet_Revit_Structural Analysis - Top Release: 1; Top Fx: no; Top Fy: no; Top Fz: no; Top Mx: yes; Top My: yes; Top Mz: yes; Bottom Release: 1; Bottom Fx: no; Bottom Fy: no; Bottom Fz: no; Bottom Mx: no; Bottom My: yes; Bottom Mz: yes; Analyze As: 1
PSet_Revit_Type_Identity Data - Manufacturer: Manufacturer; OmniClass Number: 23.25.30.11.14.11; OmniClass Title: Columns
PSet_Revit_Type_Dimensions - bf: 0.204 m; d: 0.257 m; k: 0.033 m; kr: 0.0173 m; tf: 0.0157 m; tw: 0.0089 m
PSet_Revit_Type_Structural - W: 0.66; A: 0.00856 m2
PSet_Revit_Type_Other - AccessibilityPerformance: AccessibilityPerformance; CodePerformance: CodePerformance; Color: Color; Constituents: Constituents; Features: Features; Finish: Finish; Grade: Grade; Material: Material; ModelReference: ModelReference; NominalHeight: NominalHeight; NominalLength: NominalLength; NominalWidth: NominalWidth; ProductionYear: ProductionYear; Reference: Reference; Shape: Shape; Size: Size; SustainabilityPerformance: SustainabilityPerformance; WarrantyDescription: WarrantyDescription; WarrantyDurationLabor: WarrantyDurationLabor; WarrantyDurationParts: WarrantyDurationParts; WarrantyGuarantorLabor: WarrantyGuarantorLabor; WarrantyGuarantorParts: WarrantyGuarantorParts; ExpectedLife: ExpectedLife; ReplacementCost: ReplacementCost; AssetAccountingType: FIXED; ModelLabel: ModelLabel
Name (M_W-Wide Flange-Column:W250X67:W250X67:...) | In | Volume (m3) | Column Location Mark | Base Level | Base Offset (m) | Top Level | Top Offset (m) | Bottom Vertical Projection
241102 | TOF Footing | 0.0410155 | D-3 | First Floor | -0.305 | Second Floor | 0 | First Floor
216503 | Second Floor | 0.0393749 | C.7-1 | Second Floor | 0 | Roof - Main | 0
216289 | Second Floor | 0.0283238 | D-1 | Second Floor | 0 | Roof - Main | -1.3135 | Pset_ColumnCommon - Slope: 0 deg
167608 | Second Floor | 0.0283238 | E-1 | Second Floor | 0 | Roof - Main | -1.3135 | Pset_ColumnCommon - Slope: 0 deg
169962 | Second Floor | 0.0393749 | F-5 | Second Floor | 0 | Roof - Main | 0
166957 | Second Floor | 0.0393749 | G-2 | Second Floor | 0 | Roof - Main | 0
159810 | TOF Footing | 0.0410155 | E-3 | First Floor | -0.305 | Second Floor | 0 | First Floor
169605 | Second Floor | 0.0393749 | F-7 | Second Floor | 0 | Roof - Main | 0
216293 | Second Floor | 0.0393749 | D-5 | Second Floor | 0 | Roof - Main | 0
171014 | Second Floor | 0.0244957 | E-3 | Second Floor | 0 | Roof - Main | -1.7685
171109 | Second Floor | 0.0393749 | E.5-4 | Second Floor | 0 | Roof - Main | 0
166872 | Second Floor | 0.0393749 | G-3 | Second Floor | 0 | Roof - Main | 0
159455 | TOF Footing | 0.0410155 | E-1 | First Floor | -0.305 | Second Floor | 0 | First Floor
159352 | TOF Footing | 0.0410155 | E.3-1 | First Floor | -0.305 | Second Floor | 0 | First Floor
171631 | Second Floor | 0.0393749 | D-7 | Second Floor | 0 | Roof - Main | 0
242340 | Second Floor | 0.0393749 | E-7 | Second Floor | 0 | Roof - Main | 0
167051 | Second Floor | 0.0393749 | G-1 | Second Floor | 0 | Roof - Main | 0
171242 | Second Floor | 0.0393749 | E-4 | Second Floor | 0 | Roof - Main | 0
167367 | Second Floor | 0.0393749 | E.3-1 | Second Floor | 0 | Roof - Main | 0
216290 | Second Floor | 0.0244957 | D-2 | Second Floor | 0 | Roof - Main | -1.7685 | Pset_ColumnCommon - Slope: 0 deg
166095 | Second Floor | 0.0393749 | G-7 | Second Floor | 0 | Roof - Main | 0
166386 | Second Floor | 0.0393749 | H-6.7 | Second Floor | 0 | Roof - Main | 0
171428 | Second Floor | 0.0393749 | E-6 | Second Floor | 0 | Roof - Main | 0
158920 | TOF Footing | 0.0410155 | F-2 | First Floor | -0.305 | Second Floor | 0 | First Floor
162066 | TOF Footing | 0.0410155 | B-1 | First Floor | -0.305 | Second Floor | 0 | First Floor
158795 | TOF Footing | 0.0410155 | F-3 | First Floor | -0.305 | Second Floor | 0 | First Floor
159643 | TOF Footing | 0.0410155 | E-2 | First Floor | -0.305 | Second Floor | 0 | First Floor
170269 | Second Floor | 0.0393749 | F-3 | Second Floor | 0 | Roof - Main | 0
157918 | TOF Footing | 0.0410155 | G-6 | First Floor | -0.305 | Second Floor | 0 | First Floor
157847 | TOF Footing | 0.0410155 | G-5 | First Floor | -0.305 | Second Floor | 0 | First Floor
169789 | Second Floor | 0.0393749 | F-6 | Second Floor | 0 | Roof - Main | 0
216291 | Second Floor | 0.0244957 | D-3 | Second Floor | 0 | Roof - Main | -1.7685
169135 | Second Floor | 0.0393749 | B.4-8 | Second Floor | 0 | Roof - Main | 0
160813 | TOF Footing | 0.0410155 | C-8 | First Floor | -0.305 | Second Floor | 0 | First Floor
163272 | TOF Footing | 0.0410155 | B-8 | First Floor | -0.305 | Second Floor | 0 | First Floor
169491 | Second Floor | 0.0393749 | F-8 | Second Floor | 0 | Roof - Main | 0
170124 | Second Floor | 0.0393749 | F-4 | Second Floor | 0 | Roof - Main | 0
161120 | TOF Footing | 0.0410155 | C-6 | First Floor | -0.305 | Second Floor | 0 | First Floor
162227 | TOF Footing | 0.0410155 | B-2 | First Floor | -0.305 | Second Floor | 0 | First Floor
173159 | Second Floor | 0.0393749 | C-7 | Second Floor | 0 | Roof - Main | 0
160006 | TOF Footing | 0.0410155 | E.5-4 | First Floor | -0.305 | Second Floor | 0 | First Floor
160958 | TOF Footing | 0.0400059 | C-9 | First Floor | -0.305 | Second Floor | -0.12 | First Floor
161177 | TOF Footing | 0.0410155 | C-5 | First Floor | -0.305 | Second Floor | 0 | First Floor
166226 | Second Floor | 0.0393749 | G-6.7 | Second Floor | 0 | Roof - Main | 0
167152 | Second Floor | 0.0393749 | E.8-1 | Second Floor | 0 | Roof - Main | 0
160075 | TOF Footing | 0.0410155 | E-5 | First Floor | -0.305 | Second Floor | 0 | First Floor
161606 | TOF Footing | 0.0410155 | C-2 | First Floor | -0.305 | Second Floor | 0 | First Floor
170461 | Second Floor | 0.0244957 | E-2 | Second Floor | 0 | Roof - Main | -1.7685 | Pset_ColumnCommon - Slope: 0 deg
159201 | TOF Footing | 0.0410155 | E.8-1 | First Floor | -0.305 | Second Floor | 0 | First Floor
170357 | Second Floor | 0.0393749 | F-2 | Second Floor | 0 | Roof - Main | 0
158077 | TOF Footing | 0.0410155 | G-8 | First Floor | -0.305 | Second Floor | 0 | First Floor
157534 | TOF Footing | 0.0400059 | H-7 | First Floor | -0.305 | Second Floor | -0.12 | First Floor
168906 | Second Floor | 0.0393749 | B-7 | Second Floor | 0 | Roof - Main | 0
169377 | Second Floor | 0.0393749 | E-8 | Second Floor | 0 | Roof - Main | 0
161246 | TOF Footing | 0.0410155 | C-4 | First Floor | -0.305 | Second Floor | 0 | First Floor
158023 | TOF Footing | 0.0410155 | G-6.7 | First Floor | -0.305 | Second Floor | 0 | First Floor
157587 | TOF Footing | 0.0410155 | H-6.7 | First Floor | -0.305 | Second Floor | 0 | First Floor | Pset_ColumnCommon - Slope: 0 deg
158054 | TOF Footing | 0.0410155 | G-7 | First Floor | -0.305 | Second Floor | 0 | First Floor
163027 | TOF Footing | 0.0400059 | B-9 | First Floor | -0.305 | Second Floor | -0.12 | First Floor
158232 | TOF Footing | 0.0400059 | G-9 | First Floor | -0.305 | Second Floor | -0.12 | First Floor
168605 | Second Floor | 0.0393749 | B-4 | Second Floor | 0 | Roof - Main | 0
171331 | Second Floor | 0.0393749 | E-5 | Second Floor | 0 | Roof - Main | 0
159009 | TOF Footing | 0.0410155 | G-2 | First Floor | -0.305 | Second Floor | 0 | First Floor
161926 | TOF Footing | 0.0410155 | D-1 | First Floor | -0.305 | Second Floor | 0 | First Floor
173046 | Second Floor | 0.0393749 | C-6 | Second Floor | 0 | Roof - Main | 0
159865 | TOF Footing | 0.0410155 | E-4 | First Floor | -0.305 | Second Floor | 0 | First Floor
157109 | TOF Footing | 0.0400059 | H-9 | First Floor | -0.305 | Second Floor | -0.12 | First Floor | Pset_ColumnCommon - Slope: 0 deg
158877 | TOF Footing | 0.0410155 | G-4 | First Floor | -0.305 | Second Floor | 0 | First Floor
157415 | TOF Footing | 0.0400059 | H-8 | First Floor | -0.305 | Second Floor | -0.12 | First Floor
159066 | TOF Footing | 0.0410155 | G-1 | First Floor | -0.305 | Second Floor | 0 | First Floor
172622 | Second Floor | 0.0393749 | C-4 | Second Floor | 0 | Roof - Main | 0
216292 | Second Floor | 0.0393749 | D-4 | Second Floor | 0 | Roof - Main | 0 | Pset_ColumnCommon - Slope: 0 deg
168813 | Second Floor | 0.0393749 | B-6 | Second Floor | 0 | Roof - Main | 0
166660 | Second Floor | 0.0393749 | G-5 | Second Floor | 0 | Roof - Main | 0
172365 | Second Floor | 0.0393749 | C.5-4 | Second Floor | 0 | Roof - Main | 0
160298 | TOF Footing | 0.0410155 | E-8 | First Floor | -0.305 | Second Floor | 0 | First Floor
168487 | Second Floor | 0.0393749 | B-3 | Second Floor | 0 | Roof - Main | 0
161758 | TOF Footing | 0.0410155 | C.2-1 | First Floor | -0.305 | Second Floor | 0 | First Floor
168391 | Second Floor | 0.0393749 | B-2 | Second Floor | 0 | Roof - Main | 0
165983 | Second Floor | 0.0393749 | G-8 | Second Floor | 0 | Roof - Main | 0 | Pset_ColumnCommon - Slope: 0 deg
157738 | TOF Footing | 0.0400059 | H-5 | First Floor | -0.305 | Second Floor | -0.12 | First Floor
162781 | TOF Footing | 0.0400059 | A-7 | First Floor | -0.305 | Second Floor | -0.12 | First Floor
162822 | TOF Footing | 0.0400059 | A-8 | First Floor | -0.305 | Second Floor | -0.12 | First Floor
160152 | TOF Footing | 0.0410155 | E-6 | First Floor | -0.305 | Second Floor | 0 | First Floor
166554 | Second Floor | 0.0393749 | G-6 | Second Floor | 0 | Roof - Main | 0
169298 | Second Floor | 0.0393749 | D-8 | Second Floor | 0 | Roof - Main | 0
158631 | TOF Footing | 0.0410155 | F-5 | First Floor | -0.305 | Second Floor | 0 | First Floor
172855 | Second Floor | 0.0393749 | C-5 | Second Floor | 0 | Roof - Main | 0
163400 | TOF Footing | 0.0410155 | B-6 | First Floor | -0.305 | Second Floor | 0 | First Floor
161861 | TOF Footing | 0.0410155 | C.7-1 | First Floor | -0.305 | Second Floor | 0 | First Floor
157707 | TOF Footing | 0.0400059 | H-6 | First Floor | -0.305 | Second Floor | -0.12 | First Floor
161683 | TOF Footing | 0.0410155 | D-2 | First Floor | -0.305 | Second Floor | 0 | First Floor
160576 | TOF Footing | 0.0410155 | D-7 | First Floor | -0.305 | Second Floor | 0 | First Floor
161057 | TOF Footing | 0.0410155 | C-7 | First Floor | -0.305 | Second Floor | 0 | First Floor
171946 | Second Floor | 0.0393749 | D-6 | Second Floor | 0 | Roof - Main | 0
161553 | TOF Footing | 0.0410155 | C-3 | First Floor | -0.305 | Second Floor | 0 | First Floor
163329 | TOF Footing | 0.0410155 | B-7 | First Floor | -0.305 | Second Floor | 0 | First Floor
162306 | TOF Footing | 0.0410155 | B-3 | First Floor | -0.305 | Second Floor | 0 | First Floor
161465 | TOF Footing | 0.0410155 | C.5-4 | First Floor | -0.305 | Second Floor | 0 | First Floor
168091 | Second Floor | 0.0393749 | B-1 | Second Floor | 0 | Roof - Main | 0
158572 | TOF Footing | 0.0410155 | F-6 | First Floor | -0.305 | Second Floor | 0 | First Floor
158329 | TOF Footing | 0.0400059 | F-9 | First Floor | -0.305 | Second Floor | -0.12 | First Floor
168724 | Second Floor | 0.0393749 | B-5 | Second Floor | 0 | Roof - Main | 0
169068 | Second Floor | 0.0393749 | B-8 | Second Floor | 0 | Roof - Main | 0
166780 | Second Floor | 0.0393749 | G-4 | Second Floor | 0 | Roof - Main | 0
162861 | TOF Footing | 0.0400059 | A-9 | First Floor | -0.305 | Second Floor | -0.12 | First Floor
166499 | Second Floor | 0.0393749 | H-6.3 | Second Floor | 0 | Roof - Main | 0
162343 | TOF Footing | 0.0410155 | B-4 | First Floor | -0.305 | Second Floor | 0 | First Floor
157646 | TOF Footing | 0.0410155 | H-6.3 | First Floor | -0.305 | Second Floor | 0 | First Floor
158826 | TOF Footing | 0.0410155 | G-3 | First Floor | -0.305 | Second Floor | 0 | First Floor
163453 | TOF Footing | 0.0410155 | B-5 | First Floor | -0.305 | Second Floor | 0 | First Floor
160369 | TOF Footing | 0.0400059 | E-9 | First Floor | -0.305 | Second Floor | -0.12 | First Floor
161510 | TOF Footing | 0.0410155 | D-4 | First Floor | -0.305 | Second Floor | 0 | First Floor
163524 | TOF Footing | 0.0410155 | B.4-8 | First Floor | -0.305 | Second Floor | 0 | First Floor
162708 | TOF Footing | 0.0400059 | A-6 | First Floor | -0.305 | Second Floor | -0.12 | First Floor
160213 | TOF Footing | 0.0410155 | E-7 | First Floor | -0.305 | Second Floor | 0 | First Floor
158696 | TOF Footing | 0.0410155 | F-4 | First Floor | -0.305 | Second Floor | 0 | First Floor
172756 | Second Floor | 0.0393749 | C-2 | Second Floor | 0 | Roof - Main | 0
160541 | TOF Footing | 0.0410155 | D-8 | First Floor | -0.305 | Second Floor | 0 | First Floor
169229 | Second Floor | 0.0393749 | C-8 | Second Floor | 0 | Roof - Main | 0
167932 | Second Floor | 0.0393749 | C.2-1 | Second Floor | 0 | Roof - Main | 0
160623 | TOF Footing | 0.0410155 | D-6 | First Floor | -0.305 | Second Floor | 0 | First Floor
158491 | TOF Footing | 0.0410155 | F-7 | First Floor | -0.305 | Second Floor | 0 | First Floor
162673 | TOF Footing | 0.0400059 | A-5 | First Floor | -0.305 | Second Floor | -0.12 | First Floor
160700 | TOF Footing | 0.0410155 | D-5 | First Floor | -0.305 | Second Floor | 0 | First Floor
160446 | TOF Footing | 0.0400059 | D-9 | First Floor | -0.305 | Second Floor | -0.12 | First Floor
172691 | Second Floor | 0.0393749 | C-3 | Second Floor | 0 | Roof - Main | 0
162396 | TOF Footing | 0.0400059 | A-4 | First Floor | -0.305 | Second Floor | -0.12 | First Floor
158408 | TOF Footing | 0.0410155 | F-8 | First Floor | -0.305 | Second Floor | 0 | First Floor

# IfcFooting: M_Footing-Rectangular:1000 x 1000 x 300mm (3)
PSet_Revit_Other - InstallationDate: InstallationDate; SerialNumber: SerialNumber; WarrantyStartDate: WarrantyStartDate; BarCode: BarCode; AssetIdentifier: AssetIdentifier; TagNumber: TagNumber
PSet_Revit_Structural - Rebar Cover - Top Face: Rebar Cover 1 <0.025>; Rebar Cover - Bottom Face: Rebar Cover 1 <0.025>; Rebar Cover - Other Faces: Rebar Cover 1 <0.025>
PSet_Revit_Constraints - Moves With Grids: yes
PSet_Revit_Phasing - Phase Created: New Construction
PSet_Revit_Structural Analysis - Analyze As: 4
PSet_Revit_Materials and Finishes - Footing Material: Concrete - Cast In Situ
PSet_Revit_Type_Identity Data - Manufacturer: Manufacturer; OmniClass Number: 23.25.05.17; OmniClass Title: Shallow Foundations
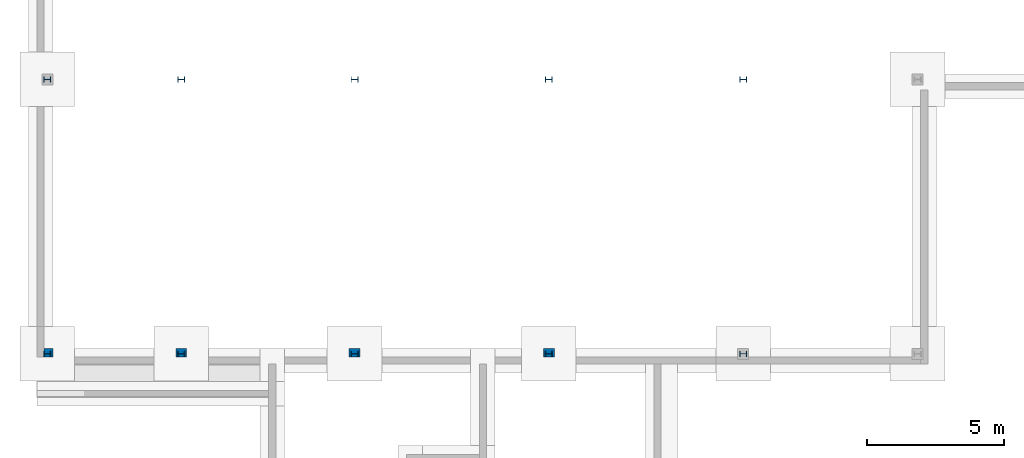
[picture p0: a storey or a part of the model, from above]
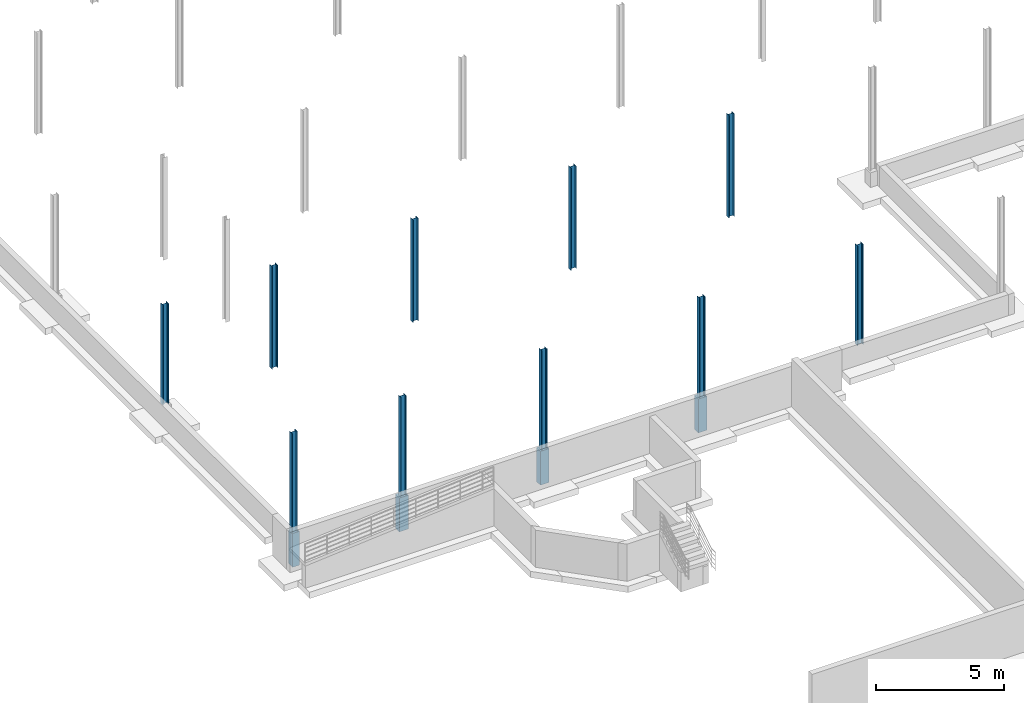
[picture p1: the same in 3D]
Properties of the parts of a building model (IFC2X3), part 3 of 3

# IfcFooting: M_Footing-Rectangular:1000 x 1000 x 300mm (3)
PSet_Revit_Type_Other - AccessibilityPerformance: AccessibilityPerformance; CodePerformance: CodePerformance; Color: Color; Constituents: Constituents; Features: Features; Finish: Finish; Grade: Grade; Material: Material; ModelReference: ModelReference; NominalHeight: NominalHeight; NominalLength: NominalLength; NominalWidth: NominalWidth; ProductionYear: ProductionYear; Reference: Reference; Shape: Shape; Size: Size; SustainabilityPerformance: SustainabilityPerformance; WarrantyDescription: WarrantyDescription; WarrantyDurationLabor: WarrantyDurationLabor; WarrantyDurationParts: WarrantyDurationParts; WarrantyGuarantorLabor: WarrantyGuarantorLabor; WarrantyGuarantorParts: WarrantyGuarantorParts; ExpectedLife: ExpectedLife; ReplacementCost: ReplacementCost; AssetAccountingType: FIXED; ModelLabel: ModelLabel
PSet_Revit_Type_Dimensions - Width: 1 m; Length: 1 m; Thickness: 0.3 m
Name (M_Footing-Rectangular:1000 x 1000 x 300mm:1000 x 1000 x 300mm:...) | In | Level | Host | Offset (m) | Elevation at Bottom (m)
152215 | TOF Footing | TOF Footing | Level : TOF Footing | 0 | -1.3
152284 | TOF Footing | TOF Footing | Level : TOF Footing | 0 | -1.3
149671 | First Floor | First Floor | Level : First Floor | -0.305 | -0.605

# IfcFooting: M_Footing-Rectangular:2000 x 2000 x 300mm (71)
PSet_Revit_Structural Analysis - Analyze As: 4
PSet_Revit_Phasing - Phase Created: New Construction
PSet_Revit_Other - InstallationDate: InstallationDate; SerialNumber: SerialNumber; WarrantyStartDate: WarrantyStartDate; BarCode: BarCode; AssetIdentifier: AssetIdentifier; TagNumber: TagNumber
PSet_Revit_Structural - Rebar Cover - Top Face: Rebar Cover 1 <0.025>; Rebar Cover - Bottom Face: Rebar Cover 1 <0.025>; Rebar Cover - Other Faces: Rebar Cover 1 <0.025>
PSet_Revit_Constraints - Moves With Grids: yes
PSet_Revit_Materials and Finishes - Footing Material: Concrete - Cast In Situ
PSet_Revit_Type_Identity Data - Manufacturer: Manufacturer; OmniClass Number: 23.25.05.17; OmniClass Title: Shallow Foundations
PSet_Revit_Type_Dimensions - Width: 2 m; Length: 2 m; Thickness: 0.3 m
PSet_Revit_Type_Other - AccessibilityPerformance: AccessibilityPerformance; CodePerformance: CodePerformance; Color: Color; Constituents: Constituents; Features: Features; Finish: Finish; Grade: Grade; Material: Material; ModelReference: ModelReference; NominalHeight: NominalHeight; NominalLength: NominalLength; NominalWidth: NominalWidth; ProductionYear: ProductionYear; Reference: Reference; Shape: Shape; Size: Size; SustainabilityPerformance: SustainabilityPerformance; WarrantyDescription: WarrantyDescription; WarrantyDurationLabor: WarrantyDurationLabor; WarrantyDurationParts: WarrantyDurationParts; WarrantyGuarantorLabor: WarrantyGuarantorLabor; WarrantyGuarantorParts: WarrantyGuarantorParts; ExpectedLife: ExpectedLife; ReplacementCost: ReplacementCost; AssetAccountingType: FIXED; ModelLabel: ModelLabel
Name (M_Footing-Rectangular:2000 x 2000 x 300mm:2000 x 2000 x 300mm:...) | In | Elevation at Bottom (m) | Level | Host | Offset (m)
230608 | TOF Footing | -1.3 | TOF Footing | Level : TOF Footing | 0
230230 | TOF Footing | -1.3 | TOF Footing | Level : TOF Footing | 0
230628 | TOF Footing | -1.3 | TOF Footing | Level : TOF Footing | 0
230218 | TOF Footing | -1.3 | TOF Footing | Level : TOF Footing | 0
230558 | TOF Footing | -1.3 | TOF Footing | Level : TOF Footing | 0
230618 | TOF Footing | -1.3 | TOF Footing | Level : TOF Footing | 0
230210 | TOF Footing | -1.3 | TOF Footing | Level : TOF Footing | 0
230052 | TOF Footing | -2.215 | TOF Footing | Level : TOF Footing | -0.915
230307 | TOF Footing | -1.3 | TOF Footing | Level : TOF Footing | 0
230654 | TOF Footing | -1.3 | TOF Footing | Level : TOF Footing | 0
230299 | TOF Footing | -1.3 | TOF Footing | Level : TOF Footing | 0
147881 | First Floor | -0.605 | First Floor | Level : First Floor | -0.305
230140 | TOF Footing | -1.3 | TOF Footing | Level : TOF Footing | 0
229877 | TOF Footing | -2.215 | TOF Footing | Level : TOF Footing | -0.915
230636 | TOF Footing | -1.3 | TOF Footing | Level : TOF Footing | 0
147722 | First Floor | -0.605 | First Floor | Level : First Floor | -0.305
230325 | TOF Footing | -1.3 | TOF Footing | Level : TOF Footing | 0
230281 | TOF Footing | -1.3 | TOF Footing | Level : TOF Footing | 0
147594 | First Floor | -0.605 | First Floor | Level : First Floor | -0.305
230289 | TOF Footing | -1.3 | TOF Footing | Level : TOF Footing | 0
230526 | TOF Footing | -1.3 | TOF Footing | Level : TOF Footing | 0
230566 | TOF Footing | -1.3 | TOF Footing | Level : TOF Footing | 0
230271 | TOF Footing | -1.3 | TOF Footing | Level : TOF Footing | 0
230644 | TOF Footing | -1.3 | TOF Footing | Level : TOF Footing | 0
147954 | First Floor | -0.605 | First Floor | Level : First Floor | -0.305
230406 | TOF Footing | -1.3 | TOF Footing | Level : TOF Footing | 0
230032 | TOF Footing | -2.215 | TOF Footing | Level : TOF Footing | -0.915
147643 | First Floor | -0.605 | First Floor | Level : First Floor | -0.305
230317 | TOF Footing | -1.3 | TOF Footing | Level : TOF Footing | 0
230074 | TOF Footing | -1.3 | TOF Footing | Level : TOF Footing | 0
230414 | TOF Footing | -1.3 | TOF Footing | Level : TOF Footing | 0
148121 | First Floor | -0.605 | First Floor | Level : First Floor | -0.305
149702 | First Floor | -0.605 | First Floor | Level : First Floor | -0.305
230542 | TOF Footing | -1.3 | TOF Footing | Level : TOF Footing | 0
230398 | TOF Footing | -1.3 | TOF Footing | Level : TOF Footing | 0
230550 | TOF Footing | -1.3 | TOF Footing | Level : TOF Footing | 0
230040 | TOF Footing | -2.215 | TOF Footing | Level : TOF Footing | -0.915
230426 | TOF Footing | -1.3 | TOF Footing | Level : TOF Footing | 0
230066 | TOF Footing | -1.3 | TOF Footing | Level : TOF Footing | 0
148068 | First Floor | -0.605 | First Floor | Level : First Floor | -0.305
149974 | First Floor | -0.605 | First Floor | Level : First Floor | -0.305
149193 | First Floor | -0.605 | First Floor | Level : First Floor | -0.305
149324 | First Floor | -0.605 | First Floor | Level : First Floor | -0.305
150113 | First Floor | -0.605 | First Floor | Level : First Floor | -0.305
150233 | First Floor | -0.605 | First Floor | Level : First Floor | -0.305
230534 | TOF Footing | -1.3 | TOF Footing | Level : TOF Footing | 0
148172 | First Floor | -0.605 | First Floor | Level : First Floor | -0.305
150166 | First Floor | -0.605 | First Floor | Level : First Floor | -0.305
148429 | First Floor | -0.605 | First Floor | Level : First Floor | -0.305
230476 | TOF Footing | -1.3 | TOF Footing | Level : TOF Footing | 0
148802 | First Floor | -0.605 | First Floor | Level : First Floor | -0.305
148017 | First Floor | -0.605 | First Floor | Level : First Floor | -0.305
149795 | First Floor | -0.605 | First Floor | Level : First Floor | -0.305
150350 | First Floor | -0.605 | First Floor | Level : First Floor | -0.305
149136 | First Floor | -0.605 | First Floor | Level : First Floor | -0.305
148337 | First Floor | -0.605 | First Floor | Level : First Floor | -0.305
148890 | First Floor | -0.605 | First Floor | Level : First Floor | -0.305
149544 | First Floor | -0.605 | First Floor | Level : First Floor | -0.305
149447 | First Floor | -0.605 | First Floor | Level : First Floor | -0.305
149515 | First Floor | -0.605 | First Floor | Level : First Floor | -0.305
149097 | First Floor | -0.605 | First Floor | Level : First Floor | -0.305
148382 | First Floor | -0.605 | First Floor | Level : First Floor | -0.305
148849 | First Floor | -0.605 | First Floor | Level : First Floor | -0.305
149482 | First Floor | -0.605 | First Floor | Level : First Floor | -0.305
148521 | First Floor | -0.605 | First Floor | Level : First Floor | -0.305
150387 | First Floor | -0.605 | First Floor | Level : First Floor | -0.305
149001 | First Floor | -0.605 | First Floor | Level : First Floor | -0.305
148460 | First Floor | -0.605 | First Floor | Level : First Floor | -0.305
149060 | First Floor | -0.605 | First Floor | Level : First Floor | -0.305
148761 | First Floor | -0.605 | First Floor | Level : First Floor | -0.305
148722 | First Floor | -0.605 | First Floor | Level : First Floor | -0.305

# IfcFooting: Wall Foundation:Bearing Footing - 900 x 300 (20)
In: TOF Footing
PredefinedType: STRIP_FOOTING
PSet_Revit_Other - InstallationDate: InstallationDate; SerialNumber: SerialNumber; WarrantyStartDate: WarrantyStartDate; BarCode: BarCode; AssetIdentifier: AssetIdentifier; TagNumber: TagNumber
PSet_Revit_Structural - Rebar Cover - Top Face: Rebar Cover 1 <0.025>; Rebar Cover - Bottom Face: Rebar Cover 1 <0.025>; Rebar Cover - Other Faces: Rebar Cover 1 <0.025>
PSet_Revit_Constraints - Eccentricity: 0 m
PSet_Revit_Dimensions - Width: 0.9 m
PSet_Revit_Phasing - Phase Created: New Construction
PSet_Revit_Structural Analysis - Analyze As: 4
PSet_Revit_Type_Other - AccessibilityPerformance: AccessibilityPerformance; CodePerformance: CodePerformance; Color: Color; Constituents: Constituents; Features: Features; Finish: Finish; Grade: Grade; Material: Material; ModelReference: ModelReference; NominalHeight: NominalHeight; NominalLength: NominalLength; NominalWidth: NominalWidth; ProductionYear: ProductionYear; Reference: Reference; Shape: Shape; Size: Size; SustainabilityPerformance: SustainabilityPerformance; WarrantyDescription: WarrantyDescription; WarrantyDurationLabor: WarrantyDurationLabor; WarrantyDurationParts: WarrantyDurationParts; WarrantyGuarantorLabor: WarrantyGuarantorLabor; WarrantyGuarantorParts: WarrantyGuarantorParts; ExpectedLife: ExpectedLife; ReplacementCost: ReplacementCost; AssetAccountingType: FIXED; Classification Code: 23-25 05 17; Classification Description: Shallow Foundations; ModelLabel: ModelLabel
PSet_Revit_Type_Materials and Finishes - Material: Concrete - Cast In Situ
PSet_Revit_Type_Dimensions - Width: 0.9 m; Foundation Thickness: 0.3 m; Default End Extension Length: 0 m; Do Not Break At Inserts: no
PSet_Revit_Type_Identity Data - Manufacturer: Manufacturer
PSet_Revit_Type_Structural - Structural Usage: 1
Name (Wall Foundation:Bearing Footing - 900 x 300:...) | Length (m) | Volume (m3)
146842 | 26.44 | 4.9788
146830 | 6.05 | 1.0935
224497 | 55.52 | 11.3778
234958 | 2.5352 | 0.927504 | PSet_Revit_Dimensions - Elevation at Bottom: -1.6692 m
146854 | 40.546 | 7.04364
234984 | 2.2352 | 0.684504
234971 | 2.3145 | 0.543915
146902 | 25.956 | 3.645
224398 | 24.84 | 4.11715
146886 | 7.496 | 1.1826
146878 | 10.04 | 2.1708
146866 | 20.06 | 3.7962
234997 | 2.0145 | 0.300915
224163 | 3.84116 | 0.965833
224141 | 8.4796 | 2.44663 | PSet_Revit_Dimensions - Elevation at Bottom: -2.215 m
224176 | 2.96808 | 0.629372
224154 | 4.36065 | 1.2781
224240 | 2.66 | 0.7182
224227 | 3.25276 | 0.949524
224253 | 3.56 | 0.9612

# IfcFooting: Wall Foundation:Retaining Footing - 600 x 300 x 300 (2)
In: TOF Footing
PredefinedType: STRIP_FOOTING
PSet_Revit_Structural Analysis - Analyze As: 4
PSet_Revit_Other - InstallationDate: InstallationDate; SerialNumber: SerialNumber; WarrantyStartDate: WarrantyStartDate; BarCode: BarCode; AssetIdentifier: AssetIdentifier; TagNumber: TagNumber
PSet_Revit_Dimensions - Width: 1.164 m
PSet_Revit_Phasing - Phase Created: New Construction
PSet_Revit_Structural - Rebar Cover - Top Face: Rebar Cover 1 <0.025>; Rebar Cover - Bottom Face: Rebar Cover 1 <0.025>; Rebar Cover - Other Faces: Rebar Cover 1 <0.025>
PSet_Revit_Type_Dimensions - Toe Length: 0.3 m; Heel Length: 0.6 m; Foundation Thickness: 0.3 m; Default End Extension Length: 0 m; Do Not Break At Inserts: no
PSet_Revit_Type_Identity Data - Manufacturer: Manufacturer
PSet_Revit_Type_Materials and Finishes - Material: Concrete - Cast In Situ
PSet_Revit_Type_Other - AccessibilityPerformance: AccessibilityPerformance; CodePerformance: CodePerformance; Color: Color; Constituents: Constituents; Features: Features; Finish: Finish; Grade: Grade; Material: Material; ModelReference: ModelReference; NominalHeight: NominalHeight; NominalLength: NominalLength; NominalWidth: NominalWidth; ProductionYear: ProductionYear; Reference: Reference; Shape: Shape; Size: Size; SustainabilityPerformance: SustainabilityPerformance; WarrantyDescription: WarrantyDescription; WarrantyDurationLabor: WarrantyDurationLabor; WarrantyDurationParts: WarrantyDurationParts; WarrantyGuarantorLabor: WarrantyGuarantorLabor; WarrantyGuarantorParts: WarrantyGuarantorParts; ExpectedLife: ExpectedLife; ReplacementCost: ReplacementCost; AssetAccountingType: FIXED; Classification Code: 23-25 05 17; Classification Description: Shallow Foundations; ModelLabel: ModelLabel
PSet_Revit_Type_Structural - Structural Usage: 0
Name (Wall Foundation:Retaining Footing - 600 x 300 x 300:...) | Length (m) | Volume (m3)
224195 | 10.031 | 3.80453 | PSet_Revit_Dimensions - Elevation at Bottom: -2.215 m
224214 | 18.9795 | 6.43069

# IfcOpeningElement: Opening (7)
PSet_Revit_Constraints - Room Bounding: yes; Related to Mass: no
PSet_Revit_Phasing - Phase Created: New Construction
PSet_Revit_Other - InstallationDate: InstallationDate; SerialNumber: SerialNumber; WarrantyStartDate: WarrantyStartDate; BarCode: BarCode; AssetIdentifier: AssetIdentifier; TagNumber: TagNumber
PSet_Revit_Type_Other - AccessibilityPerformance: AccessibilityPerformance; CodePerformance: CodePerformance; Color: Color; Constituents: Constituents; Features: Features; Finish: Finish; Grade: Grade; Material: Material; ModelReference: ModelReference; NominalHeight: NominalHeight; NominalLength: NominalLength; NominalWidth: NominalWidth; ProductionYear: ProductionYear; Reference: Reference; Shape: Shape; Size: Size; SustainabilityPerformance: SustainabilityPerformance; WarrantyDescription: WarrantyDescription; WarrantyDurationLabor: WarrantyDurationLabor; WarrantyDurationParts: WarrantyDurationParts; WarrantyGuarantorLabor: WarrantyGuarantorLabor; WarrantyGuarantorParts: WarrantyGuarantorParts; ExpectedLife: ExpectedLife; ReplacementCost: ReplacementCost; AssetAccountingType: FIXED; ModelLabel: ModelLabel
PSet_Revit_Type_Graphics - Coarse Scale Fill Color: 0
PSet_Revit_Type_Identity Data - Manufacturer: Manufacturer
Name | In | Pset_SlabCommon, Reference | Pset_SlabCommon, IsExternal = Structural | Pset_SlabCommon, LoadBearing | Level | Height Offset From Level (m) | Vertical Projection | PSet_Revit_Structural Analysis, Structural Usage | Perimeter (m) | Area (m2) | Volume (m3) | Thickness (m) = Default Thickness (m) | Function | Classification Code | Classification Description
Floor:150mm Slab on Grade:164090:2 | First Floor | Floor:150mm Slab on Grade | no | yes | First Floor | 0 | Default | 3 | 224.907 | 2573.59 | 386.038 | 0.15 | 1 | 23-25 30 27 11 | Structural Floor Decks
Floor:64mm Concrete With 38mm Metal Deck:164823:2 | Second Floor | Floor:64mm Concrete With 38mm Metal Deck | no | yes | Second Floor | 0 | Default | 3 | 279.566 | 1721.07 | 175.549 | 0.102 | 0 | 23-25 30 27 11 | Structural Floor Decks
Floor:64mm Concrete With 38mm Metal Deck:164823:5 | Second Floor | Floor:64mm Concrete With 38mm Metal Deck | no | yes | Second Floor | 0 | Default | 3 | 279.566 | 1721.07 | 175.549 | 0.102 | 0 | 23-25 30 27 11 | Structural Floor Decks
Floor:64mm Concrete With 38mm Metal Deck:164823:4 | Second Floor | Floor:64mm Concrete With 38mm Metal Deck | no | yes | Second Floor | 0 | Default | 3 | 279.566 | 1721.07 | 175.549 | 0.102 | 0 | 23-25 30 27 11 | Structural Floor Decks
Floor:64mm Concrete With 38mm Metal Deck:164823:3 | Second Floor | Floor:64mm Concrete With 38mm Metal Deck | no | yes | Second Floor | 0 | Default | 3 | 279.566 | 1721.07 | 175.549 | 0.102 | 0 | 23-25 30 27 11 | Structural Floor Decks
Basic Wall:Foundation - Concrete (264mm):233503:2 | TOF Footing |  |  |  |  |  |  |  |  | 2.10953 | 0.556916 |  | 2 | 23-25 30 24 11 | Concrete Structural Walls | PSet_Revit_Structural - Rebar Cover - Exterior Face: Rebar Cover 1 <0.025>; Rebar Cover - Interior Face: Rebar Cover 1 <0.025>; Rebar Cover - Other Faces: Rebar Cover 1 <0.025>; Structural Usage: 1; PSet_Revit_Analytical Model - Enable Analytical Model: yes; Pset_WallCommon - Reference: Basic Wall:Foundation - Concrete (264mm); LoadBearing: yes; ExtendToStructure: no; IsExternal: yes; PSet_Revit_Constraints - Location Line: 2; Base Constraint: TOF Footing; Base Offset: -0.915 m; Base is Attached: no; Base Extension Distance: 0 m; Top Constraint: Up to level: First Floor; Unconnected Height: 1.765 m; Top Offset: -0.15 m; Top is Attached: no; Top Extension Distance: 0 m; PSet_Revit_Dimensions - Length: 1.548 m; PSet_Revit_Type_Graphics - Coarse Scale Fill Pattern: Concrete; PSet_Revit_Type_Construction - Wrapping at Inserts: 0; Wrapping at Ends: 0; Width: 0.264 m
Basic Wall:Foundation - Concrete (264mm):233007:2 | TOF Footing |  |  |  |  |  |  |  |  | 1.86797 | 0.493145 |  | 2 | 23-25 30 24 11 | Concrete Structural Walls | PSet_Revit_Structural - Rebar Cover - Exterior Face: Rebar Cover 1 <0.025>; Rebar Cover - Interior Face: Rebar Cover 1 <0.025>; Rebar Cover - Other Faces: Rebar Cover 1 <0.025>; Structural Usage: 1; PSet_Revit_Analytical Model - Enable Analytical Model: yes; Pset_WallCommon - Reference: Basic Wall:Foundation - Concrete (264mm); LoadBearing: yes; ExtendToStructure: no; IsExternal: yes; PSet_Revit_Constraints - Location Line: 2; Base Constraint: TOF Footing; Base Offset: -0.915 m; Base is Attached: no; Base Extension Distance: 0 m; Top Constraint: Up to level: First Floor; Unconnected Height: 1.765 m; Top Offset: -0.15 m; Top is Attached: no; Top Extension Distance: 0 m; PSet_Revit_Dimensions - Length: 1.548 m; PSet_Revit_Type_Graphics - Coarse Scale Fill Pattern: Concrete; PSet_Revit_Type_Construction - Wrapping at Inserts: 0; Wrapping at Ends: 0; Width: 0.264 m

# IfcRailing: Railing:900mm Pipe Guard Rail (3)
In: TOF Footing
PSet_Revit_Constraints - Base Offset: 0 m
PSet_Revit_Other - InstallationDate: InstallationDate; SerialNumber: SerialNumber; WarrantyStartDate: WarrantyStartDate; BarCode: BarCode; AssetIdentifier: AssetIdentifier; TagNumber: TagNumber
PSet_Revit_Phasing - Phase Created: New Construction
Pset_RailingCommon - Reference: Railing:900mm Pipe Guard Rail; IsExternal: no; Height: 0.9
PSet_Revit_Type_Construction - Railing Height: 0.9 m; Baluster Offset: -0.025 m; Use Landing Height Adjustment: 0; Landing Height Adjustment: 0 m; Angled Joins: 0; Tangent Joins: 2; Rail Connections: 0
PSet_Revit_Type_Identity Data - Manufacturer: Manufacturer
PSet_Revit_Type_Other - AccessibilityPerformance: AccessibilityPerformance; CodePerformance: CodePerformance; Color: Color; Constituents: Constituents; Features: Features; Finish: Finish; Grade: Grade; Material: Material; ModelReference: ModelReference; NominalHeight: NominalHeight; NominalLength: NominalLength; NominalWidth: NominalWidth; ProductionYear: ProductionYear; Reference: Reference; Shape: Shape; Size: Size; SustainabilityPerformance: SustainabilityPerformance; WarrantyDescription: WarrantyDescription; WarrantyDurationLabor: WarrantyDurationLabor; WarrantyDurationParts: WarrantyDurationParts; WarrantyGuarantorLabor: WarrantyGuarantorLabor; WarrantyGuarantorParts: WarrantyGuarantorParts; ExpectedLife: ExpectedLife; ReplacementCost: ReplacementCost; AssetAccountingType: FIXED; Classification Code: 23-30 80 11; Classification Description: Guardrails; ModelLabel: ModelLabel
Name (Railing:900mm Pipe Guard Rail:...) | Length (m)
222620 | 2.5151
221723 | 8.53408
222624 | 2.5151

# IfcRamp: Ramp:150mm Concrete ADA Ramp, Ramp:150mm Concrete ADA Ramp:221707
In: TOF Footing
ShapeType: STRAIGHT_RUN_RAMP
PSet_Revit_Type_Identity Data - Manufacturer: Manufacturer
PSet_Revit_Type_Graphics - Text Size: 0.0082021; Text Font: Arial
PSet_Revit_Type_Dimensions - Maximum Incline Length: 10 m
PSet_Revit_Type_Other - Ramp Max Slope (1/x): 12; Shape: 0; AccessibilityPerformance: AccessibilityPerformance; CodePerformance: CodePerformance; Color: Color; Constituents: Constituents; Features: Features; Finish: Finish; Grade: Grade; Material: Material; ModelReference: ModelReference; NominalHeight: NominalHeight; NominalLength: NominalLength; NominalWidth: NominalWidth; ProductionYear: ProductionYear; Reference: Reference; Size: Size; SustainabilityPerformance: SustainabilityPerformance; WarrantyDescription: WarrantyDescription; WarrantyDurationLabor: WarrantyDurationLabor; WarrantyDurationParts: WarrantyDurationParts; WarrantyGuarantorLabor: WarrantyGuarantorLabor; WarrantyGuarantorParts: WarrantyGuarantorParts; ExpectedLife: ExpectedLife; ReplacementCost: ReplacementCost; AssetAccountingType: FIXED; Classification Code: 23-30 70 11; Classification Description: Ramps; ModelLabel: ModelLabel
PSet_Revit_Type_Construction - Thickness: 0.15 m; Function: 1
PSet_Revit_Type_Materials and Finishes - Ramp Material: Concrete - Cast In Situ
PSet_Revit_Phasing - Phase Created: New Construction
Pset_RampCommon - Reference: Ramp:150mm Concrete ADA Ramp; IsExternal: no
PSet_Revit_Dimensions - Width: 1 m
PSet_Revit_Other - InstallationDate: InstallationDate; SerialNumber: SerialNumber; WarrantyStartDate: WarrantyStartDate; BarCode: BarCode; AssetIdentifier: AssetIdentifier; TagNumber: TagNumber
PSet_Revit_Graphics - Up text: UP; Down text: DN; Up label: yes; Down label: yes; Show Up arrow in all views: no
PSet_Revit_Constraints - Base Level: TOF Footing; Base Offset: 0.2913 m; Top Level: First Floor; Top Offset: 0 m

# IfcRampFlight: Ramp:150mm Concrete ADA Ramp, Ramp:150mm Concrete ADA Ramp:221707:1
In: TOF Footing
Pset_RampFlightCommon - Reference: Ramp:150mm Concrete ADA Ramp; Slope: 4.76353 deg

# IfcRoof: Basic Roof:EPDM Membrane on Rigid Insul on Metal Deck (7)
Material: Roofing - EPDM Membrane 0.006 m, Insulation / Thermal Barriers - Rigid insulation 0.076 m, Metal - Decking 0.038 m
PSet_Revit_Construction - Rafter Cut: 33615; Fascia Depth: 0 m
Pset_RoofCommon - Reference: Basic Roof:EPDM Membrane on Rigid Insul on Metal Deck; IsExternal: no
PSet_Revit_Phasing - Phase Created: New Construction
PSet_Revit_Constraints - Room Bounding: yes; Related to Mass: no; Cutoff Offset: 0 m
PSet_Revit_Dimensions - Thickness: 0.12 m
PSet_Revit_Other - InstallationDate: InstallationDate; SerialNumber: SerialNumber; WarrantyStartDate: WarrantyStartDate; BarCode: BarCode; AssetIdentifier: AssetIdentifier; TagNumber: TagNumber
PSet_Revit_Type_Graphics - Coarse Scale Fill Color: 0
PSet_Revit_Type_Other - AccessibilityPerformance: AccessibilityPerformance; CodePerformance: CodePerformance; Color: Color; Constituents: Constituents; Features: Features; Finish: Finish; Grade: Grade; Material: Material; ModelReference: ModelReference; NominalHeight: NominalHeight; NominalLength: NominalLength; NominalWidth: NominalWidth; ProductionYear: ProductionYear; Reference: Reference; Shape: Shape; Size: Size; SustainabilityPerformance: SustainabilityPerformance; WarrantyDescription: WarrantyDescription; WarrantyDurationLabor: WarrantyDurationLabor; WarrantyDurationParts: WarrantyDurationParts; WarrantyGuarantorLabor: WarrantyGuarantorLabor; WarrantyGuarantorParts: WarrantyGuarantorParts; ExpectedLife: ExpectedLife; ReplacementCost: ReplacementCost; AssetAccountingType: FIXED; Classification Code: 23-25 30 27 14; Classification Description: Structural Roof Decks; ModelLabel: ModelLabel
PSet_Revit_Type_Identity Data - Manufacturer: Manufacturer
PSet_Revit_Type_Construction - Default Thickness: 0.12 m
Name (Basic Roof:EPDM Membrane on Rigid Insul on Metal Deck:...) | In | Maximum Ridge Height (m) | TotalArea (m2) = ProjectedArea (m2) = Area (m2) | Base Level | Base Offset From Level (m) | Volume (m3)
190761 | Roof - Main | 9.37 | 1580.23 | Roof - Main | 0 | 189.628
192693 | Second Floor | 4.588 | 54.5702 | Second Floor | -0.102 | 6.54843
234334 | Roof - Main | 6.7615 | 10.7656 | Roof - Main | -2.6085 | 1.29188
234228 | Roof - Main | 8.0565 | 14.9329 | Roof - Main | -1.3135 | 1.79195
192254 | Second Floor | 4.588 | 600.734 | Second Floor | -0.102 | 72.0881
234248 | Roof - Main | 6.7615 | 10.7656 | Roof - Main | -2.6085 | 1.29188
234050 | Roof - Main | 8.0565 | 14.9329 | Roof - Main | -1.3135 | 1.79195

# IfcRoof: Basic Roof:Standing Seam Metal Roof (5)
In: Roof - Main
Material: Roofing - Metal 0.006 m, Metal - Decking 0.038 m, Structure - Steel Bar Joist Layer 0.286 m
PSet_Revit_Other - InstallationDate: InstallationDate; SerialNumber: SerialNumber; WarrantyStartDate: WarrantyStartDate; BarCode: BarCode; AssetIdentifier: AssetIdentifier; TagNumber: TagNumber
PSet_Revit_Dimensions - Thickness: 0.33 m
PSet_Revit_Constraints - Work Plane: <not associated>; Room Bounding: yes; Related to Mass: no; Reference Level: Roof - Main; Level Offset: 0 m
PSet_Revit_Phasing - Phase Created: New Construction
PSet_Revit_Construction - Fascia Depth: 0 m; Rafter Cut: 33615
Pset_RoofCommon - Reference: Basic Roof:Standing Seam Metal Roof; IsExternal: yes
PSet_Revit_Type_Identity Data - Manufacturer: Manufacturer
PSet_Revit_Type_Construction - Default Thickness: 0.33 m
PSet_Revit_Type_Graphics - Coarse Scale Fill Color: 0
PSet_Revit_Type_Other - AccessibilityPerformance: AccessibilityPerformance; CodePerformance: CodePerformance; Color: Color; Constituents: Constituents; Features: Features; Finish: Finish; Grade: Grade; Material: Material; ModelReference: ModelReference; NominalHeight: NominalHeight; NominalLength: NominalLength; NominalWidth: NominalWidth; ProductionYear: ProductionYear; Reference: Reference; Shape: Shape; Size: Size; SustainabilityPerformance: SustainabilityPerformance; WarrantyDescription: WarrantyDescription; WarrantyDurationLabor: WarrantyDurationLabor; WarrantyDurationParts: WarrantyDurationParts; WarrantyGuarantorLabor: WarrantyGuarantorLabor; WarrantyGuarantorParts: WarrantyGuarantorParts; ExpectedLife: ExpectedLife; ReplacementCost: ReplacementCost; AssetAccountingType: FIXED; Classification Code: 23-25 30 27 14; Classification Description: Structural Roof Decks; ModelLabel: ModelLabel
Name (Basic Roof:Standing Seam Metal Roof:...) | Volume (m3) | Area (m2) = TotalArea (m2) | Extrusion Start (m) | Extrusion End (m) | ProjectedArea (m2)
194944 | 8.63729 | 26.2142 | 44.5165 | 49.746 | 25.4478
194845 | 13.7691 | 41.8856 | 24.65 | 32.8006 | 39.7738
194478 | 80.9981 | 245.916 | -7.814 | 13.5665 | 232.96
194664 | 19.4968 | 59.2509 | 18.2905 | 26.4478 | 56.1935
194564 | 27.1875 | 82.5771 | 11.1665 | 19.9665 | 78.2652

# IfcSlab: Basic Roof:EPDM Membrane on Rigid Insul on Metal Deck (7)
PredefinedType: ROOF
Name (Basic Roof:EPDM Membrane on Rigid Insul on Metal Deck:...) | In
192693 | Second Floor
234334 | Roof - Main
190761 | Roof - Main
234248 | Roof - Main
234050 | Roof - Main
234228 | Roof - Main
192254 | Second Floor

# IfcSlab: Floor:150mm Exterior Slab on Grade, Floor:150mm Exterior Slab on Grade:240432
In: First Floor
PredefinedType: FLOOR; Material: Concrete - Cast In Situ 0.15 m
PSet_Revit_Type_Graphics - Coarse Scale Fill Color: 0
PSet_Revit_Type_Identity Data - Manufacturer: Manufacturer
PSet_Revit_Type_Other - AccessibilityPerformance: AccessibilityPerformance; CodePerformance: CodePerformance; Color: Color; Constituents: Constituents; Features: Features; Finish: Finish; Grade: Grade; Material: Material; ModelReference: ModelReference; NominalHeight: NominalHeight; NominalLength: NominalLength; NominalWidth: NominalWidth; ProductionYear: ProductionYear; Reference: Reference; Shape: Shape; Size: Size; SustainabilityPerformance: SustainabilityPerformance; WarrantyDescription: WarrantyDescription; WarrantyDurationLabor: WarrantyDurationLabor; WarrantyDurationParts: WarrantyDurationParts; WarrantyGuarantorLabor: WarrantyGuarantorLabor; WarrantyGuarantorParts: WarrantyGuarantorParts; ExpectedLife: ExpectedLife; ReplacementCost: ReplacementCost; AssetAccountingType: FIXED; Classification Code: 23-25 30 27 11; Classification Description: Structural Floor Decks; ModelLabel: ModelLabel
PSet_Revit_Type_Construction - Default Thickness: 0.15 m; Function: 1
Pset_SlabCommon - Reference: Floor:150mm Exterior Slab on Grade; IsExternal: no; LoadBearing: yes
PSet_Revit_Constraints - Level: First Floor; Height Offset From Level: -1 m; Room Bounding: yes; Related to Mass: no
PSet_Revit_Analytical Model - Vertical Projection: Default
PSet_Revit_Structural Analysis - Structural Usage: 3
PSet_Revit_Structural - Structural: no
PSet_Revit_Phasing - Phase Created: New Construction
PSet_Revit_Other - InstallationDate: InstallationDate; SerialNumber: SerialNumber; WarrantyStartDate: WarrantyStartDate; BarCode: BarCode; AssetIdentifier: AssetIdentifier; TagNumber: TagNumber
PSet_Revit_Dimensions - Perimeter: 57.493 m; Area: 167.32 m2; Volume: 25.0979 m3; Thickness: 0.15 m

# IfcSlab: Floor:150mm Slab on Grade (3)
In: First Floor
PredefinedType: FLOOR; Material: Concrete - Cast In Situ 0.15 m
Pset_SlabCommon - Reference: Floor:150mm Slab on Grade; IsExternal: no; LoadBearing: yes
PSet_Revit_Constraints - Level: First Floor; Room Bounding: yes; Related to Mass: no
PSet_Revit_Structural - Structural: no
PSet_Revit_Analytical Model - Vertical Projection: Default
PSet_Revit_Phasing - Phase Created: New Construction
PSet_Revit_Other - InstallationDate: InstallationDate; SerialNumber: SerialNumber; WarrantyStartDate: WarrantyStartDate; BarCode: BarCode; AssetIdentifier: AssetIdentifier; TagNumber: TagNumber
PSet_Revit_Structural Analysis - Structural Usage: 3
PSet_Revit_Dimensions - Thickness: 0.15 m
PSet_Revit_Type_Construction - Default Thickness: 0.15 m; Function: 1
PSet_Revit_Type_Other - AccessibilityPerformance: AccessibilityPerformance; CodePerformance: CodePerformance; Color: Color; Constituents: Constituents; Features: Features; Finish: Finish; Grade: Grade; Material: Material; ModelReference: ModelReference; NominalHeight: NominalHeight; NominalLength: NominalLength; NominalWidth: NominalWidth; ProductionYear: ProductionYear; Reference: Reference; Shape: Shape; Size: Size; SustainabilityPerformance: SustainabilityPerformance; WarrantyDescription: WarrantyDescription; WarrantyDurationLabor: WarrantyDurationLabor; WarrantyDurationParts: WarrantyDurationParts; WarrantyGuarantorLabor: WarrantyGuarantorLabor; WarrantyGuarantorParts: WarrantyGuarantorParts; ExpectedLife: ExpectedLife; ReplacementCost: ReplacementCost; AssetAccountingType: FIXED; Classification Code: 23-25 30 27 11; Classification Description: Structural Floor Decks; ModelLabel: ModelLabel
PSet_Revit_Type_Graphics - Coarse Scale Fill Color: 0
PSet_Revit_Type_Identity Data - Manufacturer: Manufacturer
Name (Floor:150mm Slab on Grade:...) | Height Offset From Level (m) | Perimeter (m) | Area (m2) | Volume (m3)
164090 | 0 | 224.907 | 2573.59 | 386.038
235000 | -1.2196 | 7.8994 | 3.83225 | 0.574838
221475 | 0 | 28.5682 | 43.6555 | 6.54833

# IfcSlab: Floor:64mm Concrete With 38mm Metal Deck (2)
PredefinedType: FLOOR; Material: Concrete - Cast in Situ Lightweight 0.064 m, Metal - Decking 0.038 m
PSet_Revit_Structural Analysis - Structural Usage: 3
PSet_Revit_Structural - Structural: no
PSet_Revit_Dimensions - Thickness: 0.102 m
PSet_Revit_Constraints - Room Bounding: yes; Related to Mass: no
PSet_Revit_Phasing - Phase Created: New Construction
Pset_SlabCommon - Reference: Floor:64mm Concrete With 38mm Metal Deck; IsExternal: no; LoadBearing: yes
PSet_Revit_Other - InstallationDate: InstallationDate; SerialNumber: SerialNumber; WarrantyStartDate: WarrantyStartDate; BarCode: BarCode; AssetIdentifier: AssetIdentifier; TagNumber: TagNumber
PSet_Revit_Analytical Model - Vertical Projection: Default
PSet_Revit_Type_Construction - Default Thickness: 0.102 m; Function: 0
PSet_Revit_Type_Graphics - Coarse Scale Fill Color: 0
PSet_Revit_Type_Other - AccessibilityPerformance: AccessibilityPerformance; CodePerformance: CodePerformance; Color: Color; Constituents: Constituents; Features: Features; Finish: Finish; Grade: Grade; Material: Material; ModelReference: ModelReference; NominalHeight: NominalHeight; NominalLength: NominalLength; NominalWidth: NominalWidth; ProductionYear: ProductionYear; Reference: Reference; Shape: Shape; Size: Size; SustainabilityPerformance: SustainabilityPerformance; WarrantyDescription: WarrantyDescription; WarrantyDurationLabor: WarrantyDurationLabor; WarrantyDurationParts: WarrantyDurationParts; WarrantyGuarantorLabor: WarrantyGuarantorLabor; WarrantyGuarantorParts: WarrantyGuarantorParts; ExpectedLife: ExpectedLife; ReplacementCost: ReplacementCost; AssetAccountingType: FIXED; Classification Code: 23-25 30 27 11; Classification Description: Structural Floor Decks; ModelLabel: ModelLabel
PSet_Revit_Type_Identity Data - Manufacturer: Manufacturer
Name (Floor:64mm Concrete With 38mm Metal Deck:...) | In | Perimeter (m) | Area (m2) | Volume (m3) | Level | Height Offset From Level (m)
164823 | Second Floor | 279.566 | 1721.07 | 175.549 | Second Floor | 0
235649 | Roof - Main | 35.888 | 65.2405 | 6.65453 | Roof - Main | 0.102

# IfcStair: Stair:Monolithic Concrete Stair, Stair:Monolithic Concrete Stair:222487
In: TOF Footing
ShapeType: STRAIGHT_RUN_STAIR
PSet_Revit_Type_Materials and Finishes - Tread Material: Concrete - Cast In Situ; Riser Material: Concrete - Cast In Situ; Monolithic Material: Concrete - Cast In Situ
PSet_Revit_Type_Treads - Minimum Tread Depth: 0.28 m; Tread Thickness: 0 m; Nosing Length: 0 m; Apply Nosing Profile: 0
PSet_Revit_Type_Risers - Maximum Riser Height: 0.18 m; Begin with Riser: yes; End with Riser: no; Riser Type: 1; Riser Thickness: 0 m; Riser to Tread Connection: 0
PSet_Revit_Type_Stringers - Trim Stringers at Top: 0; Right Stringer: 1; Left Stringer: 1; Middle Stringers: 0; Stringer Thickness: 0.05 m; Stringer Height: 0.4 m; Open Stringer Offset: 0 m; Stringer Carriage Height: 0.15 m; Landing Carriage Height: 0.3 m
PSet_Revit_Type_Graphics - Break Symbol in Plan: yes; Text Size: 0.0082021; Text Font: Arial
PSet_Revit_Type_Identity Data - Manufacturer: Manufacturer
PSet_Revit_Type_Other - AccessibilityPerformance: AccessibilityPerformance; CodePerformance: CodePerformance; Color: Color; Constituents: Constituents; Features: Features; Finish: Finish; Grade: Grade; Material: Material; ModelReference: ModelReference; NominalHeight: NominalHeight; NominalLength: NominalLength; NominalWidth: NominalWidth; ProductionYear: ProductionYear; Reference: Reference; Shape: Shape; Size: Size; SustainabilityPerformance: SustainabilityPerformance; WarrantyDescription: WarrantyDescription; WarrantyDurationLabor: WarrantyDurationLabor; WarrantyDurationParts: WarrantyDurationParts; WarrantyGuarantorLabor: WarrantyGuarantorLabor; WarrantyGuarantorParts: WarrantyGuarantorParts; ExpectedLife: ExpectedLife; ReplacementCost: ReplacementCost; AssetAccountingType: FIXED; Classification Code: 23-30 70 21; Classification Description: Stairs; ModelLabel: ModelLabel
PSet_Revit_Type_Construction - Extend Below Base: 0 m; Monolithic Stairs: yes; Landing Overlap: 0.076 m; Underside of Winder: 1; Function: 1
PSet_Revit_Structural - Rebar Cover: Rebar Cover 1 <0.025>
PSet_Revit_Phasing - Phase Created: New Construction
PSet_Revit_Constraints - Base Level: TOF Footing; Base Offset: 0 m; Top Level: First Floor; Top Offset: 0 m
PSet_Revit_Other - InstallationDate: InstallationDate; SerialNumber: SerialNumber; WarrantyStartDate: WarrantyStartDate; BarCode: BarCode; AssetIdentifier: AssetIdentifier; TagNumber: TagNumber
Pset_StairCommon - Reference: Stair:Monolithic Concrete Stair; NumberOfRiser: 6; NumberOfTreads: 6; RiserHeight: 0.166667 m; TreadLength: 0.28 m; IsExternal: no
PSet_Revit_Graphics - Up text: UP; Down text: DN; Up label: yes; Up arrow: yes; Down label: yes; Down arrow: yes; Show Up arrow in all views: no
PSet_Revit_Dimensions - Width: 1 m; Desired Number of Risers: 6; Actual Number of Risers: 6; Actual Riser Height: 0.166667 m; Actual Tread Depth: 0.28 m

# IfcStairFlight: Stair:Monolithic Concrete Stair, Stair:Monolithic Concrete Stair:222487:1
In: TOF Footing
NumberOfRiser: 6; NumberOfTreads: 6; RiserHeight: 0.546807 m; TreadLength: 0.918635 m
Pset_StairFlightCommon - Reference: Stair:Monolithic Concrete Stair; NumberOfRiser: 6; NumberOfTreads: 6; RiserHeight: 0.166667 m; TreadLength: 0.28 m; TreadLengthAtInnerSide: 0.28 m; TreadLengthAtOffset: 0.28 m; WalkingLineOffset: 0.625 m; WaistThickness: 1.25 m

# IfcWallStandardCase: Basic Wall:Foundation - Concrete (264mm):128600 (22)
In: TOF Footing
Material: Concrete - Cast In Situ 0.264 m
PSet_Revit_Other - InstallationDate: InstallationDate; SerialNumber: SerialNumber; WarrantyStartDate: WarrantyStartDate; BarCode: BarCode; AssetIdentifier: AssetIdentifier; TagNumber: TagNumber
PSet_Revit_Phasing - Phase Created: New Construction
Pset_WallCommon - Reference: Basic Wall:Foundation - Concrete (264mm); ExtendToStructure: no; IsExternal: yes
PSet_Revit_Constraints - Location Line: 2; Base Constraint: TOF Footing; Base is Attached: no; Base Extension Distance: 0 m; Top is Attached: no; Top Extension Distance: 0 m; Room Bounding: yes; Related to Mass: no
PSet_Revit_Type_Identity Data - Manufacturer: Manufacturer
PSet_Revit_Type_Graphics - Coarse Scale Fill Pattern: Concrete; Coarse Scale Fill Color: 0
PSet_Revit_Type_Construction - Wrapping at Inserts: 0; Wrapping at Ends: 0; Width: 0.264 m; Function: 2
PSet_Revit_Type_Other - AccessibilityPerformance: AccessibilityPerformance; CodePerformance: CodePerformance; Color: Color; Constituents: Constituents; Features: Features; Finish: Finish; Grade: Grade; Material: Material; ModelReference: ModelReference; NominalHeight: NominalHeight; NominalLength: NominalLength; NominalWidth: NominalWidth; ProductionYear: ProductionYear; Reference: Reference; Shape: Shape; Size: Size; SustainabilityPerformance: SustainabilityPerformance; WarrantyDescription: WarrantyDescription; WarrantyDurationLabor: WarrantyDurationLabor; WarrantyDurationParts: WarrantyDurationParts; WarrantyGuarantorLabor: WarrantyGuarantorLabor; WarrantyGuarantorParts: WarrantyGuarantorParts; ExpectedLife: ExpectedLife; ReplacementCost: ReplacementCost; AssetAccountingType: FIXED; Classification Code: 23-25 30 24 11; Classification Description: Concrete Structural Walls; ModelLabel: ModelLabel
Name (Basic Wall:Foundation - Concrete (264mm):...) | LoadBearing | Length (m) | Area (m2) | Volume (m3) | Rebar Cover - Exterior Face = Rebar Cover - Interior Face = Rebar Cover - Other Faces | Structural Usage | Base Offset (m) | Top Constraint | Unconnected Height (m) | Top Offset (m) | Enable Analytical Model
224397 | yes | 24.708 | 47.5686 | 12.5581 | Rebar Cover 1 <0.025> | 1 | -0.915 | Up to level: First Floor | 1.915 | 0 | yes
221372 | yes | 4.54732 | 7.69654 | 1.97038 | Rebar Cover 1 <0.025> | 1 | -0.915 | Up to level: First Floor | 1.765 | -0.15 | yes
146569 | yes | 1.248 | 2.13714 | 0.564205 | Rebar Cover 1 <0.025> | 1 | -0.915 | Up to level: First Floor | 1.915 | 0 | yes
221320 | yes | 3.57716 | 6.77964 | 1.66681 | Rebar Cover 1 <0.025> | 1 | -0.915 | Up to level: First Floor | 1.765 | -0.15 | yes
224496 | no | 55.388 | 55.52 | 14.6573 |  | 0 | 0 | Up to level: First Floor | 1 | 0
233503 | yes | 1.548 | 2.10953 | 0.556916 | Rebar Cover 1 <0.025> | 1 | -0.915 | Up to level: First Floor | 1.765 | -0.15 | yes
146481 | no | 7.628 | 7.496 | 1.97894 |  | 0 | 0 | Up to level: First Floor | 1 | 0
221232 | yes | 2.51741 | 5.23866 | 1.3215 | Rebar Cover 1 <0.025> | 1 | -0.915 | Up to level: First Floor | 1.765 | -0.15 | yes
220785 | yes | 3.56 | 6.2834 | 1.65882 | Rebar Cover 1 <0.025> | 1 | -0.915 | Up to level: First Floor | 1.765 | -0.15 | yes
145934 | no | 26.44 | 26.44 | 6.98016 |  | 0 | 0 | Up to level: First Floor | 1 | 0
233007 | yes | 1.548 | 1.86797 | 0.493145 | Rebar Cover 1 <0.025> | 1 | -0.915 | Up to level: First Floor | 1.765 | -0.15 | yes
221174 | yes | 3.51676 | 5.74112 | 1.51565 | Rebar Cover 1 <0.025> | 1 | -0.915 | Up to level: First Floor | 1.765 | -0.15 | yes
146642 | no | 6.05 | 6.05 | 1.5972 |  | 0 | 0 | Up to level: First Floor | 1 | 0
220841 | yes | 2.66 | 4.6949 | 1.23945 | Rebar Cover 1 <0.025> | 1 | -0.915 | Up to level: First Floor | 1.765 | -0.15 | yes
232959 | yes | 0.986 | 0.90219 | 0.238178 | Rebar Cover 1 <0.025> | 1 | -0.915 | Up to level: TOF Footing | 0.915 | 0 | yes
146312 | no | 10.04 | 10.04 | 2.65056 |  | 0 | 0 | Up to level: First Floor | 1 | 0
223568 | yes | 10.163 | 22.8205 | 6.02462 | Rebar Cover 1 <0.025> | 1 | -0.915 | Up to level: TOF Footing | 2.275 | 1.36 | yes
146239 | no | 20.06 | 20.06 | 5.29584 |  | 0 | 0 | Up to level: First Floor | 1 | 0
223413 | yes | 18.8475 | 43.1784 | 11.3991 | Rebar Cover 1 <0.025> | 1 | -0.915 | Up to level: TOF Footing | 2.275 | 1.36 | yes
146143 | no | 40.546 | 40.546 | 10.7041 |  | 0 | 0 | Up to level: First Floor | 1 | 0
146607 | no | 25.956 | 25.956 | 6.85238 |  | 0 | 0 | Up to level: First Floor | 1 | 0
221623 | yes | 8.6116 | 11.9661 | 3.15905 | Rebar Cover 1 <0.025> | 1 | -0.915 | Up to level: First Floor | 1.915 | 0 | yes

# IfcWallStandardCase: Basic Wall:Foundation - Concrete (300mm):131172 (4)
In: TOF Footing
Material: Concrete - Cast In Situ 0.3 m
PSet_Revit_Phasing - Phase Created: New Construction
PSet_Revit_Constraints - Location Line: 2; Base Constraint: First Floor; Base Offset: -1.3692 m; Base is Attached: no; Base Extension Distance: 0 m; Top Constraint: Up to level: First Floor; Unconnected Height: 1.2192 m; Top Offset: -0.15 m; Top is Attached: no; Top Extension Distance: 0 m; Room Bounding: yes; Related to Mass: no
PSet_Revit_Other - InstallationDate: InstallationDate; SerialNumber: SerialNumber; WarrantyStartDate: WarrantyStartDate; BarCode: BarCode; AssetIdentifier: AssetIdentifier; TagNumber: TagNumber
Pset_WallCommon - Reference: Basic Wall:Foundation - Concrete (300mm); LoadBearing: yes; ExtendToStructure: no; IsExternal: yes
PSet_Revit_Structural - Rebar Cover - Exterior Face: Rebar Cover 1 <0.025>; Rebar Cover - Interior Face: Rebar Cover 1 <0.025>; Rebar Cover - Other Faces: Rebar Cover 1 <0.025>; Structural Usage: 1
PSet_Revit_Analytical Model - Enable Analytical Model: yes
PSet_Revit_Type_Other - AccessibilityPerformance: AccessibilityPerformance; CodePerformance: CodePerformance; Color: Color; Constituents: Constituents; Features: Features; Finish: Finish; Grade: Grade; Material: Material; ModelReference: ModelReference; NominalHeight: NominalHeight; NominalLength: NominalLength; NominalWidth: NominalWidth; ProductionYear: ProductionYear; Reference: Reference; Shape: Shape; Size: Size; SustainabilityPerformance: SustainabilityPerformance; WarrantyDescription: WarrantyDescription; WarrantyDurationLabor: WarrantyDurationLabor; WarrantyDurationParts: WarrantyDurationParts; WarrantyGuarantorLabor: WarrantyGuarantorLabor; WarrantyGuarantorParts: WarrantyGuarantorParts; ExpectedLife: ExpectedLife; ReplacementCost: ReplacementCost; AssetAccountingType: FIXED; Classification Code: 23-25 30 24 11; Classification Description: Concrete Structural Walls; ModelLabel: ModelLabel
PSet_Revit_Type_Graphics - Coarse Scale Fill Pattern: Concrete; Coarse Scale Fill Color: 0
PSet_Revit_Type_Identity Data - Manufacturer: Manufacturer
PSet_Revit_Type_Construction - Wrapping at Inserts: 0; Wrapping at Ends: 0; Width: 0.3 m; Function: 2
Name (Basic Wall:Foundation - Concrete (300mm):...) | Length (m) | Area (m2) | Volume (m3)
234820 | 2.0145 | 2.45608 | 0.736824
234726 | 2.5352 | 3.09092 | 0.927275
234869 | 2.5352 | 2.72516 | 0.817547
234676 | 2.0145 | 2.82184 | 0.846552
